VERSION 5.8 ;
BUSBITCHARS "[]" ;
DIVIDERCHAR "/" ;
UNITS
    DATABASE MICRONS 1000 ;
END UNITS

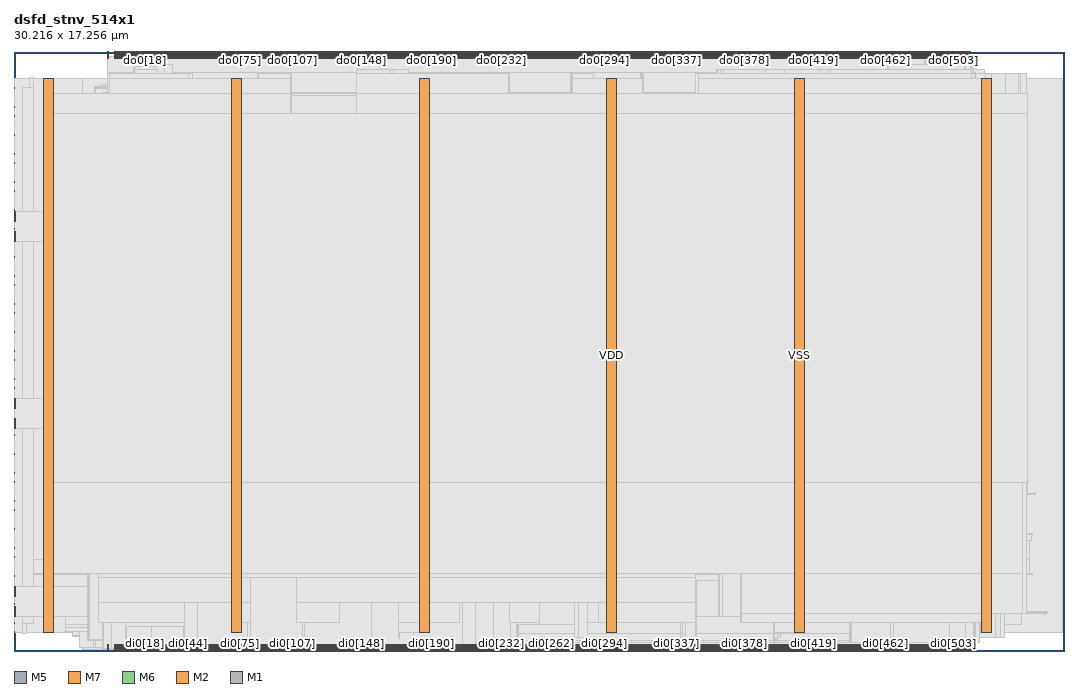
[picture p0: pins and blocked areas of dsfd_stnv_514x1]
MACRO dsfd_stnv_514x1
  FOREIGN dsfd_stnv_514x1 0 0 ;
  CLASS BLOCK ;
  SIZE 30.216 BY 17.256 ;
  PIN di0[0]
    DIRECTION INPUT ;
    USE SIGNAL ;
    PORT
      LAYER M5 ;
        RECT  2.88 0 2.904 0.192 ;
    END
  END di0[0]
  PIN di0[100]
    DIRECTION INPUT ;
    USE SIGNAL ;
    PORT
      LAYER M5 ;
        RECT  7.68 0 7.704 0.192 ;
    END
  END di0[100]
  PIN di0[101]
    DIRECTION INPUT ;
    USE SIGNAL ;
    PORT
      LAYER M5 ;
        RECT  7.728 0 7.752 0.192 ;
    END
  END di0[101]
  PIN di0[102]
    DIRECTION INPUT ;
    USE SIGNAL ;
    PORT
      LAYER M5 ;
        RECT  7.776 0 7.8 0.192 ;
    END
  END di0[102]
  PIN di0[103]
    DIRECTION INPUT ;
    USE SIGNAL ;
    PORT
      LAYER M5 ;
        RECT  7.824 0 7.848 0.192 ;
    END
  END di0[103]
  PIN di0[104]
    DIRECTION INPUT ;
    USE SIGNAL ;
    PORT
      LAYER M5 ;
        RECT  7.872 0 7.896 0.192 ;
    END
  END di0[104]
  PIN di0[105]
    DIRECTION INPUT ;
    USE SIGNAL ;
    PORT
      LAYER M5 ;
        RECT  7.92 0 7.944 0.192 ;
    END
  END di0[105]
  PIN di0[106]
    DIRECTION INPUT ;
    USE SIGNAL ;
    PORT
      LAYER M5 ;
        RECT  7.968 0 7.992 0.192 ;
    END
  END di0[106]
  PIN di0[107]
    DIRECTION INPUT ;
    USE SIGNAL ;
    PORT
      LAYER M5 ;
        RECT  8.016 0 8.04 0.192 ;
    END
  END di0[107]
  PIN di0[108]
    DIRECTION INPUT ;
    USE SIGNAL ;
    PORT
      LAYER M5 ;
        RECT  8.064 0 8.088 0.192 ;
    END
  END di0[108]
  PIN di0[109]
    DIRECTION INPUT ;
    USE SIGNAL ;
    PORT
      LAYER M5 ;
        RECT  8.112 0 8.136 0.192 ;
    END
  END di0[109]
  PIN di0[10]
    DIRECTION INPUT ;
    USE SIGNAL ;
    PORT
      LAYER M5 ;
        RECT  3.36 0 3.384 0.192 ;
    END
  END di0[10]
  PIN di0[110]
    DIRECTION INPUT ;
    USE SIGNAL ;
    PORT
      LAYER M5 ;
        RECT  8.16 0 8.184 0.192 ;
    END
  END di0[110]
  PIN di0[111]
    DIRECTION INPUT ;
    USE SIGNAL ;
    PORT
      LAYER M5 ;
        RECT  8.208 0 8.232 0.192 ;
    END
  END di0[111]
  PIN di0[112]
    DIRECTION INPUT ;
    USE SIGNAL ;
    PORT
      LAYER M5 ;
        RECT  8.256 0 8.28 0.192 ;
    END
  END di0[112]
  PIN di0[113]
    DIRECTION INPUT ;
    USE SIGNAL ;
    PORT
      LAYER M5 ;
        RECT  8.304 0 8.328 0.192 ;
    END
  END di0[113]
  PIN di0[114]
    DIRECTION INPUT ;
    USE SIGNAL ;
    PORT
      LAYER M5 ;
        RECT  8.352 0 8.376 0.192 ;
    END
  END di0[114]
  PIN di0[115]
    DIRECTION INPUT ;
    USE SIGNAL ;
    PORT
      LAYER M5 ;
        RECT  8.4 0 8.424 0.192 ;
    END
  END di0[115]
  PIN di0[116]
    DIRECTION INPUT ;
    USE SIGNAL ;
    PORT
      LAYER M5 ;
        RECT  8.448 0 8.472 0.192 ;
    END
  END di0[116]
  PIN di0[117]
    DIRECTION INPUT ;
    USE SIGNAL ;
    PORT
      LAYER M5 ;
        RECT  8.496 0 8.52 0.192 ;
    END
  END di0[117]
  PIN di0[118]
    DIRECTION INPUT ;
    USE SIGNAL ;
    PORT
      LAYER M5 ;
        RECT  8.544 0 8.568 0.192 ;
    END
  END di0[118]
  PIN di0[119]
    DIRECTION INPUT ;
    USE SIGNAL ;
    PORT
      LAYER M5 ;
        RECT  8.592 0 8.616 0.192 ;
    END
  END di0[119]
  PIN di0[11]
    DIRECTION INPUT ;
    USE SIGNAL ;
    PORT
      LAYER M5 ;
        RECT  3.408 0 3.432 0.192 ;
    END
  END di0[11]
  PIN di0[120]
    DIRECTION INPUT ;
    USE SIGNAL ;
    PORT
      LAYER M5 ;
        RECT  8.64 0 8.664 0.192 ;
    END
  END di0[120]
  PIN di0[121]
    DIRECTION INPUT ;
    USE SIGNAL ;
    PORT
      LAYER M5 ;
        RECT  8.688 0 8.712 0.192 ;
    END
  END di0[121]
  PIN di0[122]
    DIRECTION INPUT ;
    USE SIGNAL ;
    PORT
      LAYER M5 ;
        RECT  8.736 0 8.76 0.192 ;
    END
  END di0[122]
  PIN di0[123]
    DIRECTION INPUT ;
    USE SIGNAL ;
    PORT
      LAYER M5 ;
        RECT  8.784 0 8.808 0.192 ;
    END
  END di0[123]
  PIN di0[124]
    DIRECTION INPUT ;
    USE SIGNAL ;
    PORT
      LAYER M5 ;
        RECT  8.832 0 8.856 0.192 ;
    END
  END di0[124]
  PIN di0[125]
    DIRECTION INPUT ;
    USE SIGNAL ;
    PORT
      LAYER M5 ;
        RECT  8.88 0 8.904 0.192 ;
    END
  END di0[125]
  PIN di0[126]
    DIRECTION INPUT ;
    USE SIGNAL ;
    PORT
      LAYER M5 ;
        RECT  8.928 0 8.952 0.192 ;
    END
  END di0[126]
  PIN di0[127]
    DIRECTION INPUT ;
    USE SIGNAL ;
    PORT
      LAYER M5 ;
        RECT  8.976 0 9 0.192 ;
    END
  END di0[127]
  PIN di0[128]
    DIRECTION INPUT ;
    USE SIGNAL ;
    PORT
      LAYER M5 ;
        RECT  9.024 0 9.048 0.192 ;
    END
  END di0[128]
  PIN di0[129]
    DIRECTION INPUT ;
    USE SIGNAL ;
    PORT
      LAYER M5 ;
        RECT  9.072 0 9.096 0.192 ;
    END
  END di0[129]
  PIN di0[12]
    DIRECTION INPUT ;
    USE SIGNAL ;
    PORT
      LAYER M5 ;
        RECT  3.456 0 3.48 0.192 ;
    END
  END di0[12]
  PIN di0[130]
    DIRECTION INPUT ;
    USE SIGNAL ;
    PORT
      LAYER M5 ;
        RECT  9.12 0 9.144 0.192 ;
    END
  END di0[130]
  PIN di0[131]
    DIRECTION INPUT ;
    USE SIGNAL ;
    PORT
      LAYER M5 ;
        RECT  9.168 0 9.192 0.192 ;
    END
  END di0[131]
  PIN di0[132]
    DIRECTION INPUT ;
    USE SIGNAL ;
    PORT
      LAYER M5 ;
        RECT  9.216 0 9.24 0.192 ;
    END
  END di0[132]
  PIN di0[133]
    DIRECTION INPUT ;
    USE SIGNAL ;
    PORT
      LAYER M5 ;
        RECT  9.264 0 9.288 0.192 ;
    END
  END di0[133]
  PIN di0[134]
    DIRECTION INPUT ;
    USE SIGNAL ;
    PORT
      LAYER M5 ;
        RECT  9.312 0 9.336 0.192 ;
    END
  END di0[134]
  PIN di0[135]
    DIRECTION INPUT ;
    USE SIGNAL ;
    PORT
      LAYER M5 ;
        RECT  9.36 0 9.384 0.192 ;
    END
  END di0[135]
  PIN di0[136]
    DIRECTION INPUT ;
    USE SIGNAL ;
    PORT
      LAYER M5 ;
        RECT  9.408 0 9.432 0.192 ;
    END
  END di0[136]
  PIN di0[137]
    DIRECTION INPUT ;
    USE SIGNAL ;
    PORT
      LAYER M5 ;
        RECT  9.456 0 9.48 0.192 ;
    END
  END di0[137]
  PIN di0[138]
    DIRECTION INPUT ;
    USE SIGNAL ;
    PORT
      LAYER M5 ;
        RECT  9.504 0 9.528 0.192 ;
    END
  END di0[138]
  PIN di0[139]
    DIRECTION INPUT ;
    USE SIGNAL ;
    PORT
      LAYER M5 ;
        RECT  9.552 0 9.576 0.192 ;
    END
  END di0[139]
  PIN di0[13]
    DIRECTION INPUT ;
    USE SIGNAL ;
    PORT
      LAYER M5 ;
        RECT  3.504 0 3.528 0.192 ;
    END
  END di0[13]
  PIN di0[140]
    DIRECTION INPUT ;
    USE SIGNAL ;
    PORT
      LAYER M5 ;
        RECT  9.6 0 9.624 0.192 ;
    END
  END di0[140]
  PIN di0[141]
    DIRECTION INPUT ;
    USE SIGNAL ;
    PORT
      LAYER M5 ;
        RECT  9.648 0 9.672 0.192 ;
    END
  END di0[141]
  PIN di0[142]
    DIRECTION INPUT ;
    USE SIGNAL ;
    PORT
      LAYER M5 ;
        RECT  9.696 0 9.72 0.192 ;
    END
  END di0[142]
  PIN di0[143]
    DIRECTION INPUT ;
    USE SIGNAL ;
    PORT
      LAYER M5 ;
        RECT  9.744 0 9.768 0.192 ;
    END
  END di0[143]
  PIN di0[144]
    DIRECTION INPUT ;
    USE SIGNAL ;
    PORT
      LAYER M5 ;
        RECT  9.792 0 9.816 0.192 ;
    END
  END di0[144]
  PIN di0[145]
    DIRECTION INPUT ;
    USE SIGNAL ;
    PORT
      LAYER M5 ;
        RECT  9.84 0 9.864 0.192 ;
    END
  END di0[145]
  PIN di0[146]
    DIRECTION INPUT ;
    USE SIGNAL ;
    PORT
      LAYER M5 ;
        RECT  9.888 0 9.912 0.192 ;
    END
  END di0[146]
  PIN di0[147]
    DIRECTION INPUT ;
    USE SIGNAL ;
    PORT
      LAYER M5 ;
        RECT  9.936 0 9.96 0.192 ;
    END
  END di0[147]
  PIN di0[148]
    DIRECTION INPUT ;
    USE SIGNAL ;
    PORT
      LAYER M5 ;
        RECT  9.984 0 10.008 0.192 ;
    END
  END di0[148]
  PIN di0[149]
    DIRECTION INPUT ;
    USE SIGNAL ;
    PORT
      LAYER M5 ;
        RECT  10.032 0 10.056 0.192 ;
    END
  END di0[149]
  PIN di0[14]
    DIRECTION INPUT ;
    USE SIGNAL ;
    PORT
      LAYER M5 ;
        RECT  3.552 0 3.576 0.192 ;
    END
  END di0[14]
  PIN di0[150]
    DIRECTION INPUT ;
    USE SIGNAL ;
    PORT
      LAYER M5 ;
        RECT  10.08 0 10.104 0.192 ;
    END
  END di0[150]
  PIN di0[151]
    DIRECTION INPUT ;
    USE SIGNAL ;
    PORT
      LAYER M5 ;
        RECT  10.128 0 10.152 0.192 ;
    END
  END di0[151]
  PIN di0[152]
    DIRECTION INPUT ;
    USE SIGNAL ;
    PORT
      LAYER M5 ;
        RECT  10.176 0 10.2 0.192 ;
    END
  END di0[152]
  PIN di0[153]
    DIRECTION INPUT ;
    USE SIGNAL ;
    PORT
      LAYER M5 ;
        RECT  10.224 0 10.248 0.192 ;
    END
  END di0[153]
  PIN di0[154]
    DIRECTION INPUT ;
    USE SIGNAL ;
    PORT
      LAYER M5 ;
        RECT  10.272 0 10.296 0.192 ;
    END
  END di0[154]
  PIN di0[155]
    DIRECTION INPUT ;
    USE SIGNAL ;
    PORT
      LAYER M5 ;
        RECT  10.32 0 10.344 0.192 ;
    END
  END di0[155]
  PIN di0[156]
    DIRECTION INPUT ;
    USE SIGNAL ;
    PORT
      LAYER M5 ;
        RECT  10.368 0 10.392 0.192 ;
    END
  END di0[156]
  PIN di0[157]
    DIRECTION INPUT ;
    USE SIGNAL ;
    PORT
      LAYER M5 ;
        RECT  10.416 0 10.44 0.192 ;
    END
  END di0[157]
  PIN di0[158]
    DIRECTION INPUT ;
    USE SIGNAL ;
    PORT
      LAYER M5 ;
        RECT  10.464 0 10.488 0.192 ;
    END
  END di0[158]
  PIN di0[159]
    DIRECTION INPUT ;
    USE SIGNAL ;
    PORT
      LAYER M5 ;
        RECT  10.512 0 10.536 0.192 ;
    END
  END di0[159]
  PIN di0[15]
    DIRECTION INPUT ;
    USE SIGNAL ;
    PORT
      LAYER M5 ;
        RECT  3.6 0 3.624 0.192 ;
    END
  END di0[15]
  PIN di0[160]
    DIRECTION INPUT ;
    USE SIGNAL ;
    PORT
      LAYER M5 ;
        RECT  10.56 0 10.584 0.192 ;
    END
  END di0[160]
  PIN di0[161]
    DIRECTION INPUT ;
    USE SIGNAL ;
    PORT
      LAYER M5 ;
        RECT  10.608 0 10.632 0.192 ;
    END
  END di0[161]
  PIN di0[162]
    DIRECTION INPUT ;
    USE SIGNAL ;
    PORT
      LAYER M5 ;
        RECT  10.656 0 10.68 0.192 ;
    END
  END di0[162]
  PIN di0[163]
    DIRECTION INPUT ;
    USE SIGNAL ;
    PORT
      LAYER M5 ;
        RECT  10.704 0 10.728 0.192 ;
    END
  END di0[163]
  PIN di0[164]
    DIRECTION INPUT ;
    USE SIGNAL ;
    PORT
      LAYER M5 ;
        RECT  10.752 0 10.776 0.192 ;
    END
  END di0[164]
  PIN di0[165]
    DIRECTION INPUT ;
    USE SIGNAL ;
    PORT
      LAYER M5 ;
        RECT  10.8 0 10.824 0.192 ;
    END
  END di0[165]
  PIN di0[166]
    DIRECTION INPUT ;
    USE SIGNAL ;
    PORT
      LAYER M5 ;
        RECT  10.848 0 10.872 0.192 ;
    END
  END di0[166]
  PIN di0[167]
    DIRECTION INPUT ;
    USE SIGNAL ;
    PORT
      LAYER M5 ;
        RECT  10.896 0 10.92 0.192 ;
    END
  END di0[167]
  PIN di0[168]
    DIRECTION INPUT ;
    USE SIGNAL ;
    PORT
      LAYER M5 ;
        RECT  10.944 0 10.968 0.192 ;
    END
  END di0[168]
  PIN di0[169]
    DIRECTION INPUT ;
    USE SIGNAL ;
    PORT
      LAYER M5 ;
        RECT  10.992 0 11.016 0.192 ;
    END
  END di0[169]
  PIN di0[16]
    DIRECTION INPUT ;
    USE SIGNAL ;
    PORT
      LAYER M5 ;
        RECT  3.648 0 3.672 0.192 ;
    END
  END di0[16]
  PIN di0[170]
    DIRECTION INPUT ;
    USE SIGNAL ;
    PORT
      LAYER M5 ;
        RECT  11.04 0 11.064 0.192 ;
    END
  END di0[170]
  PIN di0[171]
    DIRECTION INPUT ;
    USE SIGNAL ;
    PORT
      LAYER M5 ;
        RECT  11.088 0 11.112 0.192 ;
    END
  END di0[171]
  PIN di0[172]
    DIRECTION INPUT ;
    USE SIGNAL ;
    PORT
      LAYER M5 ;
        RECT  11.136 0 11.16 0.192 ;
    END
  END di0[172]
  PIN di0[173]
    DIRECTION INPUT ;
    USE SIGNAL ;
    PORT
      LAYER M5 ;
        RECT  11.184 0 11.208 0.192 ;
    END
  END di0[173]
  PIN di0[174]
    DIRECTION INPUT ;
    USE SIGNAL ;
    PORT
      LAYER M5 ;
        RECT  11.232 0 11.256 0.192 ;
    END
  END di0[174]
  PIN di0[175]
    DIRECTION INPUT ;
    USE SIGNAL ;
    PORT
      LAYER M5 ;
        RECT  11.28 0 11.304 0.192 ;
    END
  END di0[175]
  PIN di0[176]
    DIRECTION INPUT ;
    USE SIGNAL ;
    PORT
      LAYER M5 ;
        RECT  11.328 0 11.352 0.192 ;
    END
  END di0[176]
  PIN di0[177]
    DIRECTION INPUT ;
    USE SIGNAL ;
    PORT
      LAYER M5 ;
        RECT  11.376 0 11.4 0.192 ;
    END
  END di0[177]
  PIN di0[178]
    DIRECTION INPUT ;
    USE SIGNAL ;
    PORT
      LAYER M5 ;
        RECT  11.424 0 11.448 0.192 ;
    END
  END di0[178]
  PIN di0[179]
    DIRECTION INPUT ;
    USE SIGNAL ;
    PORT
      LAYER M5 ;
        RECT  11.472 0 11.496 0.192 ;
    END
  END di0[179]
  PIN di0[17]
    DIRECTION INPUT ;
    USE SIGNAL ;
    PORT
      LAYER M5 ;
        RECT  3.696 0 3.72 0.192 ;
    END
  END di0[17]
  PIN di0[180]
    DIRECTION INPUT ;
    USE SIGNAL ;
    PORT
      LAYER M5 ;
        RECT  11.52 0 11.544 0.192 ;
    END
  END di0[180]
  PIN di0[181]
    DIRECTION INPUT ;
    USE SIGNAL ;
    PORT
      LAYER M5 ;
        RECT  11.568 0 11.592 0.192 ;
    END
  END di0[181]
  PIN di0[182]
    DIRECTION INPUT ;
    USE SIGNAL ;
    PORT
      LAYER M5 ;
        RECT  11.616 0 11.64 0.192 ;
    END
  END di0[182]
  PIN di0[183]
    DIRECTION INPUT ;
    USE SIGNAL ;
    PORT
      LAYER M5 ;
        RECT  11.664 0 11.688 0.192 ;
    END
  END di0[183]
  PIN di0[184]
    DIRECTION INPUT ;
    USE SIGNAL ;
    PORT
      LAYER M5 ;
        RECT  11.712 0 11.736 0.192 ;
    END
  END di0[184]
  PIN di0[185]
    DIRECTION INPUT ;
    USE SIGNAL ;
    PORT
      LAYER M5 ;
        RECT  11.76 0 11.784 0.192 ;
    END
  END di0[185]
  PIN di0[186]
    DIRECTION INPUT ;
    USE SIGNAL ;
    PORT
      LAYER M5 ;
        RECT  11.808 0 11.832 0.192 ;
    END
  END di0[186]
  PIN di0[187]
    DIRECTION INPUT ;
    USE SIGNAL ;
    PORT
      LAYER M5 ;
        RECT  11.856 0 11.88 0.192 ;
    END
  END di0[187]
  PIN di0[188]
    DIRECTION INPUT ;
    USE SIGNAL ;
    PORT
      LAYER M5 ;
        RECT  11.904 0 11.928 0.192 ;
    END
  END di0[188]
  PIN di0[189]
    DIRECTION INPUT ;
    USE SIGNAL ;
    PORT
      LAYER M5 ;
        RECT  11.952 0 11.976 0.192 ;
    END
  END di0[189]
  PIN di0[18]
    DIRECTION INPUT ;
    USE SIGNAL ;
    PORT
      LAYER M5 ;
        RECT  3.744 0 3.768 0.192 ;
    END
  END di0[18]
  PIN di0[190]
    DIRECTION INPUT ;
    USE SIGNAL ;
    PORT
      LAYER M5 ;
        RECT  12 0 12.024 0.192 ;
    END
  END di0[190]
  PIN di0[191]
    DIRECTION INPUT ;
    USE SIGNAL ;
    PORT
      LAYER M5 ;
        RECT  12.048 0 12.072 0.192 ;
    END
  END di0[191]
  PIN di0[192]
    DIRECTION INPUT ;
    USE SIGNAL ;
    PORT
      LAYER M5 ;
        RECT  12.096 0 12.12 0.192 ;
    END
  END di0[192]
  PIN di0[193]
    DIRECTION INPUT ;
    USE SIGNAL ;
    PORT
      LAYER M5 ;
        RECT  12.144 0 12.168 0.192 ;
    END
  END di0[193]
  PIN di0[194]
    DIRECTION INPUT ;
    USE SIGNAL ;
    PORT
      LAYER M5 ;
        RECT  12.192 0 12.216 0.192 ;
    END
  END di0[194]
  PIN di0[195]
    DIRECTION INPUT ;
    USE SIGNAL ;
    PORT
      LAYER M5 ;
        RECT  12.24 0 12.264 0.192 ;
    END
  END di0[195]
  PIN di0[196]
    DIRECTION INPUT ;
    USE SIGNAL ;
    PORT
      LAYER M5 ;
        RECT  12.288 0 12.312 0.192 ;
    END
  END di0[196]
  PIN di0[197]
    DIRECTION INPUT ;
    USE SIGNAL ;
    PORT
      LAYER M5 ;
        RECT  12.336 0 12.36 0.192 ;
    END
  END di0[197]
  PIN di0[198]
    DIRECTION INPUT ;
    USE SIGNAL ;
    PORT
      LAYER M5 ;
        RECT  12.384 0 12.408 0.192 ;
    END
  END di0[198]
  PIN di0[199]
    DIRECTION INPUT ;
    USE SIGNAL ;
    PORT
      LAYER M5 ;
        RECT  12.432 0 12.456 0.192 ;
    END
  END di0[199]
  PIN di0[19]
    DIRECTION INPUT ;
    USE SIGNAL ;
    PORT
      LAYER M5 ;
        RECT  3.792 0 3.816 0.192 ;
    END
  END di0[19]
  PIN di0[1]
    DIRECTION INPUT ;
    USE SIGNAL ;
    PORT
      LAYER M5 ;
        RECT  2.928 0 2.952 0.192 ;
    END
  END di0[1]
  PIN di0[200]
    DIRECTION INPUT ;
    USE SIGNAL ;
    PORT
      LAYER M5 ;
        RECT  12.48 0 12.504 0.192 ;
    END
  END di0[200]
  PIN di0[201]
    DIRECTION INPUT ;
    USE SIGNAL ;
    PORT
      LAYER M5 ;
        RECT  12.528 0 12.552 0.192 ;
    END
  END di0[201]
  PIN di0[202]
    DIRECTION INPUT ;
    USE SIGNAL ;
    PORT
      LAYER M5 ;
        RECT  12.576 0 12.6 0.192 ;
    END
  END di0[202]
  PIN di0[203]
    DIRECTION INPUT ;
    USE SIGNAL ;
    PORT
      LAYER M5 ;
        RECT  12.624 0 12.648 0.192 ;
    END
  END di0[203]
  PIN di0[204]
    DIRECTION INPUT ;
    USE SIGNAL ;
    PORT
      LAYER M5 ;
        RECT  12.672 0 12.696 0.192 ;
    END
  END di0[204]
  PIN di0[205]
    DIRECTION INPUT ;
    USE SIGNAL ;
    PORT
      LAYER M5 ;
        RECT  12.72 0 12.744 0.192 ;
    END
  END di0[205]
  PIN di0[206]
    DIRECTION INPUT ;
    USE SIGNAL ;
    PORT
      LAYER M5 ;
        RECT  12.768 0 12.792 0.192 ;
    END
  END di0[206]
  PIN di0[207]
    DIRECTION INPUT ;
    USE SIGNAL ;
    PORT
      LAYER M5 ;
        RECT  12.816 0 12.84 0.192 ;
    END
  END di0[207]
  PIN di0[208]
    DIRECTION INPUT ;
    USE SIGNAL ;
    PORT
      LAYER M5 ;
        RECT  12.864 0 12.888 0.192 ;
    END
  END di0[208]
  PIN di0[209]
    DIRECTION INPUT ;
    USE SIGNAL ;
    PORT
      LAYER M5 ;
        RECT  12.912 0 12.936 0.192 ;
    END
  END di0[209]
  PIN di0[20]
    DIRECTION INPUT ;
    USE SIGNAL ;
    PORT
      LAYER M5 ;
        RECT  3.84 0 3.864 0.192 ;
    END
  END di0[20]
  PIN di0[210]
    DIRECTION INPUT ;
    USE SIGNAL ;
    PORT
      LAYER M5 ;
        RECT  12.96 0 12.984 0.192 ;
    END
  END di0[210]
  PIN di0[211]
    DIRECTION INPUT ;
    USE SIGNAL ;
    PORT
      LAYER M5 ;
        RECT  13.008 0 13.032 0.192 ;
    END
  END di0[211]
  PIN di0[212]
    DIRECTION INPUT ;
    USE SIGNAL ;
    PORT
      LAYER M5 ;
        RECT  13.056 0 13.08 0.192 ;
    END
  END di0[212]
  PIN di0[213]
    DIRECTION INPUT ;
    USE SIGNAL ;
    PORT
      LAYER M5 ;
        RECT  13.104 0 13.128 0.192 ;
    END
  END di0[213]
  PIN di0[214]
    DIRECTION INPUT ;
    USE SIGNAL ;
    PORT
      LAYER M5 ;
        RECT  13.152 0 13.176 0.192 ;
    END
  END di0[214]
  PIN di0[215]
    DIRECTION INPUT ;
    USE SIGNAL ;
    PORT
      LAYER M5 ;
        RECT  13.2 0 13.224 0.192 ;
    END
  END di0[215]
  PIN di0[216]
    DIRECTION INPUT ;
    USE SIGNAL ;
    PORT
      LAYER M5 ;
        RECT  13.248 0 13.272 0.192 ;
    END
  END di0[216]
  PIN di0[217]
    DIRECTION INPUT ;
    USE SIGNAL ;
    PORT
      LAYER M5 ;
        RECT  13.296 0 13.32 0.192 ;
    END
  END di0[217]
  PIN di0[218]
    DIRECTION INPUT ;
    USE SIGNAL ;
    PORT
      LAYER M5 ;
        RECT  13.344 0 13.368 0.192 ;
    END
  END di0[218]
  PIN di0[219]
    DIRECTION INPUT ;
    USE SIGNAL ;
    PORT
      LAYER M5 ;
        RECT  13.392 0 13.416 0.192 ;
    END
  END di0[219]
  PIN di0[21]
    DIRECTION INPUT ;
    USE SIGNAL ;
    PORT
      LAYER M5 ;
        RECT  3.888 0 3.912 0.192 ;
    END
  END di0[21]
  PIN di0[220]
    DIRECTION INPUT ;
    USE SIGNAL ;
    PORT
      LAYER M5 ;
        RECT  13.44 0 13.464 0.192 ;
    END
  END di0[220]
  PIN di0[221]
    DIRECTION INPUT ;
    USE SIGNAL ;
    PORT
      LAYER M5 ;
        RECT  13.488 0 13.512 0.192 ;
    END
  END di0[221]
  PIN di0[222]
    DIRECTION INPUT ;
    USE SIGNAL ;
    PORT
      LAYER M5 ;
        RECT  13.536 0 13.56 0.192 ;
    END
  END di0[222]
  PIN di0[223]
    DIRECTION INPUT ;
    USE SIGNAL ;
    PORT
      LAYER M5 ;
        RECT  13.584 0 13.608 0.192 ;
    END
  END di0[223]
  PIN di0[224]
    DIRECTION INPUT ;
    USE SIGNAL ;
    PORT
      LAYER M5 ;
        RECT  13.632 0 13.656 0.192 ;
    END
  END di0[224]
  PIN di0[225]
    DIRECTION INPUT ;
    USE SIGNAL ;
    PORT
      LAYER M5 ;
        RECT  13.68 0 13.704 0.192 ;
    END
  END di0[225]
  PIN di0[226]
    DIRECTION INPUT ;
    USE SIGNAL ;
    PORT
      LAYER M5 ;
        RECT  13.728 0 13.752 0.192 ;
    END
  END di0[226]
  PIN di0[227]
    DIRECTION INPUT ;
    USE SIGNAL ;
    PORT
      LAYER M5 ;
        RECT  13.776 0 13.8 0.192 ;
    END
  END di0[227]
  PIN di0[228]
    DIRECTION INPUT ;
    USE SIGNAL ;
    PORT
      LAYER M5 ;
        RECT  13.824 0 13.848 0.192 ;
    END
  END di0[228]
  PIN di0[229]
    DIRECTION INPUT ;
    USE SIGNAL ;
    PORT
      LAYER M5 ;
        RECT  13.872 0 13.896 0.192 ;
    END
  END di0[229]
  PIN di0[22]
    DIRECTION INPUT ;
    USE SIGNAL ;
    PORT
      LAYER M5 ;
        RECT  3.936 0 3.96 0.192 ;
    END
  END di0[22]
  PIN di0[230]
    DIRECTION INPUT ;
    USE SIGNAL ;
    PORT
      LAYER M5 ;
        RECT  13.92 0 13.944 0.192 ;
    END
  END di0[230]
  PIN di0[231]
    DIRECTION INPUT ;
    USE SIGNAL ;
    PORT
      LAYER M5 ;
        RECT  13.968 0 13.992 0.192 ;
    END
  END di0[231]
  PIN di0[232]
    DIRECTION INPUT ;
    USE SIGNAL ;
    PORT
      LAYER M5 ;
        RECT  14.016 0 14.04 0.192 ;
    END
  END di0[232]
  PIN di0[233]
    DIRECTION INPUT ;
    USE SIGNAL ;
    PORT
      LAYER M5 ;
        RECT  14.064 0 14.088 0.192 ;
    END
  END di0[233]
  PIN di0[234]
    DIRECTION INPUT ;
    USE SIGNAL ;
    PORT
      LAYER M5 ;
        RECT  14.112 0 14.136 0.192 ;
    END
  END di0[234]
  PIN di0[235]
    DIRECTION INPUT ;
    USE SIGNAL ;
    PORT
      LAYER M5 ;
        RECT  14.16 0 14.184 0.192 ;
    END
  END di0[235]
  PIN di0[236]
    DIRECTION INPUT ;
    USE SIGNAL ;
    PORT
      LAYER M5 ;
        RECT  14.208 0 14.232 0.192 ;
    END
  END di0[236]
  PIN di0[237]
    DIRECTION INPUT ;
    USE SIGNAL ;
    PORT
      LAYER M5 ;
        RECT  14.256 0 14.28 0.192 ;
    END
  END di0[237]
  PIN di0[238]
    DIRECTION INPUT ;
    USE SIGNAL ;
    PORT
      LAYER M5 ;
        RECT  14.304 0 14.328 0.192 ;
    END
  END di0[238]
  PIN di0[239]
    DIRECTION INPUT ;
    USE SIGNAL ;
    PORT
      LAYER M5 ;
        RECT  14.352 0 14.376 0.192 ;
    END
  END di0[239]
  PIN di0[23]
    DIRECTION INPUT ;
    USE SIGNAL ;
    PORT
      LAYER M5 ;
        RECT  3.984 0 4.008 0.192 ;
    END
  END di0[23]
  PIN di0[240]
    DIRECTION INPUT ;
    USE SIGNAL ;
    PORT
      LAYER M5 ;
        RECT  14.4 0 14.424 0.192 ;
    END
  END di0[240]
  PIN di0[241]
    DIRECTION INPUT ;
    USE SIGNAL ;
    PORT
      LAYER M5 ;
        RECT  14.448 0 14.472 0.192 ;
    END
  END di0[241]
  PIN di0[242]
    DIRECTION INPUT ;
    USE SIGNAL ;
    PORT
      LAYER M5 ;
        RECT  14.496 0 14.52 0.192 ;
    END
  END di0[242]
  PIN di0[243]
    DIRECTION INPUT ;
    USE SIGNAL ;
    PORT
      LAYER M5 ;
        RECT  14.544 0 14.568 0.192 ;
    END
  END di0[243]
  PIN di0[244]
    DIRECTION INPUT ;
    USE SIGNAL ;
    PORT
      LAYER M5 ;
        RECT  14.592 0 14.616 0.192 ;
    END
  END di0[244]
  PIN di0[245]
    DIRECTION INPUT ;
    USE SIGNAL ;
    PORT
      LAYER M5 ;
        RECT  14.64 0 14.664 0.192 ;
    END
  END di0[245]
  PIN di0[246]
    DIRECTION INPUT ;
    USE SIGNAL ;
    PORT
      LAYER M5 ;
        RECT  14.688 0 14.712 0.192 ;
    END
  END di0[246]
  PIN di0[247]
    DIRECTION INPUT ;
    USE SIGNAL ;
    PORT
      LAYER M5 ;
        RECT  14.736 0 14.76 0.192 ;
    END
  END di0[247]
  PIN di0[248]
    DIRECTION INPUT ;
    USE SIGNAL ;
    PORT
      LAYER M5 ;
        RECT  14.784 0 14.808 0.192 ;
    END
  END di0[248]
  PIN di0[249]
    DIRECTION INPUT ;
    USE SIGNAL ;
    PORT
      LAYER M5 ;
        RECT  14.832 0 14.856 0.192 ;
    END
  END di0[249]
  PIN di0[24]
    DIRECTION INPUT ;
    USE SIGNAL ;
    PORT
      LAYER M5 ;
        RECT  4.032 0 4.056 0.192 ;
    END
  END di0[24]
  PIN di0[250]
    DIRECTION INPUT ;
    USE SIGNAL ;
    PORT
      LAYER M5 ;
        RECT  14.88 0 14.904 0.192 ;
    END
  END di0[250]
  PIN di0[251]
    DIRECTION INPUT ;
    USE SIGNAL ;
    PORT
      LAYER M5 ;
        RECT  14.928 0 14.952 0.192 ;
    END
  END di0[251]
  PIN di0[252]
    DIRECTION INPUT ;
    USE SIGNAL ;
    PORT
      LAYER M5 ;
        RECT  14.976 0 15 0.192 ;
    END
  END di0[252]
  PIN di0[253]
    DIRECTION INPUT ;
    USE SIGNAL ;
    PORT
      LAYER M5 ;
        RECT  15.024 0 15.048 0.192 ;
    END
  END di0[253]
  PIN di0[254]
    DIRECTION INPUT ;
    USE SIGNAL ;
    PORT
      LAYER M5 ;
        RECT  15.072 0 15.096 0.192 ;
    END
  END di0[254]
  PIN di0[255]
    DIRECTION INPUT ;
    USE SIGNAL ;
    PORT
      LAYER M5 ;
        RECT  15.12 0 15.144 0.192 ;
    END
  END di0[255]
  PIN di0[256]
    DIRECTION INPUT ;
    USE SIGNAL ;
    PORT
      LAYER M5 ;
        RECT  15.168 0 15.192 0.192 ;
    END
  END di0[256]
  PIN di0[257]
    DIRECTION INPUT ;
    USE SIGNAL ;
    PORT
      LAYER M5 ;
        RECT  15.216 0 15.24 0.192 ;
    END
  END di0[257]
  PIN di0[258]
    DIRECTION INPUT ;
    USE SIGNAL ;
    PORT
      LAYER M5 ;
        RECT  15.264 0 15.288 0.192 ;
    END
  END di0[258]
  PIN di0[259]
    DIRECTION INPUT ;
    USE SIGNAL ;
    PORT
      LAYER M5 ;
        RECT  15.312 0 15.336 0.192 ;
    END
  END di0[259]
  PIN di0[25]
    DIRECTION INPUT ;
    USE SIGNAL ;
    PORT
      LAYER M5 ;
        RECT  4.08 0 4.104 0.192 ;
    END
  END di0[25]
  PIN di0[260]
    DIRECTION INPUT ;
    USE SIGNAL ;
    PORT
      LAYER M5 ;
        RECT  15.36 0 15.384 0.192 ;
    END
  END di0[260]
  PIN di0[261]
    DIRECTION INPUT ;
    USE SIGNAL ;
    PORT
      LAYER M5 ;
        RECT  15.408 0 15.432 0.192 ;
    END
  END di0[261]
  PIN di0[262]
    DIRECTION INPUT ;
    USE SIGNAL ;
    PORT
      LAYER M5 ;
        RECT  15.456 0 15.48 0.192 ;
    END
  END di0[262]
  PIN di0[263]
    DIRECTION INPUT ;
    USE SIGNAL ;
    PORT
      LAYER M5 ;
        RECT  15.504 0 15.528 0.192 ;
    END
  END di0[263]
  PIN di0[264]
    DIRECTION INPUT ;
    USE SIGNAL ;
    PORT
      LAYER M5 ;
        RECT  15.552 0 15.576 0.192 ;
    END
  END di0[264]
  PIN di0[265]
    DIRECTION INPUT ;
    USE SIGNAL ;
    PORT
      LAYER M5 ;
        RECT  15.6 0 15.624 0.192 ;
    END
  END di0[265]
  PIN di0[266]
    DIRECTION INPUT ;
    USE SIGNAL ;
    PORT
      LAYER M5 ;
        RECT  15.648 0 15.672 0.192 ;
    END
  END di0[266]
  PIN di0[267]
    DIRECTION INPUT ;
    USE SIGNAL ;
    PORT
      LAYER M5 ;
        RECT  15.696 0 15.72 0.192 ;
    END
  END di0[267]
  PIN di0[268]
    DIRECTION INPUT ;
    USE SIGNAL ;
    PORT
      LAYER M5 ;
        RECT  15.744 0 15.768 0.192 ;
    END
  END di0[268]
  PIN di0[269]
    DIRECTION INPUT ;
    USE SIGNAL ;
    PORT
      LAYER M5 ;
        RECT  15.792 0 15.816 0.192 ;
    END
  END di0[269]
  PIN di0[26]
    DIRECTION INPUT ;
    USE SIGNAL ;
    PORT
      LAYER M5 ;
        RECT  4.128 0 4.152 0.192 ;
    END
  END di0[26]
  PIN di0[270]
    DIRECTION INPUT ;
    USE SIGNAL ;
    PORT
      LAYER M5 ;
        RECT  15.84 0 15.864 0.192 ;
    END
  END di0[270]
  PIN di0[271]
    DIRECTION INPUT ;
    USE SIGNAL ;
    PORT
      LAYER M5 ;
        RECT  15.888 0 15.912 0.192 ;
    END
  END di0[271]
  PIN di0[272]
    DIRECTION INPUT ;
    USE SIGNAL ;
    PORT
      LAYER M5 ;
        RECT  15.936 0 15.96 0.192 ;
    END
  END di0[272]
  PIN di0[273]
    DIRECTION INPUT ;
    USE SIGNAL ;
    PORT
      LAYER M5 ;
        RECT  15.984 0 16.008 0.192 ;
    END
  END di0[273]
  PIN di0[274]
    DIRECTION INPUT ;
    USE SIGNAL ;
    PORT
      LAYER M5 ;
        RECT  16.032 0 16.056 0.192 ;
    END
  END di0[274]
  PIN di0[275]
    DIRECTION INPUT ;
    USE SIGNAL ;
    PORT
      LAYER M5 ;
        RECT  16.08 0 16.104 0.192 ;
    END
  END di0[275]
  PIN di0[276]
    DIRECTION INPUT ;
    USE SIGNAL ;
    PORT
      LAYER M5 ;
        RECT  16.128 0 16.152 0.192 ;
    END
  END di0[276]
  PIN di0[277]
    DIRECTION INPUT ;
    USE SIGNAL ;
    PORT
      LAYER M5 ;
        RECT  16.176 0 16.2 0.192 ;
    END
  END di0[277]
  PIN di0[278]
    DIRECTION INPUT ;
    USE SIGNAL ;
    PORT
      LAYER M5 ;
        RECT  16.224 0 16.248 0.192 ;
    END
  END di0[278]
  PIN di0[279]
    DIRECTION INPUT ;
    USE SIGNAL ;
    PORT
      LAYER M5 ;
        RECT  16.272 0 16.296 0.192 ;
    END
  END di0[279]
  PIN di0[27]
    DIRECTION INPUT ;
    USE SIGNAL ;
    PORT
      LAYER M5 ;
        RECT  4.176 0 4.2 0.192 ;
    END
  END di0[27]
  PIN di0[280]
    DIRECTION INPUT ;
    USE SIGNAL ;
    PORT
      LAYER M5 ;
        RECT  16.32 0 16.344 0.192 ;
    END
  END di0[280]
  PIN di0[281]
    DIRECTION INPUT ;
    USE SIGNAL ;
    PORT
      LAYER M5 ;
        RECT  16.368 0 16.392 0.192 ;
    END
  END di0[281]
  PIN di0[282]
    DIRECTION INPUT ;
    USE SIGNAL ;
    PORT
      LAYER M5 ;
        RECT  16.416 0 16.44 0.192 ;
    END
  END di0[282]
  PIN di0[283]
    DIRECTION INPUT ;
    USE SIGNAL ;
    PORT
      LAYER M5 ;
        RECT  16.464 0 16.488 0.192 ;
    END
  END di0[283]
  PIN di0[284]
    DIRECTION INPUT ;
    USE SIGNAL ;
    PORT
      LAYER M5 ;
        RECT  16.512 0 16.536 0.192 ;
    END
  END di0[284]
  PIN di0[285]
    DIRECTION INPUT ;
    USE SIGNAL ;
    PORT
      LAYER M5 ;
        RECT  16.56 0 16.584 0.192 ;
    END
  END di0[285]
  PIN di0[286]
    DIRECTION INPUT ;
    USE SIGNAL ;
    PORT
      LAYER M5 ;
        RECT  16.608 0 16.632 0.192 ;
    END
  END di0[286]
  PIN di0[287]
    DIRECTION INPUT ;
    USE SIGNAL ;
    PORT
      LAYER M5 ;
        RECT  16.656 0 16.68 0.192 ;
    END
  END di0[287]
  PIN di0[288]
    DIRECTION INPUT ;
    USE SIGNAL ;
    PORT
      LAYER M5 ;
        RECT  16.704 0 16.728 0.192 ;
    END
  END di0[288]
  PIN di0[289]
    DIRECTION INPUT ;
    USE SIGNAL ;
    PORT
      LAYER M5 ;
        RECT  16.752 0 16.776 0.192 ;
    END
  END di0[289]
  PIN di0[28]
    DIRECTION INPUT ;
    USE SIGNAL ;
    PORT
      LAYER M5 ;
        RECT  4.224 0 4.248 0.192 ;
    END
  END di0[28]
  PIN di0[290]
    DIRECTION INPUT ;
    USE SIGNAL ;
    PORT
      LAYER M5 ;
        RECT  16.8 0 16.824 0.192 ;
    END
  END di0[290]
  PIN di0[291]
    DIRECTION INPUT ;
    USE SIGNAL ;
    PORT
      LAYER M5 ;
        RECT  16.848 0 16.872 0.192 ;
    END
  END di0[291]
  PIN di0[292]
    DIRECTION INPUT ;
    USE SIGNAL ;
    PORT
      LAYER M5 ;
        RECT  16.896 0 16.92 0.192 ;
    END
  END di0[292]
  PIN di0[293]
    DIRECTION INPUT ;
    USE SIGNAL ;
    PORT
      LAYER M5 ;
        RECT  16.944 0 16.968 0.192 ;
    END
  END di0[293]
  PIN di0[294]
    DIRECTION INPUT ;
    USE SIGNAL ;
    PORT
      LAYER M5 ;
        RECT  16.992 0 17.016 0.192 ;
    END
  END di0[294]
  PIN di0[295]
    DIRECTION INPUT ;
    USE SIGNAL ;
    PORT
      LAYER M5 ;
        RECT  17.04 0 17.064 0.192 ;
    END
  END di0[295]
  PIN di0[296]
    DIRECTION INPUT ;
    USE SIGNAL ;
    PORT
      LAYER M5 ;
        RECT  17.088 0 17.112 0.192 ;
    END
  END di0[296]
  PIN di0[297]
    DIRECTION INPUT ;
    USE SIGNAL ;
    PORT
      LAYER M5 ;
        RECT  17.136 0 17.16 0.192 ;
    END
  END di0[297]
  PIN di0[298]
    DIRECTION INPUT ;
    USE SIGNAL ;
    PORT
      LAYER M5 ;
        RECT  17.184 0 17.208 0.192 ;
    END
  END di0[298]
  PIN di0[299]
    DIRECTION INPUT ;
    USE SIGNAL ;
    PORT
      LAYER M5 ;
        RECT  17.232 0 17.256 0.192 ;
    END
  END di0[299]
  PIN di0[29]
    DIRECTION INPUT ;
    USE SIGNAL ;
    PORT
      LAYER M5 ;
        RECT  4.272 0 4.296 0.192 ;
    END
  END di0[29]
  PIN di0[2]
    DIRECTION INPUT ;
    USE SIGNAL ;
    PORT
      LAYER M5 ;
        RECT  2.976 0 3 0.192 ;
    END
  END di0[2]
  PIN di0[300]
    DIRECTION INPUT ;
    USE SIGNAL ;
    PORT
      LAYER M5 ;
        RECT  17.28 0 17.304 0.192 ;
    END
  END di0[300]
  PIN di0[301]
    DIRECTION INPUT ;
    USE SIGNAL ;
    PORT
      LAYER M5 ;
        RECT  17.328 0 17.352 0.192 ;
    END
  END di0[301]
  PIN di0[302]
    DIRECTION INPUT ;
    USE SIGNAL ;
    PORT
      LAYER M5 ;
        RECT  17.376 0 17.4 0.192 ;
    END
  END di0[302]
  PIN di0[303]
    DIRECTION INPUT ;
    USE SIGNAL ;
    PORT
      LAYER M5 ;
        RECT  17.424 0 17.448 0.192 ;
    END
  END di0[303]
  PIN di0[304]
    DIRECTION INPUT ;
    USE SIGNAL ;
    PORT
      LAYER M5 ;
        RECT  17.472 0 17.496 0.192 ;
    END
  END di0[304]
  PIN di0[305]
    DIRECTION INPUT ;
    USE SIGNAL ;
    PORT
      LAYER M5 ;
        RECT  17.52 0 17.544 0.192 ;
    END
  END di0[305]
  PIN di0[306]
    DIRECTION INPUT ;
    USE SIGNAL ;
    PORT
      LAYER M5 ;
        RECT  17.568 0 17.592 0.192 ;
    END
  END di0[306]
  PIN di0[307]
    DIRECTION INPUT ;
    USE SIGNAL ;
    PORT
      LAYER M5 ;
        RECT  17.616 0 17.64 0.192 ;
    END
  END di0[307]
  PIN di0[308]
    DIRECTION INPUT ;
    USE SIGNAL ;
    PORT
      LAYER M5 ;
        RECT  17.664 0 17.688 0.192 ;
    END
  END di0[308]
  PIN di0[309]
    DIRECTION INPUT ;
    USE SIGNAL ;
    PORT
      LAYER M5 ;
        RECT  17.712 0 17.736 0.192 ;
    END
  END di0[309]
  PIN di0[30]
    DIRECTION INPUT ;
    USE SIGNAL ;
    PORT
      LAYER M5 ;
        RECT  4.32 0 4.344 0.192 ;
    END
  END di0[30]
  PIN di0[310]
    DIRECTION INPUT ;
    USE SIGNAL ;
    PORT
      LAYER M5 ;
        RECT  17.76 0 17.784 0.192 ;
    END
  END di0[310]
  PIN di0[311]
    DIRECTION INPUT ;
    USE SIGNAL ;
    PORT
      LAYER M5 ;
        RECT  17.808 0 17.832 0.192 ;
    END
  END di0[311]
  PIN di0[312]
    DIRECTION INPUT ;
    USE SIGNAL ;
    PORT
      LAYER M5 ;
        RECT  17.856 0 17.88 0.192 ;
    END
  END di0[312]
  PIN di0[313]
    DIRECTION INPUT ;
    USE SIGNAL ;
    PORT
      LAYER M5 ;
        RECT  17.904 0 17.928 0.192 ;
    END
  END di0[313]
  PIN di0[314]
    DIRECTION INPUT ;
    USE SIGNAL ;
    PORT
      LAYER M5 ;
        RECT  17.952 0 17.976 0.192 ;
    END
  END di0[314]
  PIN di0[315]
    DIRECTION INPUT ;
    USE SIGNAL ;
    PORT
      LAYER M5 ;
        RECT  18 0 18.024 0.192 ;
    END
  END di0[315]
  PIN di0[316]
    DIRECTION INPUT ;
    USE SIGNAL ;
    PORT
      LAYER M5 ;
        RECT  18.048 0 18.072 0.192 ;
    END
  END di0[316]
  PIN di0[317]
    DIRECTION INPUT ;
    USE SIGNAL ;
    PORT
      LAYER M5 ;
        RECT  18.096 0 18.12 0.192 ;
    END
  END di0[317]
  PIN di0[318]
    DIRECTION INPUT ;
    USE SIGNAL ;
    PORT
      LAYER M5 ;
        RECT  18.144 0 18.168 0.192 ;
    END
  END di0[318]
  PIN di0[319]
    DIRECTION INPUT ;
    USE SIGNAL ;
    PORT
      LAYER M5 ;
        RECT  18.192 0 18.216 0.192 ;
    END
  END di0[319]
  PIN di0[31]
    DIRECTION INPUT ;
    USE SIGNAL ;
    PORT
      LAYER M5 ;
        RECT  4.368 0 4.392 0.192 ;
    END
  END di0[31]
  PIN di0[320]
    DIRECTION INPUT ;
    USE SIGNAL ;
    PORT
      LAYER M5 ;
        RECT  18.24 0 18.264 0.192 ;
    END
  END di0[320]
  PIN di0[321]
    DIRECTION INPUT ;
    USE SIGNAL ;
    PORT
      LAYER M5 ;
        RECT  18.288 0 18.312 0.192 ;
    END
  END di0[321]
  PIN di0[322]
    DIRECTION INPUT ;
    USE SIGNAL ;
    PORT
      LAYER M5 ;
        RECT  18.336 0 18.36 0.192 ;
    END
  END di0[322]
  PIN di0[323]
    DIRECTION INPUT ;
    USE SIGNAL ;
    PORT
      LAYER M5 ;
        RECT  18.384 0 18.408 0.192 ;
    END
  END di0[323]
  PIN di0[324]
    DIRECTION INPUT ;
    USE SIGNAL ;
    PORT
      LAYER M5 ;
        RECT  18.432 0 18.456 0.192 ;
    END
  END di0[324]
  PIN di0[325]
    DIRECTION INPUT ;
    USE SIGNAL ;
    PORT
      LAYER M5 ;
        RECT  18.48 0 18.504 0.192 ;
    END
  END di0[325]
  PIN di0[326]
    DIRECTION INPUT ;
    USE SIGNAL ;
    PORT
      LAYER M5 ;
        RECT  18.528 0 18.552 0.192 ;
    END
  END di0[326]
  PIN di0[327]
    DIRECTION INPUT ;
    USE SIGNAL ;
    PORT
      LAYER M5 ;
        RECT  18.576 0 18.6 0.192 ;
    END
  END di0[327]
  PIN di0[328]
    DIRECTION INPUT ;
    USE SIGNAL ;
    PORT
      LAYER M5 ;
        RECT  18.624 0 18.648 0.192 ;
    END
  END di0[328]
  PIN di0[329]
    DIRECTION INPUT ;
    USE SIGNAL ;
    PORT
      LAYER M5 ;
        RECT  18.672 0 18.696 0.192 ;
    END
  END di0[329]
  PIN di0[32]
    DIRECTION INPUT ;
    USE SIGNAL ;
    PORT
      LAYER M5 ;
        RECT  4.416 0 4.44 0.192 ;
    END
  END di0[32]
  PIN di0[330]
    DIRECTION INPUT ;
    USE SIGNAL ;
    PORT
      LAYER M5 ;
        RECT  18.72 0 18.744 0.192 ;
    END
  END di0[330]
  PIN di0[331]
    DIRECTION INPUT ;
    USE SIGNAL ;
    PORT
      LAYER M5 ;
        RECT  18.768 0 18.792 0.192 ;
    END
  END di0[331]
  PIN di0[332]
    DIRECTION INPUT ;
    USE SIGNAL ;
    PORT
      LAYER M5 ;
        RECT  18.816 0 18.84 0.192 ;
    END
  END di0[332]
  PIN di0[333]
    DIRECTION INPUT ;
    USE SIGNAL ;
    PORT
      LAYER M5 ;
        RECT  18.864 0 18.888 0.192 ;
    END
  END di0[333]
  PIN di0[334]
    DIRECTION INPUT ;
    USE SIGNAL ;
    PORT
      LAYER M5 ;
        RECT  18.912 0 18.936 0.192 ;
    END
  END di0[334]
  PIN di0[335]
    DIRECTION INPUT ;
    USE SIGNAL ;
    PORT
      LAYER M5 ;
        RECT  18.96 0 18.984 0.192 ;
    END
  END di0[335]
  PIN di0[336]
    DIRECTION INPUT ;
    USE SIGNAL ;
    PORT
      LAYER M5 ;
        RECT  19.008 0 19.032 0.192 ;
    END
  END di0[336]
  PIN di0[337]
    DIRECTION INPUT ;
    USE SIGNAL ;
    PORT
      LAYER M5 ;
        RECT  19.056 0 19.08 0.192 ;
    END
  END di0[337]
  PIN di0[338]
    DIRECTION INPUT ;
    USE SIGNAL ;
    PORT
      LAYER M5 ;
        RECT  19.104 0 19.128 0.192 ;
    END
  END di0[338]
  PIN di0[339]
    DIRECTION INPUT ;
    USE SIGNAL ;
    PORT
      LAYER M5 ;
        RECT  19.152 0 19.176 0.192 ;
    END
  END di0[339]
  PIN di0[33]
    DIRECTION INPUT ;
    USE SIGNAL ;
    PORT
      LAYER M5 ;
        RECT  4.464 0 4.488 0.192 ;
    END
  END di0[33]
  PIN di0[340]
    DIRECTION INPUT ;
    USE SIGNAL ;
    PORT
      LAYER M5 ;
        RECT  19.2 0 19.224 0.192 ;
    END
  END di0[340]
  PIN di0[341]
    DIRECTION INPUT ;
    USE SIGNAL ;
    PORT
      LAYER M5 ;
        RECT  19.248 0 19.272 0.192 ;
    END
  END di0[341]
  PIN di0[342]
    DIRECTION INPUT ;
    USE SIGNAL ;
    PORT
      LAYER M5 ;
        RECT  19.296 0 19.32 0.192 ;
    END
  END di0[342]
  PIN di0[343]
    DIRECTION INPUT ;
    USE SIGNAL ;
    PORT
      LAYER M5 ;
        RECT  19.344 0 19.368 0.192 ;
    END
  END di0[343]
  PIN di0[344]
    DIRECTION INPUT ;
    USE SIGNAL ;
    PORT
      LAYER M5 ;
        RECT  19.392 0 19.416 0.192 ;
    END
  END di0[344]
  PIN di0[345]
    DIRECTION INPUT ;
    USE SIGNAL ;
    PORT
      LAYER M5 ;
        RECT  19.44 0 19.464 0.192 ;
    END
  END di0[345]
  PIN di0[346]
    DIRECTION INPUT ;
    USE SIGNAL ;
    PORT
      LAYER M5 ;
        RECT  19.488 0 19.512 0.192 ;
    END
  END di0[346]
  PIN di0[347]
    DIRECTION INPUT ;
    USE SIGNAL ;
    PORT
      LAYER M5 ;
        RECT  19.536 0 19.56 0.192 ;
    END
  END di0[347]
  PIN di0[348]
    DIRECTION INPUT ;
    USE SIGNAL ;
    PORT
      LAYER M5 ;
        RECT  19.584 0 19.608 0.192 ;
    END
  END di0[348]
  PIN di0[349]
    DIRECTION INPUT ;
    USE SIGNAL ;
    PORT
      LAYER M5 ;
        RECT  19.632 0 19.656 0.192 ;
    END
  END di0[349]
  PIN di0[34]
    DIRECTION INPUT ;
    USE SIGNAL ;
    PORT
      LAYER M5 ;
        RECT  4.512 0 4.536 0.192 ;
    END
  END di0[34]
  PIN di0[350]
    DIRECTION INPUT ;
    USE SIGNAL ;
    PORT
      LAYER M5 ;
        RECT  19.68 0 19.704 0.192 ;
    END
  END di0[350]
  PIN di0[351]
    DIRECTION INPUT ;
    USE SIGNAL ;
    PORT
      LAYER M5 ;
        RECT  19.728 0 19.752 0.192 ;
    END
  END di0[351]
  PIN di0[352]
    DIRECTION INPUT ;
    USE SIGNAL ;
    PORT
      LAYER M5 ;
        RECT  19.776 0 19.8 0.192 ;
    END
  END di0[352]
  PIN di0[353]
    DIRECTION INPUT ;
    USE SIGNAL ;
    PORT
      LAYER M5 ;
        RECT  19.824 0 19.848 0.192 ;
    END
  END di0[353]
  PIN di0[354]
    DIRECTION INPUT ;
    USE SIGNAL ;
    PORT
      LAYER M5 ;
        RECT  19.872 0 19.896 0.192 ;
    END
  END di0[354]
  PIN di0[355]
    DIRECTION INPUT ;
    USE SIGNAL ;
    PORT
      LAYER M5 ;
        RECT  19.92 0 19.944 0.192 ;
    END
  END di0[355]
  PIN di0[356]
    DIRECTION INPUT ;
    USE SIGNAL ;
    PORT
      LAYER M5 ;
        RECT  19.968 0 19.992 0.192 ;
    END
  END di0[356]
  PIN di0[357]
    DIRECTION INPUT ;
    USE SIGNAL ;
    PORT
      LAYER M5 ;
        RECT  20.016 0 20.04 0.192 ;
    END
  END di0[357]
  PIN di0[358]
    DIRECTION INPUT ;
    USE SIGNAL ;
    PORT
      LAYER M5 ;
        RECT  20.064 0 20.088 0.192 ;
    END
  END di0[358]
  PIN di0[359]
    DIRECTION INPUT ;
    USE SIGNAL ;
    PORT
      LAYER M5 ;
        RECT  20.112 0 20.136 0.192 ;
    END
  END di0[359]
  PIN di0[35]
    DIRECTION INPUT ;
    USE SIGNAL ;
    PORT
      LAYER M5 ;
        RECT  4.56 0 4.584 0.192 ;
    END
  END di0[35]
  PIN di0[360]
    DIRECTION INPUT ;
    USE SIGNAL ;
    PORT
      LAYER M5 ;
        RECT  20.16 0 20.184 0.192 ;
    END
  END di0[360]
  PIN di0[361]
    DIRECTION INPUT ;
    USE SIGNAL ;
    PORT
      LAYER M5 ;
        RECT  20.208 0 20.232 0.192 ;
    END
  END di0[361]
  PIN di0[362]
    DIRECTION INPUT ;
    USE SIGNAL ;
    PORT
      LAYER M5 ;
        RECT  20.256 0 20.28 0.192 ;
    END
  END di0[362]
  PIN di0[363]
    DIRECTION INPUT ;
    USE SIGNAL ;
    PORT
      LAYER M5 ;
        RECT  20.304 0 20.328 0.192 ;
    END
  END di0[363]
  PIN di0[364]
    DIRECTION INPUT ;
    USE SIGNAL ;
    PORT
      LAYER M5 ;
        RECT  20.352 0 20.376 0.192 ;
    END
  END di0[364]
  PIN di0[365]
    DIRECTION INPUT ;
    USE SIGNAL ;
    PORT
      LAYER M5 ;
        RECT  20.4 0 20.424 0.192 ;
    END
  END di0[365]
  PIN di0[366]
    DIRECTION INPUT ;
    USE SIGNAL ;
    PORT
      LAYER M5 ;
        RECT  20.448 0 20.472 0.192 ;
    END
  END di0[366]
  PIN di0[367]
    DIRECTION INPUT ;
    USE SIGNAL ;
    PORT
      LAYER M5 ;
        RECT  20.496 0 20.52 0.192 ;
    END
  END di0[367]
  PIN di0[368]
    DIRECTION INPUT ;
    USE SIGNAL ;
    PORT
      LAYER M5 ;
        RECT  20.544 0 20.568 0.192 ;
    END
  END di0[368]
  PIN di0[369]
    DIRECTION INPUT ;
    USE SIGNAL ;
    PORT
      LAYER M5 ;
        RECT  20.592 0 20.616 0.192 ;
    END
  END di0[369]
  PIN di0[36]
    DIRECTION INPUT ;
    USE SIGNAL ;
    PORT
      LAYER M5 ;
        RECT  4.608 0 4.632 0.192 ;
    END
  END di0[36]
  PIN di0[370]
    DIRECTION INPUT ;
    USE SIGNAL ;
    PORT
      LAYER M5 ;
        RECT  20.64 0 20.664 0.192 ;
    END
  END di0[370]
  PIN di0[371]
    DIRECTION INPUT ;
    USE SIGNAL ;
    PORT
      LAYER M5 ;
        RECT  20.688 0 20.712 0.192 ;
    END
  END di0[371]
  PIN di0[372]
    DIRECTION INPUT ;
    USE SIGNAL ;
    PORT
      LAYER M5 ;
        RECT  20.736 0 20.76 0.192 ;
    END
  END di0[372]
  PIN di0[373]
    DIRECTION INPUT ;
    USE SIGNAL ;
    PORT
      LAYER M5 ;
        RECT  20.784 0 20.808 0.192 ;
    END
  END di0[373]
  PIN di0[374]
    DIRECTION INPUT ;
    USE SIGNAL ;
    PORT
      LAYER M5 ;
        RECT  20.832 0 20.856 0.192 ;
    END
  END di0[374]
  PIN di0[375]
    DIRECTION INPUT ;
    USE SIGNAL ;
    PORT
      LAYER M5 ;
        RECT  20.88 0 20.904 0.192 ;
    END
  END di0[375]
  PIN di0[376]
    DIRECTION INPUT ;
    USE SIGNAL ;
    PORT
      LAYER M5 ;
        RECT  20.928 0 20.952 0.192 ;
    END
  END di0[376]
  PIN di0[377]
    DIRECTION INPUT ;
    USE SIGNAL ;
    PORT
      LAYER M5 ;
        RECT  20.976 0 21 0.192 ;
    END
  END di0[377]
  PIN di0[378]
    DIRECTION INPUT ;
    USE SIGNAL ;
    PORT
      LAYER M5 ;
        RECT  21.024 0 21.048 0.192 ;
    END
  END di0[378]
  PIN di0[379]
    DIRECTION INPUT ;
    USE SIGNAL ;
    PORT
      LAYER M5 ;
        RECT  21.072 0 21.096 0.192 ;
    END
  END di0[379]
  PIN di0[37]
    DIRECTION INPUT ;
    USE SIGNAL ;
    PORT
      LAYER M5 ;
        RECT  4.656 0 4.68 0.192 ;
    END
  END di0[37]
  PIN di0[380]
    DIRECTION INPUT ;
    USE SIGNAL ;
    PORT
      LAYER M5 ;
        RECT  21.12 0 21.144 0.192 ;
    END
  END di0[380]
  PIN di0[381]
    DIRECTION INPUT ;
    USE SIGNAL ;
    PORT
      LAYER M5 ;
        RECT  21.168 0 21.192 0.192 ;
    END
  END di0[381]
  PIN di0[382]
    DIRECTION INPUT ;
    USE SIGNAL ;
    PORT
      LAYER M5 ;
        RECT  21.216 0 21.24 0.192 ;
    END
  END di0[382]
  PIN di0[383]
    DIRECTION INPUT ;
    USE SIGNAL ;
    PORT
      LAYER M5 ;
        RECT  21.264 0 21.288 0.192 ;
    END
  END di0[383]
  PIN di0[384]
    DIRECTION INPUT ;
    USE SIGNAL ;
    PORT
      LAYER M5 ;
        RECT  21.312 0 21.336 0.192 ;
    END
  END di0[384]
  PIN di0[385]
    DIRECTION INPUT ;
    USE SIGNAL ;
    PORT
      LAYER M5 ;
        RECT  21.36 0 21.384 0.192 ;
    END
  END di0[385]
  PIN di0[386]
    DIRECTION INPUT ;
    USE SIGNAL ;
    PORT
      LAYER M5 ;
        RECT  21.408 0 21.432 0.192 ;
    END
  END di0[386]
  PIN di0[387]
    DIRECTION INPUT ;
    USE SIGNAL ;
    PORT
      LAYER M5 ;
        RECT  21.456 0 21.48 0.192 ;
    END
  END di0[387]
  PIN di0[388]
    DIRECTION INPUT ;
    USE SIGNAL ;
    PORT
      LAYER M5 ;
        RECT  21.504 0 21.528 0.192 ;
    END
  END di0[388]
  PIN di0[389]
    DIRECTION INPUT ;
    USE SIGNAL ;
    PORT
      LAYER M5 ;
        RECT  21.552 0 21.576 0.192 ;
    END
  END di0[389]
  PIN di0[38]
    DIRECTION INPUT ;
    USE SIGNAL ;
    PORT
      LAYER M5 ;
        RECT  4.704 0 4.728 0.192 ;
    END
  END di0[38]
  PIN di0[390]
    DIRECTION INPUT ;
    USE SIGNAL ;
    PORT
      LAYER M5 ;
        RECT  21.6 0 21.624 0.192 ;
    END
  END di0[390]
  PIN di0[391]
    DIRECTION INPUT ;
    USE SIGNAL ;
    PORT
      LAYER M5 ;
        RECT  21.648 0 21.672 0.192 ;
    END
  END di0[391]
  PIN di0[392]
    DIRECTION INPUT ;
    USE SIGNAL ;
    PORT
      LAYER M5 ;
        RECT  21.696 0 21.72 0.192 ;
    END
  END di0[392]
  PIN di0[393]
    DIRECTION INPUT ;
    USE SIGNAL ;
    PORT
      LAYER M5 ;
        RECT  21.744 0 21.768 0.192 ;
    END
  END di0[393]
  PIN di0[394]
    DIRECTION INPUT ;
    USE SIGNAL ;
    PORT
      LAYER M5 ;
        RECT  21.792 0 21.816 0.192 ;
    END
  END di0[394]
  PIN di0[395]
    DIRECTION INPUT ;
    USE SIGNAL ;
    PORT
      LAYER M5 ;
        RECT  21.84 0 21.864 0.192 ;
    END
  END di0[395]
  PIN di0[396]
    DIRECTION INPUT ;
    USE SIGNAL ;
    PORT
      LAYER M5 ;
        RECT  21.888 0 21.912 0.192 ;
    END
  END di0[396]
  PIN di0[397]
    DIRECTION INPUT ;
    USE SIGNAL ;
    PORT
      LAYER M5 ;
        RECT  21.936 0 21.96 0.192 ;
    END
  END di0[397]
  PIN di0[398]
    DIRECTION INPUT ;
    USE SIGNAL ;
    PORT
      LAYER M5 ;
        RECT  21.984 0 22.008 0.192 ;
    END
  END di0[398]
  PIN di0[399]
    DIRECTION INPUT ;
    USE SIGNAL ;
    PORT
      LAYER M5 ;
        RECT  22.032 0 22.056 0.192 ;
    END
  END di0[399]
  PIN di0[39]
    DIRECTION INPUT ;
    USE SIGNAL ;
    PORT
      LAYER M5 ;
        RECT  4.752 0 4.776 0.192 ;
    END
  END di0[39]
  PIN di0[3]
    DIRECTION INPUT ;
    USE SIGNAL ;
    PORT
      LAYER M5 ;
        RECT  3.024 0 3.048 0.192 ;
    END
  END di0[3]
  PIN di0[400]
    DIRECTION INPUT ;
    USE SIGNAL ;
    PORT
      LAYER M5 ;
        RECT  22.08 0 22.104 0.192 ;
    END
  END di0[400]
  PIN di0[401]
    DIRECTION INPUT ;
    USE SIGNAL ;
    PORT
      LAYER M5 ;
        RECT  22.128 0 22.152 0.192 ;
    END
  END di0[401]
  PIN di0[402]
    DIRECTION INPUT ;
    USE SIGNAL ;
    PORT
      LAYER M5 ;
        RECT  22.176 0 22.2 0.192 ;
    END
  END di0[402]
  PIN di0[403]
    DIRECTION INPUT ;
    USE SIGNAL ;
    PORT
      LAYER M5 ;
        RECT  22.224 0 22.248 0.192 ;
    END
  END di0[403]
  PIN di0[404]
    DIRECTION INPUT ;
    USE SIGNAL ;
    PORT
      LAYER M5 ;
        RECT  22.272 0 22.296 0.192 ;
    END
  END di0[404]
  PIN di0[405]
    DIRECTION INPUT ;
    USE SIGNAL ;
    PORT
      LAYER M5 ;
        RECT  22.32 0 22.344 0.192 ;
    END
  END di0[405]
  PIN di0[406]
    DIRECTION INPUT ;
    USE SIGNAL ;
    PORT
      LAYER M5 ;
        RECT  22.368 0 22.392 0.192 ;
    END
  END di0[406]
  PIN di0[407]
    DIRECTION INPUT ;
    USE SIGNAL ;
    PORT
      LAYER M5 ;
        RECT  22.416 0 22.44 0.192 ;
    END
  END di0[407]
  PIN di0[408]
    DIRECTION INPUT ;
    USE SIGNAL ;
    PORT
      LAYER M5 ;
        RECT  22.464 0 22.488 0.192 ;
    END
  END di0[408]
  PIN di0[409]
    DIRECTION INPUT ;
    USE SIGNAL ;
    PORT
      LAYER M5 ;
        RECT  22.512 0 22.536 0.192 ;
    END
  END di0[409]
  PIN di0[40]
    DIRECTION INPUT ;
    USE SIGNAL ;
    PORT
      LAYER M5 ;
        RECT  4.8 0 4.824 0.192 ;
    END
  END di0[40]
  PIN di0[410]
    DIRECTION INPUT ;
    USE SIGNAL ;
    PORT
      LAYER M5 ;
        RECT  22.56 0 22.584 0.192 ;
    END
  END di0[410]
  PIN di0[411]
    DIRECTION INPUT ;
    USE SIGNAL ;
    PORT
      LAYER M5 ;
        RECT  22.608 0 22.632 0.192 ;
    END
  END di0[411]
  PIN di0[412]
    DIRECTION INPUT ;
    USE SIGNAL ;
    PORT
      LAYER M5 ;
        RECT  22.656 0 22.68 0.192 ;
    END
  END di0[412]
  PIN di0[413]
    DIRECTION INPUT ;
    USE SIGNAL ;
    PORT
      LAYER M5 ;
        RECT  22.704 0 22.728 0.192 ;
    END
  END di0[413]
  PIN di0[414]
    DIRECTION INPUT ;
    USE SIGNAL ;
    PORT
      LAYER M5 ;
        RECT  22.752 0 22.776 0.192 ;
    END
  END di0[414]
  PIN di0[415]
    DIRECTION INPUT ;
    USE SIGNAL ;
    PORT
      LAYER M5 ;
        RECT  22.8 0 22.824 0.192 ;
    END
  END di0[415]
  PIN di0[416]
    DIRECTION INPUT ;
    USE SIGNAL ;
    PORT
      LAYER M5 ;
        RECT  22.848 0 22.872 0.192 ;
    END
  END di0[416]
  PIN di0[417]
    DIRECTION INPUT ;
    USE SIGNAL ;
    PORT
      LAYER M5 ;
        RECT  22.896 0 22.92 0.192 ;
    END
  END di0[417]
  PIN di0[418]
    DIRECTION INPUT ;
    USE SIGNAL ;
    PORT
      LAYER M5 ;
        RECT  22.944 0 22.968 0.192 ;
    END
  END di0[418]
  PIN di0[419]
    DIRECTION INPUT ;
    USE SIGNAL ;
    PORT
      LAYER M5 ;
        RECT  22.992 0 23.016 0.192 ;
    END
  END di0[419]
  PIN di0[41]
    DIRECTION INPUT ;
    USE SIGNAL ;
    PORT
      LAYER M5 ;
        RECT  4.848 0 4.872 0.192 ;
    END
  END di0[41]
  PIN di0[420]
    DIRECTION INPUT ;
    USE SIGNAL ;
    PORT
      LAYER M5 ;
        RECT  23.04 0 23.064 0.192 ;
    END
  END di0[420]
  PIN di0[421]
    DIRECTION INPUT ;
    USE SIGNAL ;
    PORT
      LAYER M5 ;
        RECT  23.088 0 23.112 0.192 ;
    END
  END di0[421]
  PIN di0[422]
    DIRECTION INPUT ;
    USE SIGNAL ;
    PORT
      LAYER M5 ;
        RECT  23.136 0 23.16 0.192 ;
    END
  END di0[422]
  PIN di0[423]
    DIRECTION INPUT ;
    USE SIGNAL ;
    PORT
      LAYER M5 ;
        RECT  23.184 0 23.208 0.192 ;
    END
  END di0[423]
  PIN di0[424]
    DIRECTION INPUT ;
    USE SIGNAL ;
    PORT
      LAYER M5 ;
        RECT  23.232 0 23.256 0.192 ;
    END
  END di0[424]
  PIN di0[425]
    DIRECTION INPUT ;
    USE SIGNAL ;
    PORT
      LAYER M5 ;
        RECT  23.28 0 23.304 0.192 ;
    END
  END di0[425]
  PIN di0[426]
    DIRECTION INPUT ;
    USE SIGNAL ;
    PORT
      LAYER M5 ;
        RECT  23.328 0 23.352 0.192 ;
    END
  END di0[426]
  PIN di0[427]
    DIRECTION INPUT ;
    USE SIGNAL ;
    PORT
      LAYER M5 ;
        RECT  23.376 0 23.4 0.192 ;
    END
  END di0[427]
  PIN di0[428]
    DIRECTION INPUT ;
    USE SIGNAL ;
    PORT
      LAYER M5 ;
        RECT  23.424 0 23.448 0.192 ;
    END
  END di0[428]
  PIN di0[429]
    DIRECTION INPUT ;
    USE SIGNAL ;
    PORT
      LAYER M5 ;
        RECT  23.472 0 23.496 0.192 ;
    END
  END di0[429]
  PIN di0[42]
    DIRECTION INPUT ;
    USE SIGNAL ;
    PORT
      LAYER M5 ;
        RECT  4.896 0 4.92 0.192 ;
    END
  END di0[42]
  PIN di0[430]
    DIRECTION INPUT ;
    USE SIGNAL ;
    PORT
      LAYER M5 ;
        RECT  23.52 0 23.544 0.192 ;
    END
  END di0[430]
  PIN di0[431]
    DIRECTION INPUT ;
    USE SIGNAL ;
    PORT
      LAYER M5 ;
        RECT  23.568 0 23.592 0.192 ;
    END
  END di0[431]
  PIN di0[432]
    DIRECTION INPUT ;
    USE SIGNAL ;
    PORT
      LAYER M5 ;
        RECT  23.616 0 23.64 0.192 ;
    END
  END di0[432]
  PIN di0[433]
    DIRECTION INPUT ;
    USE SIGNAL ;
    PORT
      LAYER M5 ;
        RECT  23.664 0 23.688 0.192 ;
    END
  END di0[433]
  PIN di0[434]
    DIRECTION INPUT ;
    USE SIGNAL ;
    PORT
      LAYER M5 ;
        RECT  23.712 0 23.736 0.192 ;
    END
  END di0[434]
  PIN di0[435]
    DIRECTION INPUT ;
    USE SIGNAL ;
    PORT
      LAYER M5 ;
        RECT  23.76 0 23.784 0.192 ;
    END
  END di0[435]
  PIN di0[436]
    DIRECTION INPUT ;
    USE SIGNAL ;
    PORT
      LAYER M5 ;
        RECT  23.808 0 23.832 0.192 ;
    END
  END di0[436]
  PIN di0[437]
    DIRECTION INPUT ;
    USE SIGNAL ;
    PORT
      LAYER M5 ;
        RECT  23.856 0 23.88 0.192 ;
    END
  END di0[437]
  PIN di0[438]
    DIRECTION INPUT ;
    USE SIGNAL ;
    PORT
      LAYER M5 ;
        RECT  23.904 0 23.928 0.192 ;
    END
  END di0[438]
  PIN di0[439]
    DIRECTION INPUT ;
    USE SIGNAL ;
    PORT
      LAYER M5 ;
        RECT  23.952 0 23.976 0.192 ;
    END
  END di0[439]
  PIN di0[43]
    DIRECTION INPUT ;
    USE SIGNAL ;
    PORT
      LAYER M5 ;
        RECT  4.944 0 4.968 0.192 ;
    END
  END di0[43]
  PIN di0[440]
    DIRECTION INPUT ;
    USE SIGNAL ;
    PORT
      LAYER M5 ;
        RECT  24 0 24.024 0.192 ;
    END
  END di0[440]
  PIN di0[441]
    DIRECTION INPUT ;
    USE SIGNAL ;
    PORT
      LAYER M5 ;
        RECT  24.048 0 24.072 0.192 ;
    END
  END di0[441]
  PIN di0[442]
    DIRECTION INPUT ;
    USE SIGNAL ;
    PORT
      LAYER M5 ;
        RECT  24.096 0 24.12 0.192 ;
    END
  END di0[442]
  PIN di0[443]
    DIRECTION INPUT ;
    USE SIGNAL ;
    PORT
      LAYER M5 ;
        RECT  24.144 0 24.168 0.192 ;
    END
  END di0[443]
  PIN di0[444]
    DIRECTION INPUT ;
    USE SIGNAL ;
    PORT
      LAYER M5 ;
        RECT  24.192 0 24.216 0.192 ;
    END
  END di0[444]
  PIN di0[445]
    DIRECTION INPUT ;
    USE SIGNAL ;
    PORT
      LAYER M5 ;
        RECT  24.24 0 24.264 0.192 ;
    END
  END di0[445]
  PIN di0[446]
    DIRECTION INPUT ;
    USE SIGNAL ;
    PORT
      LAYER M5 ;
        RECT  24.288 0 24.312 0.192 ;
    END
  END di0[446]
  PIN di0[447]
    DIRECTION INPUT ;
    USE SIGNAL ;
    PORT
      LAYER M5 ;
        RECT  24.336 0 24.36 0.192 ;
    END
  END di0[447]
  PIN di0[448]
    DIRECTION INPUT ;
    USE SIGNAL ;
    PORT
      LAYER M5 ;
        RECT  24.384 0 24.408 0.192 ;
    END
  END di0[448]
  PIN di0[449]
    DIRECTION INPUT ;
    USE SIGNAL ;
    PORT
      LAYER M5 ;
        RECT  24.432 0 24.456 0.192 ;
    END
  END di0[449]
  PIN di0[44]
    DIRECTION INPUT ;
    USE SIGNAL ;
    PORT
      LAYER M5 ;
        RECT  4.992 0 5.016 0.192 ;
    END
  END di0[44]
  PIN di0[450]
    DIRECTION INPUT ;
    USE SIGNAL ;
    PORT
      LAYER M5 ;
        RECT  24.48 0 24.504 0.192 ;
    END
  END di0[450]
  PIN di0[451]
    DIRECTION INPUT ;
    USE SIGNAL ;
    PORT
      LAYER M5 ;
        RECT  24.528 0 24.552 0.192 ;
    END
  END di0[451]
  PIN di0[452]
    DIRECTION INPUT ;
    USE SIGNAL ;
    PORT
      LAYER M5 ;
        RECT  24.576 0 24.6 0.192 ;
    END
  END di0[452]
  PIN di0[453]
    DIRECTION INPUT ;
    USE SIGNAL ;
    PORT
      LAYER M5 ;
        RECT  24.624 0 24.648 0.192 ;
    END
  END di0[453]
  PIN di0[454]
    DIRECTION INPUT ;
    USE SIGNAL ;
    PORT
      LAYER M5 ;
        RECT  24.672 0 24.696 0.192 ;
    END
  END di0[454]
  PIN di0[455]
    DIRECTION INPUT ;
    USE SIGNAL ;
    PORT
      LAYER M5 ;
        RECT  24.72 0 24.744 0.192 ;
    END
  END di0[455]
  PIN di0[456]
    DIRECTION INPUT ;
    USE SIGNAL ;
    PORT
      LAYER M5 ;
        RECT  24.768 0 24.792 0.192 ;
    END
  END di0[456]
  PIN di0[457]
    DIRECTION INPUT ;
    USE SIGNAL ;
    PORT
      LAYER M5 ;
        RECT  24.816 0 24.84 0.192 ;
    END
  END di0[457]
  PIN di0[458]
    DIRECTION INPUT ;
    USE SIGNAL ;
    PORT
      LAYER M5 ;
        RECT  24.864 0 24.888 0.192 ;
    END
  END di0[458]
  PIN di0[459]
    DIRECTION INPUT ;
    USE SIGNAL ;
    PORT
      LAYER M5 ;
        RECT  24.912 0 24.936 0.192 ;
    END
  END di0[459]
  PIN di0[45]
    DIRECTION INPUT ;
    USE SIGNAL ;
    PORT
      LAYER M5 ;
        RECT  5.04 0 5.064 0.192 ;
    END
  END di0[45]
  PIN di0[460]
    DIRECTION INPUT ;
    USE SIGNAL ;
    PORT
      LAYER M5 ;
        RECT  24.96 0 24.984 0.192 ;
    END
  END di0[460]
  PIN di0[461]
    DIRECTION INPUT ;
    USE SIGNAL ;
    PORT
      LAYER M5 ;
        RECT  25.008 0 25.032 0.192 ;
    END
  END di0[461]
  PIN di0[462]
    DIRECTION INPUT ;
    USE SIGNAL ;
    PORT
      LAYER M5 ;
        RECT  25.056 0 25.08 0.192 ;
    END
  END di0[462]
  PIN di0[463]
    DIRECTION INPUT ;
    USE SIGNAL ;
    PORT
      LAYER M5 ;
        RECT  25.104 0 25.128 0.192 ;
    END
  END di0[463]
  PIN di0[464]
    DIRECTION INPUT ;
    USE SIGNAL ;
    PORT
      LAYER M5 ;
        RECT  25.152 0 25.176 0.192 ;
    END
  END di0[464]
  PIN di0[465]
    DIRECTION INPUT ;
    USE SIGNAL ;
    PORT
      LAYER M5 ;
        RECT  25.2 0 25.224 0.192 ;
    END
  END di0[465]
  PIN di0[466]
    DIRECTION INPUT ;
    USE SIGNAL ;
    PORT
      LAYER M5 ;
        RECT  25.248 0 25.272 0.192 ;
    END
  END di0[466]
  PIN di0[467]
    DIRECTION INPUT ;
    USE SIGNAL ;
    PORT
      LAYER M5 ;
        RECT  25.296 0 25.32 0.192 ;
    END
  END di0[467]
  PIN di0[468]
    DIRECTION INPUT ;
    USE SIGNAL ;
    PORT
      LAYER M5 ;
        RECT  25.344 0 25.368 0.192 ;
    END
  END di0[468]
  PIN di0[469]
    DIRECTION INPUT ;
    USE SIGNAL ;
    PORT
      LAYER M5 ;
        RECT  25.392 0 25.416 0.192 ;
    END
  END di0[469]
  PIN di0[46]
    DIRECTION INPUT ;
    USE SIGNAL ;
    PORT
      LAYER M5 ;
        RECT  5.088 0 5.112 0.192 ;
    END
  END di0[46]
  PIN di0[470]
    DIRECTION INPUT ;
    USE SIGNAL ;
    PORT
      LAYER M5 ;
        RECT  25.44 0 25.464 0.192 ;
    END
  END di0[470]
  PIN di0[471]
    DIRECTION INPUT ;
    USE SIGNAL ;
    PORT
      LAYER M5 ;
        RECT  25.488 0 25.512 0.192 ;
    END
  END di0[471]
  PIN di0[472]
    DIRECTION INPUT ;
    USE SIGNAL ;
    PORT
      LAYER M5 ;
        RECT  25.536 0 25.56 0.192 ;
    END
  END di0[472]
  PIN di0[473]
    DIRECTION INPUT ;
    USE SIGNAL ;
    PORT
      LAYER M5 ;
        RECT  25.584 0 25.608 0.192 ;
    END
  END di0[473]
  PIN di0[474]
    DIRECTION INPUT ;
    USE SIGNAL ;
    PORT
      LAYER M5 ;
        RECT  25.632 0 25.656 0.192 ;
    END
  END di0[474]
  PIN di0[475]
    DIRECTION INPUT ;
    USE SIGNAL ;
    PORT
      LAYER M5 ;
        RECT  25.68 0 25.704 0.192 ;
    END
  END di0[475]
  PIN di0[476]
    DIRECTION INPUT ;
    USE SIGNAL ;
    PORT
      LAYER M5 ;
        RECT  25.728 0 25.752 0.192 ;
    END
  END di0[476]
  PIN di0[477]
    DIRECTION INPUT ;
    USE SIGNAL ;
    PORT
      LAYER M5 ;
        RECT  25.776 0 25.8 0.192 ;
    END
  END di0[477]
  PIN di0[478]
    DIRECTION INPUT ;
    USE SIGNAL ;
    PORT
      LAYER M5 ;
        RECT  25.824 0 25.848 0.192 ;
    END
  END di0[478]
  PIN di0[479]
    DIRECTION INPUT ;
    USE SIGNAL ;
    PORT
      LAYER M5 ;
        RECT  25.872 0 25.896 0.192 ;
    END
  END di0[479]
  PIN di0[47]
    DIRECTION INPUT ;
    USE SIGNAL ;
    PORT
      LAYER M5 ;
        RECT  5.136 0 5.16 0.192 ;
    END
  END di0[47]
  PIN di0[480]
    DIRECTION INPUT ;
    USE SIGNAL ;
    PORT
      LAYER M5 ;
        RECT  25.92 0 25.944 0.192 ;
    END
  END di0[480]
  PIN di0[481]
    DIRECTION INPUT ;
    USE SIGNAL ;
    PORT
      LAYER M5 ;
        RECT  25.968 0 25.992 0.192 ;
    END
  END di0[481]
  PIN di0[482]
    DIRECTION INPUT ;
    USE SIGNAL ;
    PORT
      LAYER M5 ;
        RECT  26.016 0 26.04 0.192 ;
    END
  END di0[482]
  PIN di0[483]
    DIRECTION INPUT ;
    USE SIGNAL ;
    PORT
      LAYER M5 ;
        RECT  26.064 0 26.088 0.192 ;
    END
  END di0[483]
  PIN di0[484]
    DIRECTION INPUT ;
    USE SIGNAL ;
    PORT
      LAYER M5 ;
        RECT  26.112 0 26.136 0.192 ;
    END
  END di0[484]
  PIN di0[485]
    DIRECTION INPUT ;
    USE SIGNAL ;
    PORT
      LAYER M5 ;
        RECT  26.16 0 26.184 0.192 ;
    END
  END di0[485]
  PIN di0[486]
    DIRECTION INPUT ;
    USE SIGNAL ;
    PORT
      LAYER M5 ;
        RECT  26.208 0 26.232 0.192 ;
    END
  END di0[486]
  PIN di0[487]
    DIRECTION INPUT ;
    USE SIGNAL ;
    PORT
      LAYER M5 ;
        RECT  26.256 0 26.28 0.192 ;
    END
  END di0[487]
  PIN di0[488]
    DIRECTION INPUT ;
    USE SIGNAL ;
    PORT
      LAYER M5 ;
        RECT  26.304 0 26.328 0.192 ;
    END
  END di0[488]
  PIN di0[489]
    DIRECTION INPUT ;
    USE SIGNAL ;
    PORT
      LAYER M5 ;
        RECT  26.352 0 26.376 0.192 ;
    END
  END di0[489]
  PIN di0[48]
    DIRECTION INPUT ;
    USE SIGNAL ;
    PORT
      LAYER M5 ;
        RECT  5.184 0 5.208 0.192 ;
    END
  END di0[48]
  PIN di0[490]
    DIRECTION INPUT ;
    USE SIGNAL ;
    PORT
      LAYER M5 ;
        RECT  26.4 0 26.424 0.192 ;
    END
  END di0[490]
  PIN di0[491]
    DIRECTION INPUT ;
    USE SIGNAL ;
    PORT
      LAYER M5 ;
        RECT  26.448 0 26.472 0.192 ;
    END
  END di0[491]
  PIN di0[492]
    DIRECTION INPUT ;
    USE SIGNAL ;
    PORT
      LAYER M5 ;
        RECT  26.496 0 26.52 0.192 ;
    END
  END di0[492]
  PIN di0[493]
    DIRECTION INPUT ;
    USE SIGNAL ;
    PORT
      LAYER M5 ;
        RECT  26.544 0 26.568 0.192 ;
    END
  END di0[493]
  PIN di0[494]
    DIRECTION INPUT ;
    USE SIGNAL ;
    PORT
      LAYER M5 ;
        RECT  26.592 0 26.616 0.192 ;
    END
  END di0[494]
  PIN di0[495]
    DIRECTION INPUT ;
    USE SIGNAL ;
    PORT
      LAYER M5 ;
        RECT  26.64 0 26.664 0.192 ;
    END
  END di0[495]
  PIN di0[496]
    DIRECTION INPUT ;
    USE SIGNAL ;
    PORT
      LAYER M5 ;
        RECT  26.688 0 26.712 0.192 ;
    END
  END di0[496]
  PIN di0[497]
    DIRECTION INPUT ;
    USE SIGNAL ;
    PORT
      LAYER M5 ;
        RECT  26.736 0 26.76 0.192 ;
    END
  END di0[497]
  PIN di0[498]
    DIRECTION INPUT ;
    USE SIGNAL ;
    PORT
      LAYER M5 ;
        RECT  26.784 0 26.808 0.192 ;
    END
  END di0[498]
  PIN di0[499]
    DIRECTION INPUT ;
    USE SIGNAL ;
    PORT
      LAYER M5 ;
        RECT  26.832 0 26.856 0.192 ;
    END
  END di0[499]
  PIN di0[49]
    DIRECTION INPUT ;
    USE SIGNAL ;
    PORT
      LAYER M5 ;
        RECT  5.232 0 5.256 0.192 ;
    END
  END di0[49]
  PIN di0[4]
    DIRECTION INPUT ;
    USE SIGNAL ;
    PORT
      LAYER M5 ;
        RECT  3.072 0 3.096 0.192 ;
    END
  END di0[4]
  PIN di0[500]
    DIRECTION INPUT ;
    USE SIGNAL ;
    PORT
      LAYER M5 ;
        RECT  26.88 0 26.904 0.192 ;
    END
  END di0[500]
  PIN di0[501]
    DIRECTION INPUT ;
    USE SIGNAL ;
    PORT
      LAYER M5 ;
        RECT  26.928 0 26.952 0.192 ;
    END
  END di0[501]
  PIN di0[502]
    DIRECTION INPUT ;
    USE SIGNAL ;
    PORT
      LAYER M5 ;
        RECT  26.976 0 27 0.192 ;
    END
  END di0[502]
  PIN di0[503]
    DIRECTION INPUT ;
    USE SIGNAL ;
    PORT
      LAYER M5 ;
        RECT  27.024 0 27.048 0.192 ;
    END
  END di0[503]
  PIN di0[504]
    DIRECTION INPUT ;
    USE SIGNAL ;
    PORT
      LAYER M5 ;
        RECT  27.072 0 27.096 0.192 ;
    END
  END di0[504]
  PIN di0[505]
    DIRECTION INPUT ;
    USE SIGNAL ;
    PORT
      LAYER M5 ;
        RECT  27.12 0 27.144 0.192 ;
    END
  END di0[505]
  PIN di0[506]
    DIRECTION INPUT ;
    USE SIGNAL ;
    PORT
      LAYER M5 ;
        RECT  27.168 0 27.192 0.192 ;
    END
  END di0[506]
  PIN di0[507]
    DIRECTION INPUT ;
    USE SIGNAL ;
    PORT
      LAYER M5 ;
        RECT  27.216 0 27.24 0.192 ;
    END
  END di0[507]
  PIN di0[508]
    DIRECTION INPUT ;
    USE SIGNAL ;
    PORT
      LAYER M5 ;
        RECT  27.264 0 27.288 0.192 ;
    END
  END di0[508]
  PIN di0[509]
    DIRECTION INPUT ;
    USE SIGNAL ;
    PORT
      LAYER M5 ;
        RECT  27.312 0 27.336 0.192 ;
    END
  END di0[509]
  PIN di0[50]
    DIRECTION INPUT ;
    USE SIGNAL ;
    PORT
      LAYER M5 ;
        RECT  5.28 0 5.304 0.192 ;
    END
  END di0[50]
  PIN di0[510]
    DIRECTION INPUT ;
    USE SIGNAL ;
    PORT
      LAYER M5 ;
        RECT  27.36 0 27.384 0.192 ;
    END
  END di0[510]
  PIN di0[511]
    DIRECTION INPUT ;
    USE SIGNAL ;
    PORT
      LAYER M5 ;
        RECT  27.408 0 27.432 0.192 ;
    END
  END di0[511]
  PIN di0[512]
    DIRECTION INPUT ;
    USE SIGNAL ;
    PORT
      LAYER M5 ;
        RECT  27.456 0 27.48 0.192 ;
    END
  END di0[512]
  PIN di0[513]
    DIRECTION INPUT ;
    USE SIGNAL ;
    PORT
      LAYER M5 ;
        RECT  27.504 0 27.528 0.192 ;
    END
  END di0[513]
  PIN di0[51]
    DIRECTION INPUT ;
    USE SIGNAL ;
    PORT
      LAYER M5 ;
        RECT  5.328 0 5.352 0.192 ;
    END
  END di0[51]
  PIN di0[52]
    DIRECTION INPUT ;
    USE SIGNAL ;
    PORT
      LAYER M5 ;
        RECT  5.376 0 5.4 0.192 ;
    END
  END di0[52]
  PIN di0[53]
    DIRECTION INPUT ;
    USE SIGNAL ;
    PORT
      LAYER M5 ;
        RECT  5.424 0 5.448 0.192 ;
    END
  END di0[53]
  PIN di0[54]
    DIRECTION INPUT ;
    USE SIGNAL ;
    PORT
      LAYER M5 ;
        RECT  5.472 0 5.496 0.192 ;
    END
  END di0[54]
  PIN di0[55]
    DIRECTION INPUT ;
    USE SIGNAL ;
    PORT
      LAYER M5 ;
        RECT  5.52 0 5.544 0.192 ;
    END
  END di0[55]
  PIN di0[56]
    DIRECTION INPUT ;
    USE SIGNAL ;
    PORT
      LAYER M5 ;
        RECT  5.568 0 5.592 0.192 ;
    END
  END di0[56]
  PIN di0[57]
    DIRECTION INPUT ;
    USE SIGNAL ;
    PORT
      LAYER M5 ;
        RECT  5.616 0 5.64 0.192 ;
    END
  END di0[57]
  PIN di0[58]
    DIRECTION INPUT ;
    USE SIGNAL ;
    PORT
      LAYER M5 ;
        RECT  5.664 0 5.688 0.192 ;
    END
  END di0[58]
  PIN di0[59]
    DIRECTION INPUT ;
    USE SIGNAL ;
    PORT
      LAYER M5 ;
        RECT  5.712 0 5.736 0.192 ;
    END
  END di0[59]
  PIN di0[5]
    DIRECTION INPUT ;
    USE SIGNAL ;
    PORT
      LAYER M5 ;
        RECT  3.12 0 3.144 0.192 ;
    END
  END di0[5]
  PIN di0[60]
    DIRECTION INPUT ;
    USE SIGNAL ;
    PORT
      LAYER M5 ;
        RECT  5.76 0 5.784 0.192 ;
    END
  END di0[60]
  PIN di0[61]
    DIRECTION INPUT ;
    USE SIGNAL ;
    PORT
      LAYER M5 ;
        RECT  5.808 0 5.832 0.192 ;
    END
  END di0[61]
  PIN di0[62]
    DIRECTION INPUT ;
    USE SIGNAL ;
    PORT
      LAYER M5 ;
        RECT  5.856 0 5.88 0.192 ;
    END
  END di0[62]
  PIN di0[63]
    DIRECTION INPUT ;
    USE SIGNAL ;
    PORT
      LAYER M5 ;
        RECT  5.904 0 5.928 0.192 ;
    END
  END di0[63]
  PIN di0[64]
    DIRECTION INPUT ;
    USE SIGNAL ;
    PORT
      LAYER M5 ;
        RECT  5.952 0 5.976 0.192 ;
    END
  END di0[64]
  PIN di0[65]
    DIRECTION INPUT ;
    USE SIGNAL ;
    PORT
      LAYER M5 ;
        RECT  6 0 6.024 0.192 ;
    END
  END di0[65]
  PIN di0[66]
    DIRECTION INPUT ;
    USE SIGNAL ;
    PORT
      LAYER M5 ;
        RECT  6.048 0 6.072 0.192 ;
    END
  END di0[66]
  PIN di0[67]
    DIRECTION INPUT ;
    USE SIGNAL ;
    PORT
      LAYER M5 ;
        RECT  6.096 0 6.12 0.192 ;
    END
  END di0[67]
  PIN di0[68]
    DIRECTION INPUT ;
    USE SIGNAL ;
    PORT
      LAYER M5 ;
        RECT  6.144 0 6.168 0.192 ;
    END
  END di0[68]
  PIN di0[69]
    DIRECTION INPUT ;
    USE SIGNAL ;
    PORT
      LAYER M5 ;
        RECT  6.192 0 6.216 0.192 ;
    END
  END di0[69]
  PIN di0[6]
    DIRECTION INPUT ;
    USE SIGNAL ;
    PORT
      LAYER M5 ;
        RECT  3.168 0 3.192 0.192 ;
    END
  END di0[6]
  PIN di0[70]
    DIRECTION INPUT ;
    USE SIGNAL ;
    PORT
      LAYER M5 ;
        RECT  6.24 0 6.264 0.192 ;
    END
  END di0[70]
  PIN di0[71]
    DIRECTION INPUT ;
    USE SIGNAL ;
    PORT
      LAYER M5 ;
        RECT  6.288 0 6.312 0.192 ;
    END
  END di0[71]
  PIN di0[72]
    DIRECTION INPUT ;
    USE SIGNAL ;
    PORT
      LAYER M5 ;
        RECT  6.336 0 6.36 0.192 ;
    END
  END di0[72]
  PIN di0[73]
    DIRECTION INPUT ;
    USE SIGNAL ;
    PORT
      LAYER M5 ;
        RECT  6.384 0 6.408 0.192 ;
    END
  END di0[73]
  PIN di0[74]
    DIRECTION INPUT ;
    USE SIGNAL ;
    PORT
      LAYER M5 ;
        RECT  6.432 0 6.456 0.192 ;
    END
  END di0[74]
  PIN di0[75]
    DIRECTION INPUT ;
    USE SIGNAL ;
    PORT
      LAYER M5 ;
        RECT  6.48 0 6.504 0.192 ;
    END
  END di0[75]
  PIN di0[76]
    DIRECTION INPUT ;
    USE SIGNAL ;
    PORT
      LAYER M5 ;
        RECT  6.528 0 6.552 0.192 ;
    END
  END di0[76]
  PIN di0[77]
    DIRECTION INPUT ;
    USE SIGNAL ;
    PORT
      LAYER M5 ;
        RECT  6.576 0 6.6 0.192 ;
    END
  END di0[77]
  PIN di0[78]
    DIRECTION INPUT ;
    USE SIGNAL ;
    PORT
      LAYER M5 ;
        RECT  6.624 0 6.648 0.192 ;
    END
  END di0[78]
  PIN di0[79]
    DIRECTION INPUT ;
    USE SIGNAL ;
    PORT
      LAYER M5 ;
        RECT  6.672 0 6.696 0.192 ;
    END
  END di0[79]
  PIN di0[7]
    DIRECTION INPUT ;
    USE SIGNAL ;
    PORT
      LAYER M5 ;
        RECT  3.216 0 3.24 0.192 ;
    END
  END di0[7]
  PIN di0[80]
    DIRECTION INPUT ;
    USE SIGNAL ;
    PORT
      LAYER M5 ;
        RECT  6.72 0 6.744 0.192 ;
    END
  END di0[80]
  PIN di0[81]
    DIRECTION INPUT ;
    USE SIGNAL ;
    PORT
      LAYER M5 ;
        RECT  6.768 0 6.792 0.192 ;
    END
  END di0[81]
  PIN di0[82]
    DIRECTION INPUT ;
    USE SIGNAL ;
    PORT
      LAYER M5 ;
        RECT  6.816 0 6.84 0.192 ;
    END
  END di0[82]
  PIN di0[83]
    DIRECTION INPUT ;
    USE SIGNAL ;
    PORT
      LAYER M5 ;
        RECT  6.864 0 6.888 0.192 ;
    END
  END di0[83]
  PIN di0[84]
    DIRECTION INPUT ;
    USE SIGNAL ;
    PORT
      LAYER M5 ;
        RECT  6.912 0 6.936 0.192 ;
    END
  END di0[84]
  PIN di0[85]
    DIRECTION INPUT ;
    USE SIGNAL ;
    PORT
      LAYER M5 ;
        RECT  6.96 0 6.984 0.192 ;
    END
  END di0[85]
  PIN di0[86]
    DIRECTION INPUT ;
    USE SIGNAL ;
    PORT
      LAYER M5 ;
        RECT  7.008 0 7.032 0.192 ;
    END
  END di0[86]
  PIN di0[87]
    DIRECTION INPUT ;
    USE SIGNAL ;
    PORT
      LAYER M5 ;
        RECT  7.056 0 7.08 0.192 ;
    END
  END di0[87]
  PIN di0[88]
    DIRECTION INPUT ;
    USE SIGNAL ;
    PORT
      LAYER M5 ;
        RECT  7.104 0 7.128 0.192 ;
    END
  END di0[88]
  PIN di0[89]
    DIRECTION INPUT ;
    USE SIGNAL ;
    PORT
      LAYER M5 ;
        RECT  7.152 0 7.176 0.192 ;
    END
  END di0[89]
  PIN di0[8]
    DIRECTION INPUT ;
    USE SIGNAL ;
    PORT
      LAYER M5 ;
        RECT  3.264 0 3.288 0.192 ;
    END
  END di0[8]
  PIN di0[90]
    DIRECTION INPUT ;
    USE SIGNAL ;
    PORT
      LAYER M5 ;
        RECT  7.2 0 7.224 0.192 ;
    END
  END di0[90]
  PIN di0[91]
    DIRECTION INPUT ;
    USE SIGNAL ;
    PORT
      LAYER M5 ;
        RECT  7.248 0 7.272 0.192 ;
    END
  END di0[91]
  PIN di0[92]
    DIRECTION INPUT ;
    USE SIGNAL ;
    PORT
      LAYER M5 ;
        RECT  7.296 0 7.32 0.192 ;
    END
  END di0[92]
  PIN di0[93]
    DIRECTION INPUT ;
    USE SIGNAL ;
    PORT
      LAYER M5 ;
        RECT  7.344 0 7.368 0.192 ;
    END
  END di0[93]
  PIN di0[94]
    DIRECTION INPUT ;
    USE SIGNAL ;
    PORT
      LAYER M5 ;
        RECT  7.392 0 7.416 0.192 ;
    END
  END di0[94]
  PIN di0[95]
    DIRECTION INPUT ;
    USE SIGNAL ;
    PORT
      LAYER M5 ;
        RECT  7.44 0 7.464 0.192 ;
    END
  END di0[95]
  PIN di0[96]
    DIRECTION INPUT ;
    USE SIGNAL ;
    PORT
      LAYER M5 ;
        RECT  7.488 0 7.512 0.192 ;
    END
  END di0[96]
  PIN di0[97]
    DIRECTION INPUT ;
    USE SIGNAL ;
    PORT
      LAYER M5 ;
        RECT  7.536 0 7.56 0.192 ;
    END
  END di0[97]
  PIN di0[98]
    DIRECTION INPUT ;
    USE SIGNAL ;
    PORT
      LAYER M5 ;
        RECT  7.584 0 7.608 0.192 ;
    END
  END di0[98]
  PIN di0[99]
    DIRECTION INPUT ;
    USE SIGNAL ;
    PORT
      LAYER M5 ;
        RECT  7.632 0 7.656 0.192 ;
    END
  END di0[99]
  PIN di0[9]
    DIRECTION INPUT ;
    USE SIGNAL ;
    PORT
      LAYER M5 ;
        RECT  3.312 0 3.336 0.192 ;
    END
  END di0[9]
  PIN do0[0]
    DIRECTION OUTPUT ;
    USE SIGNAL ;
    PORT
      LAYER M5 ;
        RECT  2.88 17.064 2.904 17.256 ;
    END
  END do0[0]
  PIN do0[100]
    DIRECTION OUTPUT ;
    USE SIGNAL ;
    PORT
      LAYER M5 ;
        RECT  7.68 17.064 7.704 17.256 ;
    END
  END do0[100]
  PIN do0[101]
    DIRECTION OUTPUT ;
    USE SIGNAL ;
    PORT
      LAYER M5 ;
        RECT  7.728 17.064 7.752 17.256 ;
    END
  END do0[101]
  PIN do0[102]
    DIRECTION OUTPUT ;
    USE SIGNAL ;
    PORT
      LAYER M5 ;
        RECT  7.776 17.064 7.8 17.256 ;
    END
  END do0[102]
  PIN do0[103]
    DIRECTION OUTPUT ;
    USE SIGNAL ;
    PORT
      LAYER M5 ;
        RECT  7.824 17.064 7.848 17.256 ;
    END
  END do0[103]
  PIN do0[104]
    DIRECTION OUTPUT ;
    USE SIGNAL ;
    PORT
      LAYER M5 ;
        RECT  7.872 17.064 7.896 17.256 ;
    END
  END do0[104]
  PIN do0[105]
    DIRECTION OUTPUT ;
    USE SIGNAL ;
    PORT
      LAYER M5 ;
        RECT  7.92 17.064 7.944 17.256 ;
    END
  END do0[105]
  PIN do0[106]
    DIRECTION OUTPUT ;
    USE SIGNAL ;
    PORT
      LAYER M5 ;
        RECT  7.968 17.064 7.992 17.256 ;
    END
  END do0[106]
  PIN do0[107]
    DIRECTION OUTPUT ;
    USE SIGNAL ;
    PORT
      LAYER M5 ;
        RECT  8.016 17.064 8.04 17.256 ;
    END
  END do0[107]
  PIN do0[108]
    DIRECTION OUTPUT ;
    USE SIGNAL ;
    PORT
      LAYER M5 ;
        RECT  8.064 17.064 8.088 17.256 ;
    END
  END do0[108]
  PIN do0[109]
    DIRECTION OUTPUT ;
    USE SIGNAL ;
    PORT
      LAYER M5 ;
        RECT  8.112 17.064 8.136 17.256 ;
    END
  END do0[109]
  PIN do0[10]
    DIRECTION OUTPUT ;
    USE SIGNAL ;
    PORT
      LAYER M5 ;
        RECT  3.36 17.064 3.384 17.256 ;
    END
  END do0[10]
  PIN do0[110]
    DIRECTION OUTPUT ;
    USE SIGNAL ;
    PORT
      LAYER M5 ;
        RECT  8.16 17.064 8.184 17.256 ;
    END
  END do0[110]
  PIN do0[111]
    DIRECTION OUTPUT ;
    USE SIGNAL ;
    PORT
      LAYER M5 ;
        RECT  8.208 17.064 8.232 17.256 ;
    END
  END do0[111]
  PIN do0[112]
    DIRECTION OUTPUT ;
    USE SIGNAL ;
    PORT
      LAYER M5 ;
        RECT  8.256 17.064 8.28 17.256 ;
    END
  END do0[112]
  PIN do0[113]
    DIRECTION OUTPUT ;
    USE SIGNAL ;
    PORT
      LAYER M5 ;
        RECT  8.304 17.064 8.328 17.256 ;
    END
  END do0[113]
  PIN do0[114]
    DIRECTION OUTPUT ;
    USE SIGNAL ;
    PORT
      LAYER M5 ;
        RECT  8.352 17.064 8.376 17.256 ;
    END
  END do0[114]
  PIN do0[115]
    DIRECTION OUTPUT ;
    USE SIGNAL ;
    PORT
      LAYER M5 ;
        RECT  8.4 17.064 8.424 17.256 ;
    END
  END do0[115]
  PIN do0[116]
    DIRECTION OUTPUT ;
    USE SIGNAL ;
    PORT
      LAYER M5 ;
        RECT  8.448 17.064 8.472 17.256 ;
    END
  END do0[116]
  PIN do0[117]
    DIRECTION OUTPUT ;
    USE SIGNAL ;
    PORT
      LAYER M5 ;
        RECT  8.496 17.064 8.52 17.256 ;
    END
  END do0[117]
  PIN do0[118]
    DIRECTION OUTPUT ;
    USE SIGNAL ;
    PORT
      LAYER M5 ;
        RECT  8.544 17.064 8.568 17.256 ;
    END
  END do0[118]
  PIN do0[119]
    DIRECTION OUTPUT ;
    USE SIGNAL ;
    PORT
      LAYER M5 ;
        RECT  8.592 17.064 8.616 17.256 ;
    END
  END do0[119]
  PIN do0[11]
    DIRECTION OUTPUT ;
    USE SIGNAL ;
    PORT
      LAYER M5 ;
        RECT  3.408 17.064 3.432 17.256 ;
    END
  END do0[11]
  PIN do0[120]
    DIRECTION OUTPUT ;
    USE SIGNAL ;
    PORT
      LAYER M5 ;
        RECT  8.64 17.064 8.664 17.256 ;
    END
  END do0[120]
  PIN do0[121]
    DIRECTION OUTPUT ;
    USE SIGNAL ;
    PORT
      LAYER M5 ;
        RECT  8.688 17.064 8.712 17.256 ;
    END
  END do0[121]
  PIN do0[122]
    DIRECTION OUTPUT ;
    USE SIGNAL ;
    PORT
      LAYER M5 ;
        RECT  8.736 17.064 8.76 17.256 ;
    END
  END do0[122]
  PIN do0[123]
    DIRECTION OUTPUT ;
    USE SIGNAL ;
    PORT
      LAYER M5 ;
        RECT  8.784 17.064 8.808 17.256 ;
    END
  END do0[123]
  PIN do0[124]
    DIRECTION OUTPUT ;
    USE SIGNAL ;
    PORT
      LAYER M5 ;
        RECT  8.832 17.064 8.856 17.256 ;
    END
  END do0[124]
  PIN do0[125]
    DIRECTION OUTPUT ;
    USE SIGNAL ;
    PORT
      LAYER M5 ;
        RECT  8.88 17.064 8.904 17.256 ;
    END
  END do0[125]
  PIN do0[126]
    DIRECTION OUTPUT ;
    USE SIGNAL ;
    PORT
      LAYER M5 ;
        RECT  8.928 17.064 8.952 17.256 ;
    END
  END do0[126]
  PIN do0[127]
    DIRECTION OUTPUT ;
    USE SIGNAL ;
    PORT
      LAYER M5 ;
        RECT  8.976 17.064 9 17.256 ;
    END
  END do0[127]
  PIN do0[128]
    DIRECTION OUTPUT ;
    USE SIGNAL ;
    PORT
      LAYER M5 ;
        RECT  9.024 17.064 9.048 17.256 ;
    END
  END do0[128]
  PIN do0[129]
    DIRECTION OUTPUT ;
    USE SIGNAL ;
    PORT
      LAYER M5 ;
        RECT  9.072 17.064 9.096 17.256 ;
    END
  END do0[129]
  PIN do0[12]
    DIRECTION OUTPUT ;
    USE SIGNAL ;
    PORT
      LAYER M5 ;
        RECT  3.456 17.064 3.48 17.256 ;
    END
  END do0[12]
  PIN do0[130]
    DIRECTION OUTPUT ;
    USE SIGNAL ;
    PORT
      LAYER M5 ;
        RECT  9.12 17.064 9.144 17.256 ;
    END
  END do0[130]
  PIN do0[131]
    DIRECTION OUTPUT ;
    USE SIGNAL ;
    PORT
      LAYER M5 ;
        RECT  9.168 17.064 9.192 17.256 ;
    END
  END do0[131]
  PIN do0[132]
    DIRECTION OUTPUT ;
    USE SIGNAL ;
    PORT
      LAYER M5 ;
        RECT  9.216 17.064 9.24 17.256 ;
    END
  END do0[132]
  PIN do0[133]
    DIRECTION OUTPUT ;
    USE SIGNAL ;
    PORT
      LAYER M5 ;
        RECT  9.264 17.064 9.288 17.256 ;
    END
  END do0[133]
  PIN do0[134]
    DIRECTION OUTPUT ;
    USE SIGNAL ;
    PORT
      LAYER M5 ;
        RECT  9.312 17.064 9.336 17.256 ;
    END
  END do0[134]
  PIN do0[135]
    DIRECTION OUTPUT ;
    USE SIGNAL ;
    PORT
      LAYER M5 ;
        RECT  9.36 17.064 9.384 17.256 ;
    END
  END do0[135]
  PIN do0[136]
    DIRECTION OUTPUT ;
    USE SIGNAL ;
    PORT
      LAYER M5 ;
        RECT  9.408 17.064 9.432 17.256 ;
    END
  END do0[136]
  PIN do0[137]
    DIRECTION OUTPUT ;
    USE SIGNAL ;
    PORT
      LAYER M5 ;
        RECT  9.456 17.064 9.48 17.256 ;
    END
  END do0[137]
  PIN do0[138]
    DIRECTION OUTPUT ;
    USE SIGNAL ;
    PORT
      LAYER M5 ;
        RECT  9.504 17.064 9.528 17.256 ;
    END
  END do0[138]
  PIN do0[139]
    DIRECTION OUTPUT ;
    USE SIGNAL ;
    PORT
      LAYER M5 ;
        RECT  9.552 17.064 9.576 17.256 ;
    END
  END do0[139]
  PIN do0[13]
    DIRECTION OUTPUT ;
    USE SIGNAL ;
    PORT
      LAYER M5 ;
        RECT  3.504 17.064 3.528 17.256 ;
    END
  END do0[13]
  PIN do0[140]
    DIRECTION OUTPUT ;
    USE SIGNAL ;
    PORT
      LAYER M5 ;
        RECT  9.6 17.064 9.624 17.256 ;
    END
  END do0[140]
  PIN do0[141]
    DIRECTION OUTPUT ;
    USE SIGNAL ;
    PORT
      LAYER M5 ;
        RECT  9.648 17.064 9.672 17.256 ;
    END
  END do0[141]
  PIN do0[142]
    DIRECTION OUTPUT ;
    USE SIGNAL ;
    PORT
      LAYER M5 ;
        RECT  9.696 17.064 9.72 17.256 ;
    END
  END do0[142]
  PIN do0[143]
    DIRECTION OUTPUT ;
    USE SIGNAL ;
    PORT
      LAYER M5 ;
        RECT  9.744 17.064 9.768 17.256 ;
    END
  END do0[143]
  PIN do0[144]
    DIRECTION OUTPUT ;
    USE SIGNAL ;
    PORT
      LAYER M5 ;
        RECT  9.792 17.064 9.816 17.256 ;
    END
  END do0[144]
  PIN do0[145]
    DIRECTION OUTPUT ;
    USE SIGNAL ;
    PORT
      LAYER M5 ;
        RECT  9.84 17.064 9.864 17.256 ;
    END
  END do0[145]
  PIN do0[146]
    DIRECTION OUTPUT ;
    USE SIGNAL ;
    PORT
      LAYER M5 ;
        RECT  9.888 17.064 9.912 17.256 ;
    END
  END do0[146]
  PIN do0[147]
    DIRECTION OUTPUT ;
    USE SIGNAL ;
    PORT
      LAYER M5 ;
        RECT  9.936 17.064 9.96 17.256 ;
    END
  END do0[147]
  PIN do0[148]
    DIRECTION OUTPUT ;
    USE SIGNAL ;
    PORT
      LAYER M5 ;
        RECT  9.984 17.064 10.008 17.256 ;
    END
  END do0[148]
  PIN do0[149]
    DIRECTION OUTPUT ;
    USE SIGNAL ;
    PORT
      LAYER M5 ;
        RECT  10.032 17.064 10.056 17.256 ;
    END
  END do0[149]
  PIN do0[14]
    DIRECTION OUTPUT ;
    USE SIGNAL ;
    PORT
      LAYER M5 ;
        RECT  3.552 17.064 3.576 17.256 ;
    END
  END do0[14]
  PIN do0[150]
    DIRECTION OUTPUT ;
    USE SIGNAL ;
    PORT
      LAYER M5 ;
        RECT  10.08 17.064 10.104 17.256 ;
    END
  END do0[150]
  PIN do0[151]
    DIRECTION OUTPUT ;
    USE SIGNAL ;
    PORT
      LAYER M5 ;
        RECT  10.128 17.064 10.152 17.256 ;
    END
  END do0[151]
  PIN do0[152]
    DIRECTION OUTPUT ;
    USE SIGNAL ;
    PORT
      LAYER M5 ;
        RECT  10.176 17.064 10.2 17.256 ;
    END
  END do0[152]
  PIN do0[153]
    DIRECTION OUTPUT ;
    USE SIGNAL ;
    PORT
      LAYER M5 ;
        RECT  10.224 17.064 10.248 17.256 ;
    END
  END do0[153]
  PIN do0[154]
    DIRECTION OUTPUT ;
    USE SIGNAL ;
    PORT
      LAYER M5 ;
        RECT  10.272 17.064 10.296 17.256 ;
    END
  END do0[154]
  PIN do0[155]
    DIRECTION OUTPUT ;
    USE SIGNAL ;
    PORT
      LAYER M5 ;
        RECT  10.32 17.064 10.344 17.256 ;
    END
  END do0[155]
  PIN do0[156]
    DIRECTION OUTPUT ;
    USE SIGNAL ;
    PORT
      LAYER M5 ;
        RECT  10.368 17.064 10.392 17.256 ;
    END
  END do0[156]
  PIN do0[157]
    DIRECTION OUTPUT ;
    USE SIGNAL ;
    PORT
      LAYER M5 ;
        RECT  10.416 17.064 10.44 17.256 ;
    END
  END do0[157]
  PIN do0[158]
    DIRECTION OUTPUT ;
    USE SIGNAL ;
    PORT
      LAYER M5 ;
        RECT  10.464 17.064 10.488 17.256 ;
    END
  END do0[158]
  PIN do0[159]
    DIRECTION OUTPUT ;
    USE SIGNAL ;
    PORT
      LAYER M5 ;
        RECT  10.512 17.064 10.536 17.256 ;
    END
  END do0[159]
  PIN do0[15]
    DIRECTION OUTPUT ;
    USE SIGNAL ;
    PORT
      LAYER M5 ;
        RECT  3.6 17.064 3.624 17.256 ;
    END
  END do0[15]
  PIN do0[160]
    DIRECTION OUTPUT ;
    USE SIGNAL ;
    PORT
      LAYER M5 ;
        RECT  10.56 17.064 10.584 17.256 ;
    END
  END do0[160]
  PIN do0[161]
    DIRECTION OUTPUT ;
    USE SIGNAL ;
    PORT
      LAYER M5 ;
        RECT  10.608 17.064 10.632 17.256 ;
    END
  END do0[161]
  PIN do0[162]
    DIRECTION OUTPUT ;
    USE SIGNAL ;
    PORT
      LAYER M5 ;
        RECT  10.656 17.064 10.68 17.256 ;
    END
  END do0[162]
  PIN do0[163]
    DIRECTION OUTPUT ;
    USE SIGNAL ;
    PORT
      LAYER M5 ;
        RECT  10.704 17.064 10.728 17.256 ;
    END
  END do0[163]
  PIN do0[164]
    DIRECTION OUTPUT ;
    USE SIGNAL ;
    PORT
      LAYER M5 ;
        RECT  10.752 17.064 10.776 17.256 ;
    END
  END do0[164]
  PIN do0[165]
    DIRECTION OUTPUT ;
    USE SIGNAL ;
    PORT
      LAYER M5 ;
        RECT  10.8 17.064 10.824 17.256 ;
    END
  END do0[165]
  PIN do0[166]
    DIRECTION OUTPUT ;
    USE SIGNAL ;
    PORT
      LAYER M5 ;
        RECT  10.848 17.064 10.872 17.256 ;
    END
  END do0[166]
  PIN do0[167]
    DIRECTION OUTPUT ;
    USE SIGNAL ;
    PORT
      LAYER M5 ;
        RECT  10.896 17.064 10.92 17.256 ;
    END
  END do0[167]
  PIN do0[168]
    DIRECTION OUTPUT ;
    USE SIGNAL ;
    PORT
      LAYER M5 ;
        RECT  10.944 17.064 10.968 17.256 ;
    END
  END do0[168]
  PIN do0[169]
    DIRECTION OUTPUT ;
    USE SIGNAL ;
    PORT
      LAYER M5 ;
        RECT  10.992 17.064 11.016 17.256 ;
    END
  END do0[169]
  PIN do0[16]
    DIRECTION OUTPUT ;
    USE SIGNAL ;
    PORT
      LAYER M5 ;
        RECT  3.648 17.064 3.672 17.256 ;
    END
  END do0[16]
  PIN do0[170]
    DIRECTION OUTPUT ;
    USE SIGNAL ;
    PORT
      LAYER M5 ;
        RECT  11.04 17.064 11.064 17.256 ;
    END
  END do0[170]
  PIN do0[171]
    DIRECTION OUTPUT ;
    USE SIGNAL ;
    PORT
      LAYER M5 ;
        RECT  11.088 17.064 11.112 17.256 ;
    END
  END do0[171]
  PIN do0[172]
    DIRECTION OUTPUT ;
    USE SIGNAL ;
    PORT
      LAYER M5 ;
        RECT  11.136 17.064 11.16 17.256 ;
    END
  END do0[172]
  PIN do0[173]
    DIRECTION OUTPUT ;
    USE SIGNAL ;
    PORT
      LAYER M5 ;
        RECT  11.184 17.064 11.208 17.256 ;
    END
  END do0[173]
  PIN do0[174]
    DIRECTION OUTPUT ;
    USE SIGNAL ;
    PORT
      LAYER M5 ;
        RECT  11.232 17.064 11.256 17.256 ;
    END
  END do0[174]
  PIN do0[175]
    DIRECTION OUTPUT ;
    USE SIGNAL ;
    PORT
      LAYER M5 ;
        RECT  11.28 17.064 11.304 17.256 ;
    END
  END do0[175]
  PIN do0[176]
    DIRECTION OUTPUT ;
    USE SIGNAL ;
    PORT
      LAYER M5 ;
        RECT  11.328 17.064 11.352 17.256 ;
    END
  END do0[176]
  PIN do0[177]
    DIRECTION OUTPUT ;
    USE SIGNAL ;
    PORT
      LAYER M5 ;
        RECT  11.376 17.064 11.4 17.256 ;
    END
  END do0[177]
  PIN do0[178]
    DIRECTION OUTPUT ;
    USE SIGNAL ;
    PORT
      LAYER M5 ;
        RECT  11.424 17.064 11.448 17.256 ;
    END
  END do0[178]
  PIN do0[179]
    DIRECTION OUTPUT ;
    USE SIGNAL ;
    PORT
      LAYER M5 ;
        RECT  11.472 17.064 11.496 17.256 ;
    END
  END do0[179]
  PIN do0[17]
    DIRECTION OUTPUT ;
    USE SIGNAL ;
    PORT
      LAYER M5 ;
        RECT  3.696 17.064 3.72 17.256 ;
    END
  END do0[17]
  PIN do0[180]
    DIRECTION OUTPUT ;
    USE SIGNAL ;
    PORT
      LAYER M5 ;
        RECT  11.52 17.064 11.544 17.256 ;
    END
  END do0[180]
  PIN do0[181]
    DIRECTION OUTPUT ;
    USE SIGNAL ;
    PORT
      LAYER M5 ;
        RECT  11.568 17.064 11.592 17.256 ;
    END
  END do0[181]
  PIN do0[182]
    DIRECTION OUTPUT ;
    USE SIGNAL ;
    PORT
      LAYER M5 ;
        RECT  11.616 17.064 11.64 17.256 ;
    END
  END do0[182]
  PIN do0[183]
    DIRECTION OUTPUT ;
    USE SIGNAL ;
    PORT
      LAYER M5 ;
        RECT  11.664 17.064 11.688 17.256 ;
    END
  END do0[183]
  PIN do0[184]
    DIRECTION OUTPUT ;
    USE SIGNAL ;
    PORT
      LAYER M5 ;
        RECT  11.712 17.064 11.736 17.256 ;
    END
  END do0[184]
  PIN do0[185]
    DIRECTION OUTPUT ;
    USE SIGNAL ;
    PORT
      LAYER M5 ;
        RECT  11.76 17.064 11.784 17.256 ;
    END
  END do0[185]
  PIN do0[186]
    DIRECTION OUTPUT ;
    USE SIGNAL ;
    PORT
      LAYER M5 ;
        RECT  11.808 17.064 11.832 17.256 ;
    END
  END do0[186]
  PIN do0[187]
    DIRECTION OUTPUT ;
    USE SIGNAL ;
    PORT
      LAYER M5 ;
        RECT  11.856 17.064 11.88 17.256 ;
    END
  END do0[187]
  PIN do0[188]
    DIRECTION OUTPUT ;
    USE SIGNAL ;
    PORT
      LAYER M5 ;
        RECT  11.904 17.064 11.928 17.256 ;
    END
  END do0[188]
  PIN do0[189]
    DIRECTION OUTPUT ;
    USE SIGNAL ;
    PORT
      LAYER M5 ;
        RECT  11.952 17.064 11.976 17.256 ;
    END
  END do0[189]
  PIN do0[18]
    DIRECTION OUTPUT ;
    USE SIGNAL ;
    PORT
      LAYER M5 ;
        RECT  3.744 17.064 3.768 17.256 ;
    END
  END do0[18]
  PIN do0[190]
    DIRECTION OUTPUT ;
    USE SIGNAL ;
    PORT
      LAYER M5 ;
        RECT  12 17.064 12.024 17.256 ;
    END
  END do0[190]
  PIN do0[191]
    DIRECTION OUTPUT ;
    USE SIGNAL ;
    PORT
      LAYER M5 ;
        RECT  12.048 17.064 12.072 17.256 ;
    END
  END do0[191]
  PIN do0[192]
    DIRECTION OUTPUT ;
    USE SIGNAL ;
    PORT
      LAYER M5 ;
        RECT  12.096 17.064 12.12 17.256 ;
    END
  END do0[192]
  PIN do0[193]
    DIRECTION OUTPUT ;
    USE SIGNAL ;
    PORT
      LAYER M5 ;
        RECT  12.144 17.064 12.168 17.256 ;
    END
  END do0[193]
  PIN do0[194]
    DIRECTION OUTPUT ;
    USE SIGNAL ;
    PORT
      LAYER M5 ;
        RECT  12.192 17.064 12.216 17.256 ;
    END
  END do0[194]
  PIN do0[195]
    DIRECTION OUTPUT ;
    USE SIGNAL ;
    PORT
      LAYER M5 ;
        RECT  12.24 17.064 12.264 17.256 ;
    END
  END do0[195]
  PIN do0[196]
    DIRECTION OUTPUT ;
    USE SIGNAL ;
    PORT
      LAYER M5 ;
        RECT  12.288 17.064 12.312 17.256 ;
    END
  END do0[196]
  PIN do0[197]
    DIRECTION OUTPUT ;
    USE SIGNAL ;
    PORT
      LAYER M5 ;
        RECT  12.336 17.064 12.36 17.256 ;
    END
  END do0[197]
  PIN do0[198]
    DIRECTION OUTPUT ;
    USE SIGNAL ;
    PORT
      LAYER M5 ;
        RECT  12.384 17.064 12.408 17.256 ;
    END
  END do0[198]
  PIN do0[199]
    DIRECTION OUTPUT ;
    USE SIGNAL ;
    PORT
      LAYER M5 ;
        RECT  12.432 17.064 12.456 17.256 ;
    END
  END do0[199]
  PIN do0[19]
    DIRECTION OUTPUT ;
    USE SIGNAL ;
    PORT
      LAYER M5 ;
        RECT  3.792 17.064 3.816 17.256 ;
    END
  END do0[19]
  PIN do0[1]
    DIRECTION OUTPUT ;
    USE SIGNAL ;
    PORT
      LAYER M5 ;
        RECT  2.928 17.064 2.952 17.256 ;
    END
  END do0[1]
  PIN do0[200]
    DIRECTION OUTPUT ;
    USE SIGNAL ;
    PORT
      LAYER M5 ;
        RECT  12.48 17.064 12.504 17.256 ;
    END
  END do0[200]
  PIN do0[201]
    DIRECTION OUTPUT ;
    USE SIGNAL ;
    PORT
      LAYER M5 ;
        RECT  12.528 17.064 12.552 17.256 ;
    END
  END do0[201]
  PIN do0[202]
    DIRECTION OUTPUT ;
    USE SIGNAL ;
    PORT
      LAYER M5 ;
        RECT  12.576 17.064 12.6 17.256 ;
    END
  END do0[202]
  PIN do0[203]
    DIRECTION OUTPUT ;
    USE SIGNAL ;
    PORT
      LAYER M5 ;
        RECT  12.624 17.064 12.648 17.256 ;
    END
  END do0[203]
  PIN do0[204]
    DIRECTION OUTPUT ;
    USE SIGNAL ;
    PORT
      LAYER M5 ;
        RECT  12.672 17.064 12.696 17.256 ;
    END
  END do0[204]
  PIN do0[205]
    DIRECTION OUTPUT ;
    USE SIGNAL ;
    PORT
      LAYER M5 ;
        RECT  12.72 17.064 12.744 17.256 ;
    END
  END do0[205]
  PIN do0[206]
    DIRECTION OUTPUT ;
    USE SIGNAL ;
    PORT
      LAYER M5 ;
        RECT  12.768 17.064 12.792 17.256 ;
    END
  END do0[206]
  PIN do0[207]
    DIRECTION OUTPUT ;
    USE SIGNAL ;
    PORT
      LAYER M5 ;
        RECT  12.816 17.064 12.84 17.256 ;
    END
  END do0[207]
  PIN do0[208]
    DIRECTION OUTPUT ;
    USE SIGNAL ;
    PORT
      LAYER M5 ;
        RECT  12.864 17.064 12.888 17.256 ;
    END
  END do0[208]
  PIN do0[209]
    DIRECTION OUTPUT ;
    USE SIGNAL ;
    PORT
      LAYER M5 ;
        RECT  12.912 17.064 12.936 17.256 ;
    END
  END do0[209]
  PIN do0[20]
    DIRECTION OUTPUT ;
    USE SIGNAL ;
    PORT
      LAYER M5 ;
        RECT  3.84 17.064 3.864 17.256 ;
    END
  END do0[20]
  PIN do0[210]
    DIRECTION OUTPUT ;
    USE SIGNAL ;
    PORT
      LAYER M5 ;
        RECT  12.96 17.064 12.984 17.256 ;
    END
  END do0[210]
  PIN do0[211]
    DIRECTION OUTPUT ;
    USE SIGNAL ;
    PORT
      LAYER M5 ;
        RECT  13.008 17.064 13.032 17.256 ;
    END
  END do0[211]
  PIN do0[212]
    DIRECTION OUTPUT ;
    USE SIGNAL ;
    PORT
      LAYER M5 ;
        RECT  13.056 17.064 13.08 17.256 ;
    END
  END do0[212]
  PIN do0[213]
    DIRECTION OUTPUT ;
    USE SIGNAL ;
    PORT
      LAYER M5 ;
        RECT  13.104 17.064 13.128 17.256 ;
    END
  END do0[213]
  PIN do0[214]
    DIRECTION OUTPUT ;
    USE SIGNAL ;
    PORT
      LAYER M5 ;
        RECT  13.152 17.064 13.176 17.256 ;
    END
  END do0[214]
  PIN do0[215]
    DIRECTION OUTPUT ;
    USE SIGNAL ;
    PORT
      LAYER M5 ;
        RECT  13.2 17.064 13.224 17.256 ;
    END
  END do0[215]
  PIN do0[216]
    DIRECTION OUTPUT ;
    USE SIGNAL ;
    PORT
      LAYER M5 ;
        RECT  13.248 17.064 13.272 17.256 ;
    END
  END do0[216]
  PIN do0[217]
    DIRECTION OUTPUT ;
    USE SIGNAL ;
    PORT
      LAYER M5 ;
        RECT  13.296 17.064 13.32 17.256 ;
    END
  END do0[217]
  PIN do0[218]
    DIRECTION OUTPUT ;
    USE SIGNAL ;
    PORT
      LAYER M5 ;
        RECT  13.344 17.064 13.368 17.256 ;
    END
  END do0[218]
  PIN do0[219]
    DIRECTION OUTPUT ;
    USE SIGNAL ;
    PORT
      LAYER M5 ;
        RECT  13.392 17.064 13.416 17.256 ;
    END
  END do0[219]
  PIN do0[21]
    DIRECTION OUTPUT ;
    USE SIGNAL ;
    PORT
      LAYER M5 ;
        RECT  3.888 17.064 3.912 17.256 ;
    END
  END do0[21]
  PIN do0[220]
    DIRECTION OUTPUT ;
    USE SIGNAL ;
    PORT
      LAYER M5 ;
        RECT  13.44 17.064 13.464 17.256 ;
    END
  END do0[220]
  PIN do0[221]
    DIRECTION OUTPUT ;
    USE SIGNAL ;
    PORT
      LAYER M5 ;
        RECT  13.488 17.064 13.512 17.256 ;
    END
  END do0[221]
  PIN do0[222]
    DIRECTION OUTPUT ;
    USE SIGNAL ;
    PORT
      LAYER M5 ;
        RECT  13.536 17.064 13.56 17.256 ;
    END
  END do0[222]
  PIN do0[223]
    DIRECTION OUTPUT ;
    USE SIGNAL ;
    PORT
      LAYER M5 ;
        RECT  13.584 17.064 13.608 17.256 ;
    END
  END do0[223]
  PIN do0[224]
    DIRECTION OUTPUT ;
    USE SIGNAL ;
    PORT
      LAYER M5 ;
        RECT  13.632 17.064 13.656 17.256 ;
    END
  END do0[224]
  PIN do0[225]
    DIRECTION OUTPUT ;
    USE SIGNAL ;
    PORT
      LAYER M5 ;
        RECT  13.68 17.064 13.704 17.256 ;
    END
  END do0[225]
  PIN do0[226]
    DIRECTION OUTPUT ;
    USE SIGNAL ;
    PORT
      LAYER M5 ;
        RECT  13.728 17.064 13.752 17.256 ;
    END
  END do0[226]
  PIN do0[227]
    DIRECTION OUTPUT ;
    USE SIGNAL ;
    PORT
      LAYER M5 ;
        RECT  13.776 17.064 13.8 17.256 ;
    END
  END do0[227]
  PIN do0[228]
    DIRECTION OUTPUT ;
    USE SIGNAL ;
    PORT
      LAYER M5 ;
        RECT  13.824 17.064 13.848 17.256 ;
    END
  END do0[228]
  PIN do0[229]
    DIRECTION OUTPUT ;
    USE SIGNAL ;
    PORT
      LAYER M5 ;
        RECT  13.872 17.064 13.896 17.256 ;
    END
  END do0[229]
  PIN do0[22]
    DIRECTION OUTPUT ;
    USE SIGNAL ;
    PORT
      LAYER M5 ;
        RECT  3.936 17.064 3.96 17.256 ;
    END
  END do0[22]
  PIN do0[230]
    DIRECTION OUTPUT ;
    USE SIGNAL ;
    PORT
      LAYER M5 ;
        RECT  13.92 17.064 13.944 17.256 ;
    END
  END do0[230]
  PIN do0[231]
    DIRECTION OUTPUT ;
    USE SIGNAL ;
    PORT
      LAYER M5 ;
        RECT  13.968 17.064 13.992 17.256 ;
    END
  END do0[231]
  PIN do0[232]
    DIRECTION OUTPUT ;
    USE SIGNAL ;
    PORT
      LAYER M5 ;
        RECT  14.016 17.064 14.04 17.256 ;
    END
  END do0[232]
  PIN do0[233]
    DIRECTION OUTPUT ;
    USE SIGNAL ;
    PORT
      LAYER M5 ;
        RECT  14.064 17.064 14.088 17.256 ;
    END
  END do0[233]
  PIN do0[234]
    DIRECTION OUTPUT ;
    USE SIGNAL ;
    PORT
      LAYER M5 ;
        RECT  14.112 17.064 14.136 17.256 ;
    END
  END do0[234]
  PIN do0[235]
    DIRECTION OUTPUT ;
    USE SIGNAL ;
    PORT
      LAYER M5 ;
        RECT  14.16 17.064 14.184 17.256 ;
    END
  END do0[235]
  PIN do0[236]
    DIRECTION OUTPUT ;
    USE SIGNAL ;
    PORT
      LAYER M5 ;
        RECT  14.208 17.064 14.232 17.256 ;
    END
  END do0[236]
  PIN do0[237]
    DIRECTION OUTPUT ;
    USE SIGNAL ;
    PORT
      LAYER M5 ;
        RECT  14.256 17.064 14.28 17.256 ;
    END
  END do0[237]
  PIN do0[238]
    DIRECTION OUTPUT ;
    USE SIGNAL ;
    PORT
      LAYER M5 ;
        RECT  14.304 17.064 14.328 17.256 ;
    END
  END do0[238]
  PIN do0[239]
    DIRECTION OUTPUT ;
    USE SIGNAL ;
    PORT
      LAYER M5 ;
        RECT  14.352 17.064 14.376 17.256 ;
    END
  END do0[239]
  PIN do0[23]
    DIRECTION OUTPUT ;
    USE SIGNAL ;
    PORT
      LAYER M5 ;
        RECT  3.984 17.064 4.008 17.256 ;
    END
  END do0[23]
  PIN do0[240]
    DIRECTION OUTPUT ;
    USE SIGNAL ;
    PORT
      LAYER M5 ;
        RECT  14.4 17.064 14.424 17.256 ;
    END
  END do0[240]
  PIN do0[241]
    DIRECTION OUTPUT ;
    USE SIGNAL ;
    PORT
      LAYER M5 ;
        RECT  14.448 17.064 14.472 17.256 ;
    END
  END do0[241]
  PIN do0[242]
    DIRECTION OUTPUT ;
    USE SIGNAL ;
    PORT
      LAYER M5 ;
        RECT  14.496 17.064 14.52 17.256 ;
    END
  END do0[242]
  PIN do0[243]
    DIRECTION OUTPUT ;
    USE SIGNAL ;
    PORT
      LAYER M5 ;
        RECT  14.544 17.064 14.568 17.256 ;
    END
  END do0[243]
  PIN do0[244]
    DIRECTION OUTPUT ;
    USE SIGNAL ;
    PORT
      LAYER M5 ;
        RECT  14.592 17.064 14.616 17.256 ;
    END
  END do0[244]
  PIN do0[245]
    DIRECTION OUTPUT ;
    USE SIGNAL ;
    PORT
      LAYER M5 ;
        RECT  14.64 17.064 14.664 17.256 ;
    END
  END do0[245]
  PIN do0[246]
    DIRECTION OUTPUT ;
    USE SIGNAL ;
    PORT
      LAYER M5 ;
        RECT  14.688 17.064 14.712 17.256 ;
    END
  END do0[246]
  PIN do0[247]
    DIRECTION OUTPUT ;
    USE SIGNAL ;
    PORT
      LAYER M5 ;
        RECT  14.736 17.064 14.76 17.256 ;
    END
  END do0[247]
  PIN do0[248]
    DIRECTION OUTPUT ;
    USE SIGNAL ;
    PORT
      LAYER M5 ;
        RECT  14.784 17.064 14.808 17.256 ;
    END
  END do0[248]
  PIN do0[249]
    DIRECTION OUTPUT ;
    USE SIGNAL ;
    PORT
      LAYER M5 ;
        RECT  14.832 17.064 14.856 17.256 ;
    END
  END do0[249]
  PIN do0[24]
    DIRECTION OUTPUT ;
    USE SIGNAL ;
    PORT
      LAYER M5 ;
        RECT  4.032 17.064 4.056 17.256 ;
    END
  END do0[24]
  PIN do0[250]
    DIRECTION OUTPUT ;
    USE SIGNAL ;
    PORT
      LAYER M5 ;
        RECT  14.88 17.064 14.904 17.256 ;
    END
  END do0[250]
  PIN do0[251]
    DIRECTION OUTPUT ;
    USE SIGNAL ;
    PORT
      LAYER M5 ;
        RECT  14.928 17.064 14.952 17.256 ;
    END
  END do0[251]
  PIN do0[252]
    DIRECTION OUTPUT ;
    USE SIGNAL ;
    PORT
      LAYER M5 ;
        RECT  14.976 17.064 15 17.256 ;
    END
  END do0[252]
  PIN do0[253]
    DIRECTION OUTPUT ;
    USE SIGNAL ;
    PORT
      LAYER M5 ;
        RECT  15.024 17.064 15.048 17.256 ;
    END
  END do0[253]
  PIN do0[254]
    DIRECTION OUTPUT ;
    USE SIGNAL ;
    PORT
      LAYER M5 ;
        RECT  15.072 17.064 15.096 17.256 ;
    END
  END do0[254]
  PIN do0[255]
    DIRECTION OUTPUT ;
    USE SIGNAL ;
    PORT
      LAYER M5 ;
        RECT  15.12 17.064 15.144 17.256 ;
    END
  END do0[255]
  PIN do0[256]
    DIRECTION OUTPUT ;
    USE SIGNAL ;
    PORT
      LAYER M5 ;
        RECT  15.168 17.064 15.192 17.256 ;
    END
  END do0[256]
  PIN do0[257]
    DIRECTION OUTPUT ;
    USE SIGNAL ;
    PORT
      LAYER M5 ;
        RECT  15.216 17.064 15.24 17.256 ;
    END
  END do0[257]
  PIN do0[258]
    DIRECTION OUTPUT ;
    USE SIGNAL ;
    PORT
      LAYER M5 ;
        RECT  15.264 17.064 15.288 17.256 ;
    END
  END do0[258]
  PIN do0[259]
    DIRECTION OUTPUT ;
    USE SIGNAL ;
    PORT
      LAYER M5 ;
        RECT  15.312 17.064 15.336 17.256 ;
    END
  END do0[259]
  PIN do0[25]
    DIRECTION OUTPUT ;
    USE SIGNAL ;
    PORT
      LAYER M5 ;
        RECT  4.08 17.064 4.104 17.256 ;
    END
  END do0[25]
  PIN do0[260]
    DIRECTION OUTPUT ;
    USE SIGNAL ;
    PORT
      LAYER M5 ;
        RECT  15.36 17.064 15.384 17.256 ;
    END
  END do0[260]
  PIN do0[261]
    DIRECTION OUTPUT ;
    USE SIGNAL ;
    PORT
      LAYER M5 ;
        RECT  15.408 17.064 15.432 17.256 ;
    END
  END do0[261]
  PIN do0[262]
    DIRECTION OUTPUT ;
    USE SIGNAL ;
    PORT
      LAYER M5 ;
        RECT  15.456 17.064 15.48 17.256 ;
    END
  END do0[262]
  PIN do0[263]
    DIRECTION OUTPUT ;
    USE SIGNAL ;
    PORT
      LAYER M5 ;
        RECT  15.504 17.064 15.528 17.256 ;
    END
  END do0[263]
  PIN do0[264]
    DIRECTION OUTPUT ;
    USE SIGNAL ;
    PORT
      LAYER M5 ;
        RECT  15.552 17.064 15.576 17.256 ;
    END
  END do0[264]
  PIN do0[265]
    DIRECTION OUTPUT ;
    USE SIGNAL ;
    PORT
      LAYER M5 ;
        RECT  15.6 17.064 15.624 17.256 ;
    END
  END do0[265]
  PIN do0[266]
    DIRECTION OUTPUT ;
    USE SIGNAL ;
    PORT
      LAYER M5 ;
        RECT  15.648 17.064 15.672 17.256 ;
    END
  END do0[266]
  PIN do0[267]
    DIRECTION OUTPUT ;
    USE SIGNAL ;
    PORT
      LAYER M5 ;
        RECT  15.696 17.064 15.72 17.256 ;
    END
  END do0[267]
  PIN do0[268]
    DIRECTION OUTPUT ;
    USE SIGNAL ;
    PORT
      LAYER M5 ;
        RECT  15.744 17.064 15.768 17.256 ;
    END
  END do0[268]
  PIN do0[269]
    DIRECTION OUTPUT ;
    USE SIGNAL ;
    PORT
      LAYER M5 ;
        RECT  15.792 17.064 15.816 17.256 ;
    END
  END do0[269]
  PIN do0[26]
    DIRECTION OUTPUT ;
    USE SIGNAL ;
    PORT
      LAYER M5 ;
        RECT  4.128 17.064 4.152 17.256 ;
    END
  END do0[26]
  PIN do0[270]
    DIRECTION OUTPUT ;
    USE SIGNAL ;
    PORT
      LAYER M5 ;
        RECT  15.84 17.064 15.864 17.256 ;
    END
  END do0[270]
  PIN do0[271]
    DIRECTION OUTPUT ;
    USE SIGNAL ;
    PORT
      LAYER M5 ;
        RECT  15.888 17.064 15.912 17.256 ;
    END
  END do0[271]
  PIN do0[272]
    DIRECTION OUTPUT ;
    USE SIGNAL ;
    PORT
      LAYER M5 ;
        RECT  15.936 17.064 15.96 17.256 ;
    END
  END do0[272]
  PIN do0[273]
    DIRECTION OUTPUT ;
    USE SIGNAL ;
    PORT
      LAYER M5 ;
        RECT  15.984 17.064 16.008 17.256 ;
    END
  END do0[273]
  PIN do0[274]
    DIRECTION OUTPUT ;
    USE SIGNAL ;
    PORT
      LAYER M5 ;
        RECT  16.032 17.064 16.056 17.256 ;
    END
  END do0[274]
  PIN do0[275]
    DIRECTION OUTPUT ;
    USE SIGNAL ;
    PORT
      LAYER M5 ;
        RECT  16.08 17.064 16.104 17.256 ;
    END
  END do0[275]
  PIN do0[276]
    DIRECTION OUTPUT ;
    USE SIGNAL ;
    PORT
      LAYER M5 ;
        RECT  16.128 17.064 16.152 17.256 ;
    END
  END do0[276]
  PIN do0[277]
    DIRECTION OUTPUT ;
    USE SIGNAL ;
    PORT
      LAYER M5 ;
        RECT  16.176 17.064 16.2 17.256 ;
    END
  END do0[277]
  PIN do0[278]
    DIRECTION OUTPUT ;
    USE SIGNAL ;
    PORT
      LAYER M5 ;
        RECT  16.224 17.064 16.248 17.256 ;
    END
  END do0[278]
  PIN do0[279]
    DIRECTION OUTPUT ;
    USE SIGNAL ;
    PORT
      LAYER M5 ;
        RECT  16.272 17.064 16.296 17.256 ;
    END
  END do0[279]
  PIN do0[27]
    DIRECTION OUTPUT ;
    USE SIGNAL ;
    PORT
      LAYER M5 ;
        RECT  4.176 17.064 4.2 17.256 ;
    END
  END do0[27]
  PIN do0[280]
    DIRECTION OUTPUT ;
    USE SIGNAL ;
    PORT
      LAYER M5 ;
        RECT  16.32 17.064 16.344 17.256 ;
    END
  END do0[280]
  PIN do0[281]
    DIRECTION OUTPUT ;
    USE SIGNAL ;
    PORT
      LAYER M5 ;
        RECT  16.368 17.064 16.392 17.256 ;
    END
  END do0[281]
  PIN do0[282]
    DIRECTION OUTPUT ;
    USE SIGNAL ;
    PORT
      LAYER M5 ;
        RECT  16.416 17.064 16.44 17.256 ;
    END
  END do0[282]
  PIN do0[283]
    DIRECTION OUTPUT ;
    USE SIGNAL ;
    PORT
      LAYER M5 ;
        RECT  16.464 17.064 16.488 17.256 ;
    END
  END do0[283]
  PIN do0[284]
    DIRECTION OUTPUT ;
    USE SIGNAL ;
    PORT
      LAYER M5 ;
        RECT  16.512 17.064 16.536 17.256 ;
    END
  END do0[284]
  PIN do0[285]
    DIRECTION OUTPUT ;
    USE SIGNAL ;
    PORT
      LAYER M5 ;
        RECT  16.56 17.064 16.584 17.256 ;
    END
  END do0[285]
  PIN do0[286]
    DIRECTION OUTPUT ;
    USE SIGNAL ;
    PORT
      LAYER M5 ;
        RECT  16.608 17.064 16.632 17.256 ;
    END
  END do0[286]
  PIN do0[287]
    DIRECTION OUTPUT ;
    USE SIGNAL ;
    PORT
      LAYER M5 ;
        RECT  16.656 17.064 16.68 17.256 ;
    END
  END do0[287]
  PIN do0[288]
    DIRECTION OUTPUT ;
    USE SIGNAL ;
    PORT
      LAYER M5 ;
        RECT  16.704 17.064 16.728 17.256 ;
    END
  END do0[288]
  PIN do0[289]
    DIRECTION OUTPUT ;
    USE SIGNAL ;
    PORT
      LAYER M5 ;
        RECT  16.752 17.064 16.776 17.256 ;
    END
  END do0[289]
  PIN do0[28]
    DIRECTION OUTPUT ;
    USE SIGNAL ;
    PORT
      LAYER M5 ;
        RECT  4.224 17.064 4.248 17.256 ;
    END
  END do0[28]
  PIN do0[290]
    DIRECTION OUTPUT ;
    USE SIGNAL ;
    PORT
      LAYER M5 ;
        RECT  16.8 17.064 16.824 17.256 ;
    END
  END do0[290]
  PIN do0[291]
    DIRECTION OUTPUT ;
    USE SIGNAL ;
    PORT
      LAYER M5 ;
        RECT  16.848 17.064 16.872 17.256 ;
    END
  END do0[291]
  PIN do0[292]
    DIRECTION OUTPUT ;
    USE SIGNAL ;
    PORT
      LAYER M5 ;
        RECT  16.896 17.064 16.92 17.256 ;
    END
  END do0[292]
  PIN do0[293]
    DIRECTION OUTPUT ;
    USE SIGNAL ;
    PORT
      LAYER M5 ;
        RECT  16.944 17.064 16.968 17.256 ;
    END
  END do0[293]
  PIN do0[294]
    DIRECTION OUTPUT ;
    USE SIGNAL ;
    PORT
      LAYER M5 ;
        RECT  16.992 17.064 17.016 17.256 ;
    END
  END do0[294]
  PIN do0[295]
    DIRECTION OUTPUT ;
    USE SIGNAL ;
    PORT
      LAYER M5 ;
        RECT  17.04 17.064 17.064 17.256 ;
    END
  END do0[295]
  PIN do0[296]
    DIRECTION OUTPUT ;
    USE SIGNAL ;
    PORT
      LAYER M5 ;
        RECT  17.088 17.064 17.112 17.256 ;
    END
  END do0[296]
  PIN do0[297]
    DIRECTION OUTPUT ;
    USE SIGNAL ;
    PORT
      LAYER M5 ;
        RECT  17.136 17.064 17.16 17.256 ;
    END
  END do0[297]
  PIN do0[298]
    DIRECTION OUTPUT ;
    USE SIGNAL ;
    PORT
      LAYER M5 ;
        RECT  17.184 17.064 17.208 17.256 ;
    END
  END do0[298]
  PIN do0[299]
    DIRECTION OUTPUT ;
    USE SIGNAL ;
    PORT
      LAYER M5 ;
        RECT  17.232 17.064 17.256 17.256 ;
    END
  END do0[299]
  PIN do0[29]
    DIRECTION OUTPUT ;
    USE SIGNAL ;
    PORT
      LAYER M5 ;
        RECT  4.272 17.064 4.296 17.256 ;
    END
  END do0[29]
  PIN do0[2]
    DIRECTION OUTPUT ;
    USE SIGNAL ;
    PORT
      LAYER M5 ;
        RECT  2.976 17.064 3 17.256 ;
    END
  END do0[2]
  PIN do0[300]
    DIRECTION OUTPUT ;
    USE SIGNAL ;
    PORT
      LAYER M5 ;
        RECT  17.28 17.064 17.304 17.256 ;
    END
  END do0[300]
  PIN do0[301]
    DIRECTION OUTPUT ;
    USE SIGNAL ;
    PORT
      LAYER M5 ;
        RECT  17.328 17.064 17.352 17.256 ;
    END
  END do0[301]
  PIN do0[302]
    DIRECTION OUTPUT ;
    USE SIGNAL ;
    PORT
      LAYER M5 ;
        RECT  17.376 17.064 17.4 17.256 ;
    END
  END do0[302]
  PIN do0[303]
    DIRECTION OUTPUT ;
    USE SIGNAL ;
    PORT
      LAYER M5 ;
        RECT  17.424 17.064 17.448 17.256 ;
    END
  END do0[303]
  PIN do0[304]
    DIRECTION OUTPUT ;
    USE SIGNAL ;
    PORT
      LAYER M5 ;
        RECT  17.472 17.064 17.496 17.256 ;
    END
  END do0[304]
  PIN do0[305]
    DIRECTION OUTPUT ;
    USE SIGNAL ;
    PORT
      LAYER M5 ;
        RECT  17.52 17.064 17.544 17.256 ;
    END
  END do0[305]
  PIN do0[306]
    DIRECTION OUTPUT ;
    USE SIGNAL ;
    PORT
      LAYER M5 ;
        RECT  17.568 17.064 17.592 17.256 ;
    END
  END do0[306]
  PIN do0[307]
    DIRECTION OUTPUT ;
    USE SIGNAL ;
    PORT
      LAYER M5 ;
        RECT  17.616 17.064 17.64 17.256 ;
    END
  END do0[307]
  PIN do0[308]
    DIRECTION OUTPUT ;
    USE SIGNAL ;
    PORT
      LAYER M5 ;
        RECT  17.664 17.064 17.688 17.256 ;
    END
  END do0[308]
  PIN do0[309]
    DIRECTION OUTPUT ;
    USE SIGNAL ;
    PORT
      LAYER M5 ;
        RECT  17.712 17.064 17.736 17.256 ;
    END
  END do0[309]
  PIN do0[30]
    DIRECTION OUTPUT ;
    USE SIGNAL ;
    PORT
      LAYER M5 ;
        RECT  4.32 17.064 4.344 17.256 ;
    END
  END do0[30]
  PIN do0[310]
    DIRECTION OUTPUT ;
    USE SIGNAL ;
    PORT
      LAYER M5 ;
        RECT  17.76 17.064 17.784 17.256 ;
    END
  END do0[310]
  PIN do0[311]
    DIRECTION OUTPUT ;
    USE SIGNAL ;
    PORT
      LAYER M5 ;
        RECT  17.808 17.064 17.832 17.256 ;
    END
  END do0[311]
  PIN do0[312]
    DIRECTION OUTPUT ;
    USE SIGNAL ;
    PORT
      LAYER M5 ;
        RECT  17.856 17.064 17.88 17.256 ;
    END
  END do0[312]
  PIN do0[313]
    DIRECTION OUTPUT ;
    USE SIGNAL ;
    PORT
      LAYER M5 ;
        RECT  17.904 17.064 17.928 17.256 ;
    END
  END do0[313]
  PIN do0[314]
    DIRECTION OUTPUT ;
    USE SIGNAL ;
    PORT
      LAYER M5 ;
        RECT  17.952 17.064 17.976 17.256 ;
    END
  END do0[314]
  PIN do0[315]
    DIRECTION OUTPUT ;
    USE SIGNAL ;
    PORT
      LAYER M5 ;
        RECT  18 17.064 18.024 17.256 ;
    END
  END do0[315]
  PIN do0[316]
    DIRECTION OUTPUT ;
    USE SIGNAL ;
    PORT
      LAYER M5 ;
        RECT  18.048 17.064 18.072 17.256 ;
    END
  END do0[316]
  PIN do0[317]
    DIRECTION OUTPUT ;
    USE SIGNAL ;
    PORT
      LAYER M5 ;
        RECT  18.096 17.064 18.12 17.256 ;
    END
  END do0[317]
  PIN do0[318]
    DIRECTION OUTPUT ;
    USE SIGNAL ;
    PORT
      LAYER M5 ;
        RECT  18.144 17.064 18.168 17.256 ;
    END
  END do0[318]
  PIN do0[319]
    DIRECTION OUTPUT ;
    USE SIGNAL ;
    PORT
      LAYER M5 ;
        RECT  18.192 17.064 18.216 17.256 ;
    END
  END do0[319]
  PIN do0[31]
    DIRECTION OUTPUT ;
    USE SIGNAL ;
    PORT
      LAYER M5 ;
        RECT  4.368 17.064 4.392 17.256 ;
    END
  END do0[31]
  PIN do0[320]
    DIRECTION OUTPUT ;
    USE SIGNAL ;
    PORT
      LAYER M5 ;
        RECT  18.24 17.064 18.264 17.256 ;
    END
  END do0[320]
  PIN do0[321]
    DIRECTION OUTPUT ;
    USE SIGNAL ;
    PORT
      LAYER M5 ;
        RECT  18.288 17.064 18.312 17.256 ;
    END
  END do0[321]
  PIN do0[322]
    DIRECTION OUTPUT ;
    USE SIGNAL ;
    PORT
      LAYER M5 ;
        RECT  18.336 17.064 18.36 17.256 ;
    END
  END do0[322]
  PIN do0[323]
    DIRECTION OUTPUT ;
    USE SIGNAL ;
    PORT
      LAYER M5 ;
        RECT  18.384 17.064 18.408 17.256 ;
    END
  END do0[323]
  PIN do0[324]
    DIRECTION OUTPUT ;
    USE SIGNAL ;
    PORT
      LAYER M5 ;
        RECT  18.432 17.064 18.456 17.256 ;
    END
  END do0[324]
  PIN do0[325]
    DIRECTION OUTPUT ;
    USE SIGNAL ;
    PORT
      LAYER M5 ;
        RECT  18.48 17.064 18.504 17.256 ;
    END
  END do0[325]
  PIN do0[326]
    DIRECTION OUTPUT ;
    USE SIGNAL ;
    PORT
      LAYER M5 ;
        RECT  18.528 17.064 18.552 17.256 ;
    END
  END do0[326]
  PIN do0[327]
    DIRECTION OUTPUT ;
    USE SIGNAL ;
    PORT
      LAYER M5 ;
        RECT  18.576 17.064 18.6 17.256 ;
    END
  END do0[327]
  PIN do0[328]
    DIRECTION OUTPUT ;
    USE SIGNAL ;
    PORT
      LAYER M5 ;
        RECT  18.624 17.064 18.648 17.256 ;
    END
  END do0[328]
  PIN do0[329]
    DIRECTION OUTPUT ;
    USE SIGNAL ;
    PORT
      LAYER M5 ;
        RECT  18.672 17.064 18.696 17.256 ;
    END
  END do0[329]
  PIN do0[32]
    DIRECTION OUTPUT ;
    USE SIGNAL ;
    PORT
      LAYER M5 ;
        RECT  4.416 17.064 4.44 17.256 ;
    END
  END do0[32]
  PIN do0[330]
    DIRECTION OUTPUT ;
    USE SIGNAL ;
    PORT
      LAYER M5 ;
        RECT  18.72 17.064 18.744 17.256 ;
    END
  END do0[330]
  PIN do0[331]
    DIRECTION OUTPUT ;
    USE SIGNAL ;
    PORT
      LAYER M5 ;
        RECT  18.768 17.064 18.792 17.256 ;
    END
  END do0[331]
  PIN do0[332]
    DIRECTION OUTPUT ;
    USE SIGNAL ;
    PORT
      LAYER M5 ;
        RECT  18.816 17.064 18.84 17.256 ;
    END
  END do0[332]
  PIN do0[333]
    DIRECTION OUTPUT ;
    USE SIGNAL ;
    PORT
      LAYER M5 ;
        RECT  18.864 17.064 18.888 17.256 ;
    END
  END do0[333]
  PIN do0[334]
    DIRECTION OUTPUT ;
    USE SIGNAL ;
    PORT
      LAYER M5 ;
        RECT  18.912 17.064 18.936 17.256 ;
    END
  END do0[334]
  PIN do0[335]
    DIRECTION OUTPUT ;
    USE SIGNAL ;
    PORT
      LAYER M5 ;
        RECT  18.96 17.064 18.984 17.256 ;
    END
  END do0[335]
  PIN do0[336]
    DIRECTION OUTPUT ;
    USE SIGNAL ;
    PORT
      LAYER M5 ;
        RECT  19.008 17.064 19.032 17.256 ;
    END
  END do0[336]
  PIN do0[337]
    DIRECTION OUTPUT ;
    USE SIGNAL ;
    PORT
      LAYER M5 ;
        RECT  19.056 17.064 19.08 17.256 ;
    END
  END do0[337]
  PIN do0[338]
    DIRECTION OUTPUT ;
    USE SIGNAL ;
    PORT
      LAYER M5 ;
        RECT  19.104 17.064 19.128 17.256 ;
    END
  END do0[338]
  PIN do0[339]
    DIRECTION OUTPUT ;
    USE SIGNAL ;
    PORT
      LAYER M5 ;
        RECT  19.152 17.064 19.176 17.256 ;
    END
  END do0[339]
  PIN do0[33]
    DIRECTION OUTPUT ;
    USE SIGNAL ;
    PORT
      LAYER M5 ;
        RECT  4.464 17.064 4.488 17.256 ;
    END
  END do0[33]
  PIN do0[340]
    DIRECTION OUTPUT ;
    USE SIGNAL ;
    PORT
      LAYER M5 ;
        RECT  19.2 17.064 19.224 17.256 ;
    END
  END do0[340]
  PIN do0[341]
    DIRECTION OUTPUT ;
    USE SIGNAL ;
    PORT
      LAYER M5 ;
        RECT  19.248 17.064 19.272 17.256 ;
    END
  END do0[341]
  PIN do0[342]
    DIRECTION OUTPUT ;
    USE SIGNAL ;
    PORT
      LAYER M5 ;
        RECT  19.296 17.064 19.32 17.256 ;
    END
  END do0[342]
  PIN do0[343]
    DIRECTION OUTPUT ;
    USE SIGNAL ;
    PORT
      LAYER M5 ;
        RECT  19.344 17.064 19.368 17.256 ;
    END
  END do0[343]
  PIN do0[344]
    DIRECTION OUTPUT ;
    USE SIGNAL ;
    PORT
      LAYER M5 ;
        RECT  19.392 17.064 19.416 17.256 ;
    END
  END do0[344]
  PIN do0[345]
    DIRECTION OUTPUT ;
    USE SIGNAL ;
    PORT
      LAYER M5 ;
        RECT  19.44 17.064 19.464 17.256 ;
    END
  END do0[345]
  PIN do0[346]
    DIRECTION OUTPUT ;
    USE SIGNAL ;
    PORT
      LAYER M5 ;
        RECT  19.488 17.064 19.512 17.256 ;
    END
  END do0[346]
  PIN do0[347]
    DIRECTION OUTPUT ;
    USE SIGNAL ;
    PORT
      LAYER M5 ;
        RECT  19.536 17.064 19.56 17.256 ;
    END
  END do0[347]
  PIN do0[348]
    DIRECTION OUTPUT ;
    USE SIGNAL ;
    PORT
      LAYER M5 ;
        RECT  19.584 17.064 19.608 17.256 ;
    END
  END do0[348]
  PIN do0[349]
    DIRECTION OUTPUT ;
    USE SIGNAL ;
    PORT
      LAYER M5 ;
        RECT  19.632 17.064 19.656 17.256 ;
    END
  END do0[349]
  PIN do0[34]
    DIRECTION OUTPUT ;
    USE SIGNAL ;
    PORT
      LAYER M5 ;
        RECT  4.512 17.064 4.536 17.256 ;
    END
  END do0[34]
  PIN do0[350]
    DIRECTION OUTPUT ;
    USE SIGNAL ;
    PORT
      LAYER M5 ;
        RECT  19.68 17.064 19.704 17.256 ;
    END
  END do0[350]
  PIN do0[351]
    DIRECTION OUTPUT ;
    USE SIGNAL ;
    PORT
      LAYER M5 ;
        RECT  19.728 17.064 19.752 17.256 ;
    END
  END do0[351]
  PIN do0[352]
    DIRECTION OUTPUT ;
    USE SIGNAL ;
    PORT
      LAYER M5 ;
        RECT  19.776 17.064 19.8 17.256 ;
    END
  END do0[352]
  PIN do0[353]
    DIRECTION OUTPUT ;
    USE SIGNAL ;
    PORT
      LAYER M5 ;
        RECT  19.824 17.064 19.848 17.256 ;
    END
  END do0[353]
  PIN do0[354]
    DIRECTION OUTPUT ;
    USE SIGNAL ;
    PORT
      LAYER M5 ;
        RECT  19.872 17.064 19.896 17.256 ;
    END
  END do0[354]
  PIN do0[355]
    DIRECTION OUTPUT ;
    USE SIGNAL ;
    PORT
      LAYER M5 ;
        RECT  19.92 17.064 19.944 17.256 ;
    END
  END do0[355]
  PIN do0[356]
    DIRECTION OUTPUT ;
    USE SIGNAL ;
    PORT
      LAYER M5 ;
        RECT  19.968 17.064 19.992 17.256 ;
    END
  END do0[356]
  PIN do0[357]
    DIRECTION OUTPUT ;
    USE SIGNAL ;
    PORT
      LAYER M5 ;
        RECT  20.016 17.064 20.04 17.256 ;
    END
  END do0[357]
  PIN do0[358]
    DIRECTION OUTPUT ;
    USE SIGNAL ;
    PORT
      LAYER M5 ;
        RECT  20.064 17.064 20.088 17.256 ;
    END
  END do0[358]
  PIN do0[359]
    DIRECTION OUTPUT ;
    USE SIGNAL ;
    PORT
      LAYER M5 ;
        RECT  20.112 17.064 20.136 17.256 ;
    END
  END do0[359]
  PIN do0[35]
    DIRECTION OUTPUT ;
    USE SIGNAL ;
    PORT
      LAYER M5 ;
        RECT  4.56 17.064 4.584 17.256 ;
    END
  END do0[35]
  PIN do0[360]
    DIRECTION OUTPUT ;
    USE SIGNAL ;
    PORT
      LAYER M5 ;
        RECT  20.16 17.064 20.184 17.256 ;
    END
  END do0[360]
  PIN do0[361]
    DIRECTION OUTPUT ;
    USE SIGNAL ;
    PORT
      LAYER M5 ;
        RECT  20.208 17.064 20.232 17.256 ;
    END
  END do0[361]
  PIN do0[362]
    DIRECTION OUTPUT ;
    USE SIGNAL ;
    PORT
      LAYER M5 ;
        RECT  20.256 17.064 20.28 17.256 ;
    END
  END do0[362]
  PIN do0[363]
    DIRECTION OUTPUT ;
    USE SIGNAL ;
    PORT
      LAYER M5 ;
        RECT  20.304 17.064 20.328 17.256 ;
    END
  END do0[363]
  PIN do0[364]
    DIRECTION OUTPUT ;
    USE SIGNAL ;
    PORT
      LAYER M5 ;
        RECT  20.352 17.064 20.376 17.256 ;
    END
  END do0[364]
  PIN do0[365]
    DIRECTION OUTPUT ;
    USE SIGNAL ;
    PORT
      LAYER M5 ;
        RECT  20.4 17.064 20.424 17.256 ;
    END
  END do0[365]
  PIN do0[366]
    DIRECTION OUTPUT ;
    USE SIGNAL ;
    PORT
      LAYER M5 ;
        RECT  20.448 17.064 20.472 17.256 ;
    END
  END do0[366]
  PIN do0[367]
    DIRECTION OUTPUT ;
    USE SIGNAL ;
    PORT
      LAYER M5 ;
        RECT  20.496 17.064 20.52 17.256 ;
    END
  END do0[367]
  PIN do0[368]
    DIRECTION OUTPUT ;
    USE SIGNAL ;
    PORT
      LAYER M5 ;
        RECT  20.544 17.064 20.568 17.256 ;
    END
  END do0[368]
  PIN do0[369]
    DIRECTION OUTPUT ;
    USE SIGNAL ;
    PORT
      LAYER M5 ;
        RECT  20.592 17.064 20.616 17.256 ;
    END
  END do0[369]
  PIN do0[36]
    DIRECTION OUTPUT ;
    USE SIGNAL ;
    PORT
      LAYER M5 ;
        RECT  4.608 17.064 4.632 17.256 ;
    END
  END do0[36]
  PIN do0[370]
    DIRECTION OUTPUT ;
    USE SIGNAL ;
    PORT
      LAYER M5 ;
        RECT  20.64 17.064 20.664 17.256 ;
    END
  END do0[370]
  PIN do0[371]
    DIRECTION OUTPUT ;
    USE SIGNAL ;
    PORT
      LAYER M5 ;
        RECT  20.688 17.064 20.712 17.256 ;
    END
  END do0[371]
  PIN do0[372]
    DIRECTION OUTPUT ;
    USE SIGNAL ;
    PORT
      LAYER M5 ;
        RECT  20.736 17.064 20.76 17.256 ;
    END
  END do0[372]
  PIN do0[373]
    DIRECTION OUTPUT ;
    USE SIGNAL ;
    PORT
      LAYER M5 ;
        RECT  20.784 17.064 20.808 17.256 ;
    END
  END do0[373]
  PIN do0[374]
    DIRECTION OUTPUT ;
    USE SIGNAL ;
    PORT
      LAYER M5 ;
        RECT  20.832 17.064 20.856 17.256 ;
    END
  END do0[374]
  PIN do0[375]
    DIRECTION OUTPUT ;
    USE SIGNAL ;
    PORT
      LAYER M5 ;
        RECT  20.88 17.064 20.904 17.256 ;
    END
  END do0[375]
  PIN do0[376]
    DIRECTION OUTPUT ;
    USE SIGNAL ;
    PORT
      LAYER M5 ;
        RECT  20.928 17.064 20.952 17.256 ;
    END
  END do0[376]
  PIN do0[377]
    DIRECTION OUTPUT ;
    USE SIGNAL ;
    PORT
      LAYER M5 ;
        RECT  20.976 17.064 21 17.256 ;
    END
  END do0[377]
  PIN do0[378]
    DIRECTION OUTPUT ;
    USE SIGNAL ;
    PORT
      LAYER M5 ;
        RECT  21.024 17.064 21.048 17.256 ;
    END
  END do0[378]
  PIN do0[379]
    DIRECTION OUTPUT ;
    USE SIGNAL ;
    PORT
      LAYER M5 ;
        RECT  21.072 17.064 21.096 17.256 ;
    END
  END do0[379]
  PIN do0[37]
    DIRECTION OUTPUT ;
    USE SIGNAL ;
    PORT
      LAYER M5 ;
        RECT  4.656 17.064 4.68 17.256 ;
    END
  END do0[37]
  PIN do0[380]
    DIRECTION OUTPUT ;
    USE SIGNAL ;
    PORT
      LAYER M5 ;
        RECT  21.12 17.064 21.144 17.256 ;
    END
  END do0[380]
  PIN do0[381]
    DIRECTION OUTPUT ;
    USE SIGNAL ;
    PORT
      LAYER M5 ;
        RECT  21.168 17.064 21.192 17.256 ;
    END
  END do0[381]
  PIN do0[382]
    DIRECTION OUTPUT ;
    USE SIGNAL ;
    PORT
      LAYER M5 ;
        RECT  21.216 17.064 21.24 17.256 ;
    END
  END do0[382]
  PIN do0[383]
    DIRECTION OUTPUT ;
    USE SIGNAL ;
    PORT
      LAYER M5 ;
        RECT  21.264 17.064 21.288 17.256 ;
    END
  END do0[383]
  PIN do0[384]
    DIRECTION OUTPUT ;
    USE SIGNAL ;
    PORT
      LAYER M5 ;
        RECT  21.312 17.064 21.336 17.256 ;
    END
  END do0[384]
  PIN do0[385]
    DIRECTION OUTPUT ;
    USE SIGNAL ;
    PORT
      LAYER M5 ;
        RECT  21.36 17.064 21.384 17.256 ;
    END
  END do0[385]
  PIN do0[386]
    DIRECTION OUTPUT ;
    USE SIGNAL ;
    PORT
      LAYER M5 ;
        RECT  21.408 17.064 21.432 17.256 ;
    END
  END do0[386]
  PIN do0[387]
    DIRECTION OUTPUT ;
    USE SIGNAL ;
    PORT
      LAYER M5 ;
        RECT  21.456 17.064 21.48 17.256 ;
    END
  END do0[387]
  PIN do0[388]
    DIRECTION OUTPUT ;
    USE SIGNAL ;
    PORT
      LAYER M5 ;
        RECT  21.504 17.064 21.528 17.256 ;
    END
  END do0[388]
  PIN do0[389]
    DIRECTION OUTPUT ;
    USE SIGNAL ;
    PORT
      LAYER M5 ;
        RECT  21.552 17.064 21.576 17.256 ;
    END
  END do0[389]
  PIN do0[38]
    DIRECTION OUTPUT ;
    USE SIGNAL ;
    PORT
      LAYER M5 ;
        RECT  4.704 17.064 4.728 17.256 ;
    END
  END do0[38]
  PIN do0[390]
    DIRECTION OUTPUT ;
    USE SIGNAL ;
    PORT
      LAYER M5 ;
        RECT  21.6 17.064 21.624 17.256 ;
    END
  END do0[390]
  PIN do0[391]
    DIRECTION OUTPUT ;
    USE SIGNAL ;
    PORT
      LAYER M5 ;
        RECT  21.648 17.064 21.672 17.256 ;
    END
  END do0[391]
  PIN do0[392]
    DIRECTION OUTPUT ;
    USE SIGNAL ;
    PORT
      LAYER M5 ;
        RECT  21.696 17.064 21.72 17.256 ;
    END
  END do0[392]
  PIN do0[393]
    DIRECTION OUTPUT ;
    USE SIGNAL ;
    PORT
      LAYER M5 ;
        RECT  21.744 17.064 21.768 17.256 ;
    END
  END do0[393]
  PIN do0[394]
    DIRECTION OUTPUT ;
    USE SIGNAL ;
    PORT
      LAYER M5 ;
        RECT  21.792 17.064 21.816 17.256 ;
    END
  END do0[394]
  PIN do0[395]
    DIRECTION OUTPUT ;
    USE SIGNAL ;
    PORT
      LAYER M5 ;
        RECT  21.84 17.064 21.864 17.256 ;
    END
  END do0[395]
  PIN do0[396]
    DIRECTION OUTPUT ;
    USE SIGNAL ;
    PORT
      LAYER M5 ;
        RECT  21.888 17.064 21.912 17.256 ;
    END
  END do0[396]
  PIN do0[397]
    DIRECTION OUTPUT ;
    USE SIGNAL ;
    PORT
      LAYER M5 ;
        RECT  21.936 17.064 21.96 17.256 ;
    END
  END do0[397]
  PIN do0[398]
    DIRECTION OUTPUT ;
    USE SIGNAL ;
    PORT
      LAYER M5 ;
        RECT  21.984 17.064 22.008 17.256 ;
    END
  END do0[398]
  PIN do0[399]
    DIRECTION OUTPUT ;
    USE SIGNAL ;
    PORT
      LAYER M5 ;
        RECT  22.032 17.064 22.056 17.256 ;
    END
  END do0[399]
  PIN do0[39]
    DIRECTION OUTPUT ;
    USE SIGNAL ;
    PORT
      LAYER M5 ;
        RECT  4.752 17.064 4.776 17.256 ;
    END
  END do0[39]
  PIN do0[3]
    DIRECTION OUTPUT ;
    USE SIGNAL ;
    PORT
      LAYER M5 ;
        RECT  3.024 17.064 3.048 17.256 ;
    END
  END do0[3]
  PIN do0[400]
    DIRECTION OUTPUT ;
    USE SIGNAL ;
    PORT
      LAYER M5 ;
        RECT  22.08 17.064 22.104 17.256 ;
    END
  END do0[400]
  PIN do0[401]
    DIRECTION OUTPUT ;
    USE SIGNAL ;
    PORT
      LAYER M5 ;
        RECT  22.128 17.064 22.152 17.256 ;
    END
  END do0[401]
  PIN do0[402]
    DIRECTION OUTPUT ;
    USE SIGNAL ;
    PORT
      LAYER M5 ;
        RECT  22.176 17.064 22.2 17.256 ;
    END
  END do0[402]
  PIN do0[403]
    DIRECTION OUTPUT ;
    USE SIGNAL ;
    PORT
      LAYER M5 ;
        RECT  22.224 17.064 22.248 17.256 ;
    END
  END do0[403]
  PIN do0[404]
    DIRECTION OUTPUT ;
    USE SIGNAL ;
    PORT
      LAYER M5 ;
        RECT  22.272 17.064 22.296 17.256 ;
    END
  END do0[404]
  PIN do0[405]
    DIRECTION OUTPUT ;
    USE SIGNAL ;
    PORT
      LAYER M5 ;
        RECT  22.32 17.064 22.344 17.256 ;
    END
  END do0[405]
  PIN do0[406]
    DIRECTION OUTPUT ;
    USE SIGNAL ;
    PORT
      LAYER M5 ;
        RECT  22.368 17.064 22.392 17.256 ;
    END
  END do0[406]
  PIN do0[407]
    DIRECTION OUTPUT ;
    USE SIGNAL ;
    PORT
      LAYER M5 ;
        RECT  22.416 17.064 22.44 17.256 ;
    END
  END do0[407]
  PIN do0[408]
    DIRECTION OUTPUT ;
    USE SIGNAL ;
    PORT
      LAYER M5 ;
        RECT  22.464 17.064 22.488 17.256 ;
    END
  END do0[408]
  PIN do0[409]
    DIRECTION OUTPUT ;
    USE SIGNAL ;
    PORT
      LAYER M5 ;
        RECT  22.512 17.064 22.536 17.256 ;
    END
  END do0[409]
  PIN do0[40]
    DIRECTION OUTPUT ;
    USE SIGNAL ;
    PORT
      LAYER M5 ;
        RECT  4.8 17.064 4.824 17.256 ;
    END
  END do0[40]
  PIN do0[410]
    DIRECTION OUTPUT ;
    USE SIGNAL ;
    PORT
      LAYER M5 ;
        RECT  22.56 17.064 22.584 17.256 ;
    END
  END do0[410]
  PIN do0[411]
    DIRECTION OUTPUT ;
    USE SIGNAL ;
    PORT
      LAYER M5 ;
        RECT  22.608 17.064 22.632 17.256 ;
    END
  END do0[411]
  PIN do0[412]
    DIRECTION OUTPUT ;
    USE SIGNAL ;
    PORT
      LAYER M5 ;
        RECT  22.656 17.064 22.68 17.256 ;
    END
  END do0[412]
  PIN do0[413]
    DIRECTION OUTPUT ;
    USE SIGNAL ;
    PORT
      LAYER M5 ;
        RECT  22.704 17.064 22.728 17.256 ;
    END
  END do0[413]
  PIN do0[414]
    DIRECTION OUTPUT ;
    USE SIGNAL ;
    PORT
      LAYER M5 ;
        RECT  22.752 17.064 22.776 17.256 ;
    END
  END do0[414]
  PIN do0[415]
    DIRECTION OUTPUT ;
    USE SIGNAL ;
    PORT
      LAYER M5 ;
        RECT  22.8 17.064 22.824 17.256 ;
    END
  END do0[415]
  PIN do0[416]
    DIRECTION OUTPUT ;
    USE SIGNAL ;
    PORT
      LAYER M5 ;
        RECT  22.848 17.064 22.872 17.256 ;
    END
  END do0[416]
  PIN do0[417]
    DIRECTION OUTPUT ;
    USE SIGNAL ;
    PORT
      LAYER M5 ;
        RECT  22.896 17.064 22.92 17.256 ;
    END
  END do0[417]
  PIN do0[418]
    DIRECTION OUTPUT ;
    USE SIGNAL ;
    PORT
      LAYER M5 ;
        RECT  22.944 17.064 22.968 17.256 ;
    END
  END do0[418]
  PIN do0[419]
    DIRECTION OUTPUT ;
    USE SIGNAL ;
    PORT
      LAYER M5 ;
        RECT  22.992 17.064 23.016 17.256 ;
    END
  END do0[419]
  PIN do0[41]
    DIRECTION OUTPUT ;
    USE SIGNAL ;
    PORT
      LAYER M5 ;
        RECT  4.848 17.064 4.872 17.256 ;
    END
  END do0[41]
  PIN do0[420]
    DIRECTION OUTPUT ;
    USE SIGNAL ;
    PORT
      LAYER M5 ;
        RECT  23.04 17.064 23.064 17.256 ;
    END
  END do0[420]
  PIN do0[421]
    DIRECTION OUTPUT ;
    USE SIGNAL ;
    PORT
      LAYER M5 ;
        RECT  23.088 17.064 23.112 17.256 ;
    END
  END do0[421]
  PIN do0[422]
    DIRECTION OUTPUT ;
    USE SIGNAL ;
    PORT
      LAYER M5 ;
        RECT  23.136 17.064 23.16 17.256 ;
    END
  END do0[422]
  PIN do0[423]
    DIRECTION OUTPUT ;
    USE SIGNAL ;
    PORT
      LAYER M5 ;
        RECT  23.184 17.064 23.208 17.256 ;
    END
  END do0[423]
  PIN do0[424]
    DIRECTION OUTPUT ;
    USE SIGNAL ;
    PORT
      LAYER M5 ;
        RECT  23.232 17.064 23.256 17.256 ;
    END
  END do0[424]
  PIN do0[425]
    DIRECTION OUTPUT ;
    USE SIGNAL ;
    PORT
      LAYER M5 ;
        RECT  23.28 17.064 23.304 17.256 ;
    END
  END do0[425]
  PIN do0[426]
    DIRECTION OUTPUT ;
    USE SIGNAL ;
    PORT
      LAYER M5 ;
        RECT  23.328 17.064 23.352 17.256 ;
    END
  END do0[426]
  PIN do0[427]
    DIRECTION OUTPUT ;
    USE SIGNAL ;
    PORT
      LAYER M5 ;
        RECT  23.376 17.064 23.4 17.256 ;
    END
  END do0[427]
  PIN do0[428]
    DIRECTION OUTPUT ;
    USE SIGNAL ;
    PORT
      LAYER M5 ;
        RECT  23.424 17.064 23.448 17.256 ;
    END
  END do0[428]
  PIN do0[429]
    DIRECTION OUTPUT ;
    USE SIGNAL ;
    PORT
      LAYER M5 ;
        RECT  23.472 17.064 23.496 17.256 ;
    END
  END do0[429]
  PIN do0[42]
    DIRECTION OUTPUT ;
    USE SIGNAL ;
    PORT
      LAYER M5 ;
        RECT  4.896 17.064 4.92 17.256 ;
    END
  END do0[42]
  PIN do0[430]
    DIRECTION OUTPUT ;
    USE SIGNAL ;
    PORT
      LAYER M5 ;
        RECT  23.52 17.064 23.544 17.256 ;
    END
  END do0[430]
  PIN do0[431]
    DIRECTION OUTPUT ;
    USE SIGNAL ;
    PORT
      LAYER M5 ;
        RECT  23.568 17.064 23.592 17.256 ;
    END
  END do0[431]
  PIN do0[432]
    DIRECTION OUTPUT ;
    USE SIGNAL ;
    PORT
      LAYER M5 ;
        RECT  23.616 17.064 23.64 17.256 ;
    END
  END do0[432]
  PIN do0[433]
    DIRECTION OUTPUT ;
    USE SIGNAL ;
    PORT
      LAYER M5 ;
        RECT  23.664 17.064 23.688 17.256 ;
    END
  END do0[433]
  PIN do0[434]
    DIRECTION OUTPUT ;
    USE SIGNAL ;
    PORT
      LAYER M5 ;
        RECT  23.712 17.064 23.736 17.256 ;
    END
  END do0[434]
  PIN do0[435]
    DIRECTION OUTPUT ;
    USE SIGNAL ;
    PORT
      LAYER M5 ;
        RECT  23.76 17.064 23.784 17.256 ;
    END
  END do0[435]
  PIN do0[436]
    DIRECTION OUTPUT ;
    USE SIGNAL ;
    PORT
      LAYER M5 ;
        RECT  23.808 17.064 23.832 17.256 ;
    END
  END do0[436]
  PIN do0[437]
    DIRECTION OUTPUT ;
    USE SIGNAL ;
    PORT
      LAYER M5 ;
        RECT  23.856 17.064 23.88 17.256 ;
    END
  END do0[437]
  PIN do0[438]
    DIRECTION OUTPUT ;
    USE SIGNAL ;
    PORT
      LAYER M5 ;
        RECT  23.904 17.064 23.928 17.256 ;
    END
  END do0[438]
  PIN do0[439]
    DIRECTION OUTPUT ;
    USE SIGNAL ;
    PORT
      LAYER M5 ;
        RECT  23.952 17.064 23.976 17.256 ;
    END
  END do0[439]
  PIN do0[43]
    DIRECTION OUTPUT ;
    USE SIGNAL ;
    PORT
      LAYER M5 ;
        RECT  4.944 17.064 4.968 17.256 ;
    END
  END do0[43]
  PIN do0[440]
    DIRECTION OUTPUT ;
    USE SIGNAL ;
    PORT
      LAYER M5 ;
        RECT  24 17.064 24.024 17.256 ;
    END
  END do0[440]
  PIN do0[441]
    DIRECTION OUTPUT ;
    USE SIGNAL ;
    PORT
      LAYER M5 ;
        RECT  24.048 17.064 24.072 17.256 ;
    END
  END do0[441]
  PIN do0[442]
    DIRECTION OUTPUT ;
    USE SIGNAL ;
    PORT
      LAYER M5 ;
        RECT  24.096 17.064 24.12 17.256 ;
    END
  END do0[442]
  PIN do0[443]
    DIRECTION OUTPUT ;
    USE SIGNAL ;
    PORT
      LAYER M5 ;
        RECT  24.144 17.064 24.168 17.256 ;
    END
  END do0[443]
  PIN do0[444]
    DIRECTION OUTPUT ;
    USE SIGNAL ;
    PORT
      LAYER M5 ;
        RECT  24.192 17.064 24.216 17.256 ;
    END
  END do0[444]
  PIN do0[445]
    DIRECTION OUTPUT ;
    USE SIGNAL ;
    PORT
      LAYER M5 ;
        RECT  24.24 17.064 24.264 17.256 ;
    END
  END do0[445]
  PIN do0[446]
    DIRECTION OUTPUT ;
    USE SIGNAL ;
    PORT
      LAYER M5 ;
        RECT  24.288 17.064 24.312 17.256 ;
    END
  END do0[446]
  PIN do0[447]
    DIRECTION OUTPUT ;
    USE SIGNAL ;
    PORT
      LAYER M5 ;
        RECT  24.336 17.064 24.36 17.256 ;
    END
  END do0[447]
  PIN do0[448]
    DIRECTION OUTPUT ;
    USE SIGNAL ;
    PORT
      LAYER M5 ;
        RECT  24.384 17.064 24.408 17.256 ;
    END
  END do0[448]
  PIN do0[449]
    DIRECTION OUTPUT ;
    USE SIGNAL ;
    PORT
      LAYER M5 ;
        RECT  24.432 17.064 24.456 17.256 ;
    END
  END do0[449]
  PIN do0[44]
    DIRECTION OUTPUT ;
    USE SIGNAL ;
    PORT
      LAYER M5 ;
        RECT  4.992 17.064 5.016 17.256 ;
    END
  END do0[44]
  PIN do0[450]
    DIRECTION OUTPUT ;
    USE SIGNAL ;
    PORT
      LAYER M5 ;
        RECT  24.48 17.064 24.504 17.256 ;
    END
  END do0[450]
  PIN do0[451]
    DIRECTION OUTPUT ;
    USE SIGNAL ;
    PORT
      LAYER M5 ;
        RECT  24.528 17.064 24.552 17.256 ;
    END
  END do0[451]
  PIN do0[452]
    DIRECTION OUTPUT ;
    USE SIGNAL ;
    PORT
      LAYER M5 ;
        RECT  24.576 17.064 24.6 17.256 ;
    END
  END do0[452]
  PIN do0[453]
    DIRECTION OUTPUT ;
    USE SIGNAL ;
    PORT
      LAYER M5 ;
        RECT  24.624 17.064 24.648 17.256 ;
    END
  END do0[453]
  PIN do0[454]
    DIRECTION OUTPUT ;
    USE SIGNAL ;
    PORT
      LAYER M5 ;
        RECT  24.672 17.064 24.696 17.256 ;
    END
  END do0[454]
  PIN do0[455]
    DIRECTION OUTPUT ;
    USE SIGNAL ;
    PORT
      LAYER M5 ;
        RECT  24.72 17.064 24.744 17.256 ;
    END
  END do0[455]
  PIN do0[456]
    DIRECTION OUTPUT ;
    USE SIGNAL ;
    PORT
      LAYER M5 ;
        RECT  24.768 17.064 24.792 17.256 ;
    END
  END do0[456]
  PIN do0[457]
    DIRECTION OUTPUT ;
    USE SIGNAL ;
    PORT
      LAYER M5 ;
        RECT  24.816 17.064 24.84 17.256 ;
    END
  END do0[457]
  PIN do0[458]
    DIRECTION OUTPUT ;
    USE SIGNAL ;
    PORT
      LAYER M5 ;
        RECT  24.864 17.064 24.888 17.256 ;
    END
  END do0[458]
  PIN do0[459]
    DIRECTION OUTPUT ;
    USE SIGNAL ;
    PORT
      LAYER M5 ;
        RECT  24.912 17.064 24.936 17.256 ;
    END
  END do0[459]
  PIN do0[45]
    DIRECTION OUTPUT ;
    USE SIGNAL ;
    PORT
      LAYER M5 ;
        RECT  5.04 17.064 5.064 17.256 ;
    END
  END do0[45]
  PIN do0[460]
    DIRECTION OUTPUT ;
    USE SIGNAL ;
    PORT
      LAYER M5 ;
        RECT  24.96 17.064 24.984 17.256 ;
    END
  END do0[460]
  PIN do0[461]
    DIRECTION OUTPUT ;
    USE SIGNAL ;
    PORT
      LAYER M5 ;
        RECT  25.008 17.064 25.032 17.256 ;
    END
  END do0[461]
  PIN do0[462]
    DIRECTION OUTPUT ;
    USE SIGNAL ;
    PORT
      LAYER M5 ;
        RECT  25.056 17.064 25.08 17.256 ;
    END
  END do0[462]
  PIN do0[463]
    DIRECTION OUTPUT ;
    USE SIGNAL ;
    PORT
      LAYER M5 ;
        RECT  25.104 17.064 25.128 17.256 ;
    END
  END do0[463]
  PIN do0[464]
    DIRECTION OUTPUT ;
    USE SIGNAL ;
    PORT
      LAYER M5 ;
        RECT  25.152 17.064 25.176 17.256 ;
    END
  END do0[464]
  PIN do0[465]
    DIRECTION OUTPUT ;
    USE SIGNAL ;
    PORT
      LAYER M5 ;
        RECT  25.2 17.064 25.224 17.256 ;
    END
  END do0[465]
  PIN do0[466]
    DIRECTION OUTPUT ;
    USE SIGNAL ;
    PORT
      LAYER M5 ;
        RECT  25.248 17.064 25.272 17.256 ;
    END
  END do0[466]
  PIN do0[467]
    DIRECTION OUTPUT ;
    USE SIGNAL ;
    PORT
      LAYER M5 ;
        RECT  25.296 17.064 25.32 17.256 ;
    END
  END do0[467]
  PIN do0[468]
    DIRECTION OUTPUT ;
    USE SIGNAL ;
    PORT
      LAYER M5 ;
        RECT  25.344 17.064 25.368 17.256 ;
    END
  END do0[468]
  PIN do0[469]
    DIRECTION OUTPUT ;
    USE SIGNAL ;
    PORT
      LAYER M5 ;
        RECT  25.392 17.064 25.416 17.256 ;
    END
  END do0[469]
  PIN do0[46]
    DIRECTION OUTPUT ;
    USE SIGNAL ;
    PORT
      LAYER M5 ;
        RECT  5.088 17.064 5.112 17.256 ;
    END
  END do0[46]
  PIN do0[470]
    DIRECTION OUTPUT ;
    USE SIGNAL ;
    PORT
      LAYER M5 ;
        RECT  25.44 17.064 25.464 17.256 ;
    END
  END do0[470]
  PIN do0[471]
    DIRECTION OUTPUT ;
    USE SIGNAL ;
    PORT
      LAYER M5 ;
        RECT  25.488 17.064 25.512 17.256 ;
    END
  END do0[471]
  PIN do0[472]
    DIRECTION OUTPUT ;
    USE SIGNAL ;
    PORT
      LAYER M5 ;
        RECT  25.536 17.064 25.56 17.256 ;
    END
  END do0[472]
  PIN do0[473]
    DIRECTION OUTPUT ;
    USE SIGNAL ;
    PORT
      LAYER M5 ;
        RECT  25.584 17.064 25.608 17.256 ;
    END
  END do0[473]
  PIN do0[474]
    DIRECTION OUTPUT ;
    USE SIGNAL ;
    PORT
      LAYER M5 ;
        RECT  25.632 17.064 25.656 17.256 ;
    END
  END do0[474]
  PIN do0[475]
    DIRECTION OUTPUT ;
    USE SIGNAL ;
    PORT
      LAYER M5 ;
        RECT  25.68 17.064 25.704 17.256 ;
    END
  END do0[475]
  PIN do0[476]
    DIRECTION OUTPUT ;
    USE SIGNAL ;
    PORT
      LAYER M5 ;
        RECT  25.728 17.064 25.752 17.256 ;
    END
  END do0[476]
  PIN do0[477]
    DIRECTION OUTPUT ;
    USE SIGNAL ;
    PORT
      LAYER M5 ;
        RECT  25.776 17.064 25.8 17.256 ;
    END
  END do0[477]
  PIN do0[478]
    DIRECTION OUTPUT ;
    USE SIGNAL ;
    PORT
      LAYER M5 ;
        RECT  25.824 17.064 25.848 17.256 ;
    END
  END do0[478]
  PIN do0[479]
    DIRECTION OUTPUT ;
    USE SIGNAL ;
    PORT
      LAYER M5 ;
        RECT  25.872 17.064 25.896 17.256 ;
    END
  END do0[479]
  PIN do0[47]
    DIRECTION OUTPUT ;
    USE SIGNAL ;
    PORT
      LAYER M5 ;
        RECT  5.136 17.064 5.16 17.256 ;
    END
  END do0[47]
  PIN do0[480]
    DIRECTION OUTPUT ;
    USE SIGNAL ;
    PORT
      LAYER M5 ;
        RECT  25.92 17.064 25.944 17.256 ;
    END
  END do0[480]
  PIN do0[481]
    DIRECTION OUTPUT ;
    USE SIGNAL ;
    PORT
      LAYER M5 ;
        RECT  25.968 17.064 25.992 17.256 ;
    END
  END do0[481]
  PIN do0[482]
    DIRECTION OUTPUT ;
    USE SIGNAL ;
    PORT
      LAYER M5 ;
        RECT  26.016 17.064 26.04 17.256 ;
    END
  END do0[482]
  PIN do0[483]
    DIRECTION OUTPUT ;
    USE SIGNAL ;
    PORT
      LAYER M5 ;
        RECT  26.064 17.064 26.088 17.256 ;
    END
  END do0[483]
  PIN do0[484]
    DIRECTION OUTPUT ;
    USE SIGNAL ;
    PORT
      LAYER M5 ;
        RECT  26.112 17.064 26.136 17.256 ;
    END
  END do0[484]
  PIN do0[485]
    DIRECTION OUTPUT ;
    USE SIGNAL ;
    PORT
      LAYER M5 ;
        RECT  26.16 17.064 26.184 17.256 ;
    END
  END do0[485]
  PIN do0[486]
    DIRECTION OUTPUT ;
    USE SIGNAL ;
    PORT
      LAYER M5 ;
        RECT  26.208 17.064 26.232 17.256 ;
    END
  END do0[486]
  PIN do0[487]
    DIRECTION OUTPUT ;
    USE SIGNAL ;
    PORT
      LAYER M5 ;
        RECT  26.256 17.064 26.28 17.256 ;
    END
  END do0[487]
  PIN do0[488]
    DIRECTION OUTPUT ;
    USE SIGNAL ;
    PORT
      LAYER M5 ;
        RECT  26.304 17.064 26.328 17.256 ;
    END
  END do0[488]
  PIN do0[489]
    DIRECTION OUTPUT ;
    USE SIGNAL ;
    PORT
      LAYER M5 ;
        RECT  26.352 17.064 26.376 17.256 ;
    END
  END do0[489]
  PIN do0[48]
    DIRECTION OUTPUT ;
    USE SIGNAL ;
    PORT
      LAYER M5 ;
        RECT  5.184 17.064 5.208 17.256 ;
    END
  END do0[48]
  PIN do0[490]
    DIRECTION OUTPUT ;
    USE SIGNAL ;
    PORT
      LAYER M5 ;
        RECT  26.4 17.064 26.424 17.256 ;
    END
  END do0[490]
  PIN do0[491]
    DIRECTION OUTPUT ;
    USE SIGNAL ;
    PORT
      LAYER M5 ;
        RECT  26.448 17.064 26.472 17.256 ;
    END
  END do0[491]
  PIN do0[492]
    DIRECTION OUTPUT ;
    USE SIGNAL ;
    PORT
      LAYER M5 ;
        RECT  26.496 17.064 26.52 17.256 ;
    END
  END do0[492]
  PIN do0[493]
    DIRECTION OUTPUT ;
    USE SIGNAL ;
    PORT
      LAYER M5 ;
        RECT  26.544 17.064 26.568 17.256 ;
    END
  END do0[493]
  PIN do0[494]
    DIRECTION OUTPUT ;
    USE SIGNAL ;
    PORT
      LAYER M5 ;
        RECT  26.592 17.064 26.616 17.256 ;
    END
  END do0[494]
  PIN do0[495]
    DIRECTION OUTPUT ;
    USE SIGNAL ;
    PORT
      LAYER M5 ;
        RECT  26.64 17.064 26.664 17.256 ;
    END
  END do0[495]
  PIN do0[496]
    DIRECTION OUTPUT ;
    USE SIGNAL ;
    PORT
      LAYER M5 ;
        RECT  26.688 17.064 26.712 17.256 ;
    END
  END do0[496]
  PIN do0[497]
    DIRECTION OUTPUT ;
    USE SIGNAL ;
    PORT
      LAYER M5 ;
        RECT  26.736 17.064 26.76 17.256 ;
    END
  END do0[497]
  PIN do0[498]
    DIRECTION OUTPUT ;
    USE SIGNAL ;
    PORT
      LAYER M5 ;
        RECT  26.784 17.064 26.808 17.256 ;
    END
  END do0[498]
  PIN do0[499]
    DIRECTION OUTPUT ;
    USE SIGNAL ;
    PORT
      LAYER M5 ;
        RECT  26.832 17.064 26.856 17.256 ;
    END
  END do0[499]
  PIN do0[49]
    DIRECTION OUTPUT ;
    USE SIGNAL ;
    PORT
      LAYER M5 ;
        RECT  5.232 17.064 5.256 17.256 ;
    END
  END do0[49]
  PIN do0[4]
    DIRECTION OUTPUT ;
    USE SIGNAL ;
    PORT
      LAYER M5 ;
        RECT  3.072 17.064 3.096 17.256 ;
    END
  END do0[4]
  PIN do0[500]
    DIRECTION OUTPUT ;
    USE SIGNAL ;
    PORT
      LAYER M5 ;
        RECT  26.88 17.064 26.904 17.256 ;
    END
  END do0[500]
  PIN do0[501]
    DIRECTION OUTPUT ;
    USE SIGNAL ;
    PORT
      LAYER M5 ;
        RECT  26.928 17.064 26.952 17.256 ;
    END
  END do0[501]
  PIN do0[502]
    DIRECTION OUTPUT ;
    USE SIGNAL ;
    PORT
      LAYER M5 ;
        RECT  26.976 17.064 27 17.256 ;
    END
  END do0[502]
  PIN do0[503]
    DIRECTION OUTPUT ;
    USE SIGNAL ;
    PORT
      LAYER M5 ;
        RECT  27.024 17.064 27.048 17.256 ;
    END
  END do0[503]
  PIN do0[504]
    DIRECTION OUTPUT ;
    USE SIGNAL ;
    PORT
      LAYER M5 ;
        RECT  27.072 17.064 27.096 17.256 ;
    END
  END do0[504]
  PIN do0[505]
    DIRECTION OUTPUT ;
    USE SIGNAL ;
    PORT
      LAYER M5 ;
        RECT  27.12 17.064 27.144 17.256 ;
    END
  END do0[505]
  PIN do0[506]
    DIRECTION OUTPUT ;
    USE SIGNAL ;
    PORT
      LAYER M5 ;
        RECT  27.168 17.064 27.192 17.256 ;
    END
  END do0[506]
  PIN do0[507]
    DIRECTION OUTPUT ;
    USE SIGNAL ;
    PORT
      LAYER M5 ;
        RECT  27.216 17.064 27.24 17.256 ;
    END
  END do0[507]
  PIN do0[508]
    DIRECTION OUTPUT ;
    USE SIGNAL ;
    PORT
      LAYER M5 ;
        RECT  27.264 17.064 27.288 17.256 ;
    END
  END do0[508]
  PIN do0[509]
    DIRECTION OUTPUT ;
    USE SIGNAL ;
    PORT
      LAYER M5 ;
        RECT  27.312 17.064 27.336 17.256 ;
    END
  END do0[509]
  PIN do0[50]
    DIRECTION OUTPUT ;
    USE SIGNAL ;
    PORT
      LAYER M5 ;
        RECT  5.28 17.064 5.304 17.256 ;
    END
  END do0[50]
  PIN do0[510]
    DIRECTION OUTPUT ;
    USE SIGNAL ;
    PORT
      LAYER M5 ;
        RECT  27.36 17.064 27.384 17.256 ;
    END
  END do0[510]
  PIN do0[511]
    DIRECTION OUTPUT ;
    USE SIGNAL ;
    PORT
      LAYER M5 ;
        RECT  27.408 17.064 27.432 17.256 ;
    END
  END do0[511]
  PIN do0[512]
    DIRECTION OUTPUT ;
    USE SIGNAL ;
    PORT
      LAYER M5 ;
        RECT  27.456 17.064 27.48 17.256 ;
    END
  END do0[512]
  PIN do0[513]
    DIRECTION OUTPUT ;
    USE SIGNAL ;
    PORT
      LAYER M5 ;
        RECT  27.504 17.064 27.528 17.256 ;
    END
  END do0[513]
  PIN do0[51]
    DIRECTION OUTPUT ;
    USE SIGNAL ;
    PORT
      LAYER M5 ;
        RECT  5.328 17.064 5.352 17.256 ;
    END
  END do0[51]
  PIN do0[52]
    DIRECTION OUTPUT ;
    USE SIGNAL ;
    PORT
      LAYER M5 ;
        RECT  5.376 17.064 5.4 17.256 ;
    END
  END do0[52]
  PIN do0[53]
    DIRECTION OUTPUT ;
    USE SIGNAL ;
    PORT
      LAYER M5 ;
        RECT  5.424 17.064 5.448 17.256 ;
    END
  END do0[53]
  PIN do0[54]
    DIRECTION OUTPUT ;
    USE SIGNAL ;
    PORT
      LAYER M5 ;
        RECT  5.472 17.064 5.496 17.256 ;
    END
  END do0[54]
  PIN do0[55]
    DIRECTION OUTPUT ;
    USE SIGNAL ;
    PORT
      LAYER M5 ;
        RECT  5.52 17.064 5.544 17.256 ;
    END
  END do0[55]
  PIN do0[56]
    DIRECTION OUTPUT ;
    USE SIGNAL ;
    PORT
      LAYER M5 ;
        RECT  5.568 17.064 5.592 17.256 ;
    END
  END do0[56]
  PIN do0[57]
    DIRECTION OUTPUT ;
    USE SIGNAL ;
    PORT
      LAYER M5 ;
        RECT  5.616 17.064 5.64 17.256 ;
    END
  END do0[57]
  PIN do0[58]
    DIRECTION OUTPUT ;
    USE SIGNAL ;
    PORT
      LAYER M5 ;
        RECT  5.664 17.064 5.688 17.256 ;
    END
  END do0[58]
  PIN do0[59]
    DIRECTION OUTPUT ;
    USE SIGNAL ;
    PORT
      LAYER M5 ;
        RECT  5.712 17.064 5.736 17.256 ;
    END
  END do0[59]
  PIN do0[5]
    DIRECTION OUTPUT ;
    USE SIGNAL ;
    PORT
      LAYER M5 ;
        RECT  3.12 17.064 3.144 17.256 ;
    END
  END do0[5]
  PIN do0[60]
    DIRECTION OUTPUT ;
    USE SIGNAL ;
    PORT
      LAYER M5 ;
        RECT  5.76 17.064 5.784 17.256 ;
    END
  END do0[60]
  PIN do0[61]
    DIRECTION OUTPUT ;
    USE SIGNAL ;
    PORT
      LAYER M5 ;
        RECT  5.808 17.064 5.832 17.256 ;
    END
  END do0[61]
  PIN do0[62]
    DIRECTION OUTPUT ;
    USE SIGNAL ;
    PORT
      LAYER M5 ;
        RECT  5.856 17.064 5.88 17.256 ;
    END
  END do0[62]
  PIN do0[63]
    DIRECTION OUTPUT ;
    USE SIGNAL ;
    PORT
      LAYER M5 ;
        RECT  5.904 17.064 5.928 17.256 ;
    END
  END do0[63]
  PIN do0[64]
    DIRECTION OUTPUT ;
    USE SIGNAL ;
    PORT
      LAYER M5 ;
        RECT  5.952 17.064 5.976 17.256 ;
    END
  END do0[64]
  PIN do0[65]
    DIRECTION OUTPUT ;
    USE SIGNAL ;
    PORT
      LAYER M5 ;
        RECT  6 17.064 6.024 17.256 ;
    END
  END do0[65]
  PIN do0[66]
    DIRECTION OUTPUT ;
    USE SIGNAL ;
    PORT
      LAYER M5 ;
        RECT  6.048 17.064 6.072 17.256 ;
    END
  END do0[66]
  PIN do0[67]
    DIRECTION OUTPUT ;
    USE SIGNAL ;
    PORT
      LAYER M5 ;
        RECT  6.096 17.064 6.12 17.256 ;
    END
  END do0[67]
  PIN do0[68]
    DIRECTION OUTPUT ;
    USE SIGNAL ;
    PORT
      LAYER M5 ;
        RECT  6.144 17.064 6.168 17.256 ;
    END
  END do0[68]
  PIN do0[69]
    DIRECTION OUTPUT ;
    USE SIGNAL ;
    PORT
      LAYER M5 ;
        RECT  6.192 17.064 6.216 17.256 ;
    END
  END do0[69]
  PIN do0[6]
    DIRECTION OUTPUT ;
    USE SIGNAL ;
    PORT
      LAYER M5 ;
        RECT  3.168 17.064 3.192 17.256 ;
    END
  END do0[6]
  PIN do0[70]
    DIRECTION OUTPUT ;
    USE SIGNAL ;
    PORT
      LAYER M5 ;
        RECT  6.24 17.064 6.264 17.256 ;
    END
  END do0[70]
  PIN do0[71]
    DIRECTION OUTPUT ;
    USE SIGNAL ;
    PORT
      LAYER M5 ;
        RECT  6.288 17.064 6.312 17.256 ;
    END
  END do0[71]
  PIN do0[72]
    DIRECTION OUTPUT ;
    USE SIGNAL ;
    PORT
      LAYER M5 ;
        RECT  6.336 17.064 6.36 17.256 ;
    END
  END do0[72]
  PIN do0[73]
    DIRECTION OUTPUT ;
    USE SIGNAL ;
    PORT
      LAYER M5 ;
        RECT  6.384 17.064 6.408 17.256 ;
    END
  END do0[73]
  PIN do0[74]
    DIRECTION OUTPUT ;
    USE SIGNAL ;
    PORT
      LAYER M5 ;
        RECT  6.432 17.064 6.456 17.256 ;
    END
  END do0[74]
  PIN do0[75]
    DIRECTION OUTPUT ;
    USE SIGNAL ;
    PORT
      LAYER M5 ;
        RECT  6.48 17.064 6.504 17.256 ;
    END
  END do0[75]
  PIN do0[76]
    DIRECTION OUTPUT ;
    USE SIGNAL ;
    PORT
      LAYER M5 ;
        RECT  6.528 17.064 6.552 17.256 ;
    END
  END do0[76]
  PIN do0[77]
    DIRECTION OUTPUT ;
    USE SIGNAL ;
    PORT
      LAYER M5 ;
        RECT  6.576 17.064 6.6 17.256 ;
    END
  END do0[77]
  PIN do0[78]
    DIRECTION OUTPUT ;
    USE SIGNAL ;
    PORT
      LAYER M5 ;
        RECT  6.624 17.064 6.648 17.256 ;
    END
  END do0[78]
  PIN do0[79]
    DIRECTION OUTPUT ;
    USE SIGNAL ;
    PORT
      LAYER M5 ;
        RECT  6.672 17.064 6.696 17.256 ;
    END
  END do0[79]
  PIN do0[7]
    DIRECTION OUTPUT ;
    USE SIGNAL ;
    PORT
      LAYER M5 ;
        RECT  3.216 17.064 3.24 17.256 ;
    END
  END do0[7]
  PIN do0[80]
    DIRECTION OUTPUT ;
    USE SIGNAL ;
    PORT
      LAYER M5 ;
        RECT  6.72 17.064 6.744 17.256 ;
    END
  END do0[80]
  PIN do0[81]
    DIRECTION OUTPUT ;
    USE SIGNAL ;
    PORT
      LAYER M5 ;
        RECT  6.768 17.064 6.792 17.256 ;
    END
  END do0[81]
  PIN do0[82]
    DIRECTION OUTPUT ;
    USE SIGNAL ;
    PORT
      LAYER M5 ;
        RECT  6.816 17.064 6.84 17.256 ;
    END
  END do0[82]
  PIN do0[83]
    DIRECTION OUTPUT ;
    USE SIGNAL ;
    PORT
      LAYER M5 ;
        RECT  6.864 17.064 6.888 17.256 ;
    END
  END do0[83]
  PIN do0[84]
    DIRECTION OUTPUT ;
    USE SIGNAL ;
    PORT
      LAYER M5 ;
        RECT  6.912 17.064 6.936 17.256 ;
    END
  END do0[84]
  PIN do0[85]
    DIRECTION OUTPUT ;
    USE SIGNAL ;
    PORT
      LAYER M5 ;
        RECT  6.96 17.064 6.984 17.256 ;
    END
  END do0[85]
  PIN do0[86]
    DIRECTION OUTPUT ;
    USE SIGNAL ;
    PORT
      LAYER M5 ;
        RECT  7.008 17.064 7.032 17.256 ;
    END
  END do0[86]
  PIN do0[87]
    DIRECTION OUTPUT ;
    USE SIGNAL ;
    PORT
      LAYER M5 ;
        RECT  7.056 17.064 7.08 17.256 ;
    END
  END do0[87]
  PIN do0[88]
    DIRECTION OUTPUT ;
    USE SIGNAL ;
    PORT
      LAYER M5 ;
        RECT  7.104 17.064 7.128 17.256 ;
    END
  END do0[88]
  PIN do0[89]
    DIRECTION OUTPUT ;
    USE SIGNAL ;
    PORT
      LAYER M5 ;
        RECT  7.152 17.064 7.176 17.256 ;
    END
  END do0[89]
  PIN do0[8]
    DIRECTION OUTPUT ;
    USE SIGNAL ;
    PORT
      LAYER M5 ;
        RECT  3.264 17.064 3.288 17.256 ;
    END
  END do0[8]
  PIN do0[90]
    DIRECTION OUTPUT ;
    USE SIGNAL ;
    PORT
      LAYER M5 ;
        RECT  7.2 17.064 7.224 17.256 ;
    END
  END do0[90]
  PIN do0[91]
    DIRECTION OUTPUT ;
    USE SIGNAL ;
    PORT
      LAYER M5 ;
        RECT  7.248 17.064 7.272 17.256 ;
    END
  END do0[91]
  PIN do0[92]
    DIRECTION OUTPUT ;
    USE SIGNAL ;
    PORT
      LAYER M5 ;
        RECT  7.296 17.064 7.32 17.256 ;
    END
  END do0[92]
  PIN do0[93]
    DIRECTION OUTPUT ;
    USE SIGNAL ;
    PORT
      LAYER M5 ;
        RECT  7.344 17.064 7.368 17.256 ;
    END
  END do0[93]
  PIN do0[94]
    DIRECTION OUTPUT ;
    USE SIGNAL ;
    PORT
      LAYER M5 ;
        RECT  7.392 17.064 7.416 17.256 ;
    END
  END do0[94]
  PIN do0[95]
    DIRECTION OUTPUT ;
    USE SIGNAL ;
    PORT
      LAYER M5 ;
        RECT  7.44 17.064 7.464 17.256 ;
    END
  END do0[95]
  PIN do0[96]
    DIRECTION OUTPUT ;
    USE SIGNAL ;
    PORT
      LAYER M5 ;
        RECT  7.488 17.064 7.512 17.256 ;
    END
  END do0[96]
  PIN do0[97]
    DIRECTION OUTPUT ;
    USE SIGNAL ;
    PORT
      LAYER M5 ;
        RECT  7.536 17.064 7.56 17.256 ;
    END
  END do0[97]
  PIN do0[98]
    DIRECTION OUTPUT ;
    USE SIGNAL ;
    PORT
      LAYER M5 ;
        RECT  7.584 17.064 7.608 17.256 ;
    END
  END do0[98]
  PIN do0[99]
    DIRECTION OUTPUT ;
    USE SIGNAL ;
    PORT
      LAYER M5 ;
        RECT  7.632 17.064 7.656 17.256 ;
    END
  END do0[99]
  PIN do0[9]
    DIRECTION OUTPUT ;
    USE SIGNAL ;
    PORT
      LAYER M5 ;
        RECT  3.312 17.064 3.336 17.256 ;
    END
  END do0[9]
  PIN fi0[0]
    DIRECTION INPUT ;
    USE SIGNAL ;
    PORT
      LAYER M5 ;
        RECT  2.688 0 2.712 0.192 ;
    END
  END fi0[0]
  PIN fo0[0]
    DIRECTION OUTPUT ;
    USE SIGNAL ;
    PORT
      LAYER M5 ;
        RECT  2.688 17.064 2.712 17.256 ;
    END
  END fo0[0]
  PIN VDD
    DIRECTION INOUT ;
    USE POWER ;
    PORT
      LAYER M7 ;
        RECT  27.856 0.531 28.144 16.479 ;
        RECT  17.056 0.531 17.344 16.479 ;
        RECT  6.256 0.531 6.544 16.479 ;
      LAYER M6 ;
        RECT  0 12.372 0.032 12.66 ;
        RECT  0 6.972 0.032 7.26 ;
        RECT  0 1.572 0.032 1.86 ;
      LAYER M2 ;
        RECT  0 16.461 0.018 16.479 ;
        RECT  0 15.921 0.018 15.939 ;
        RECT  0 15.381 0.018 15.399 ;
        RECT  0 14.841 0.018 14.859 ;
        RECT  0 14.301 0.018 14.319 ;
        RECT  0 13.761 0.018 13.779 ;
        RECT  0 13.221 0.018 13.239 ;
        RECT  0 12.681 0.018 12.699 ;
        RECT  0 12.141 0.018 12.159 ;
        RECT  0 11.601 0.018 11.619 ;
        RECT  0 11.061 0.018 11.079 ;
        RECT  0 10.521 0.018 10.539 ;
        RECT  0 9.981 0.018 9.999 ;
        RECT  0 9.441 0.018 9.459 ;
        RECT  0 8.901 0.018 8.919 ;
        RECT  0 8.361 0.018 8.379 ;
        RECT  0 7.821 0.018 7.839 ;
        RECT  0 7.281 0.018 7.299 ;
        RECT  0 6.741 0.018 6.759 ;
        RECT  0 6.201 0.018 6.219 ;
        RECT  0 5.661 0.018 5.679 ;
        RECT  0 5.121 0.018 5.139 ;
        RECT  0 4.581 0.018 4.599 ;
        RECT  0 4.041 0.018 4.059 ;
        RECT  0 3.501 0.018 3.519 ;
        RECT  0 2.961 0.018 2.979 ;
        RECT  0 2.421 0.018 2.439 ;
        RECT  0 1.881 0.018 1.899 ;
        RECT  0 1.341 0.018 1.359 ;
        RECT  0 0.801 0.018 0.819 ;
      LAYER M1 ;
        RECT  0 16.461 0.018 16.479 ;
        RECT  0 15.921 0.018 15.939 ;
        RECT  0 15.381 0.018 15.399 ;
        RECT  0 14.841 0.018 14.859 ;
        RECT  0 14.301 0.018 14.319 ;
        RECT  0 13.761 0.018 13.779 ;
        RECT  0 13.221 0.018 13.239 ;
        RECT  0 12.681 0.018 12.699 ;
        RECT  0 12.141 0.018 12.159 ;
        RECT  0 11.601 0.018 11.619 ;
        RECT  0 11.061 0.018 11.079 ;
        RECT  0 10.521 0.018 10.539 ;
        RECT  0 9.981 0.018 9.999 ;
        RECT  0 9.441 0.018 9.459 ;
        RECT  0 8.901 0.018 8.919 ;
        RECT  0 8.361 0.018 8.379 ;
        RECT  0 7.821 0.018 7.839 ;
        RECT  0 7.281 0.018 7.299 ;
        RECT  0 6.741 0.018 6.759 ;
        RECT  0 6.201 0.018 6.219 ;
        RECT  0 5.661 0.018 5.679 ;
        RECT  0 5.121 0.018 5.139 ;
        RECT  0 4.581 0.018 4.599 ;
        RECT  0 4.041 0.018 4.059 ;
        RECT  0 3.501 0.018 3.519 ;
        RECT  0 2.961 0.018 2.979 ;
        RECT  0 2.421 0.018 2.439 ;
        RECT  0 1.881 0.018 1.899 ;
        RECT  0 1.341 0.018 1.359 ;
        RECT  0 0.801 0.018 0.819 ;
    END
  END VDD
  PIN VSS
    DIRECTION INOUT ;
    USE GROUND ;
    PORT
      LAYER M7 ;
        RECT  22.456 0.531 22.744 16.479 ;
        RECT  11.656 0.531 11.944 16.479 ;
        RECT  0.856 0.531 1.144 16.479 ;
      LAYER M6 ;
        RECT  0 11.796 0.032 12.084 ;
        RECT  0 6.396 0.032 6.684 ;
        RECT  0 0.996 0.032 1.284 ;
      LAYER M2 ;
        RECT  0 16.191 0.018 16.209 ;
        RECT  0 15.651 0.018 15.669 ;
        RECT  0 15.111 0.018 15.129 ;
        RECT  0 14.571 0.018 14.589 ;
        RECT  0 14.031 0.018 14.049 ;
        RECT  0 13.491 0.018 13.509 ;
        RECT  0 12.951 0.018 12.969 ;
        RECT  0 12.411 0.018 12.429 ;
        RECT  0 11.871 0.018 11.889 ;
        RECT  0 11.331 0.018 11.349 ;
        RECT  0 10.791 0.018 10.809 ;
        RECT  0 10.251 0.018 10.269 ;
        RECT  0 9.711 0.018 9.729 ;
        RECT  0 9.171 0.018 9.189 ;
        RECT  0 8.631 0.018 8.649 ;
        RECT  0 8.091 0.018 8.109 ;
        RECT  0 7.551 0.018 7.569 ;
        RECT  0 7.011 0.018 7.029 ;
        RECT  0 6.471 0.018 6.489 ;
        RECT  0 5.931 0.018 5.949 ;
        RECT  0 5.391 0.018 5.409 ;
        RECT  0 4.851 0.018 4.869 ;
        RECT  0 4.311 0.018 4.329 ;
        RECT  0 3.771 0.018 3.789 ;
        RECT  0 3.231 0.018 3.249 ;
        RECT  0 2.691 0.018 2.709 ;
        RECT  0 2.151 0.018 2.169 ;
        RECT  0 1.611 0.018 1.629 ;
        RECT  0 1.071 0.018 1.089 ;
        RECT  0 0.531 0.018 0.549 ;
      LAYER M1 ;
        RECT  0 16.191 0.018 16.209 ;
        RECT  0 15.651 0.018 15.669 ;
        RECT  0 15.111 0.018 15.129 ;
        RECT  0 14.571 0.018 14.589 ;
        RECT  0 14.031 0.018 14.049 ;
        RECT  0 13.491 0.018 13.509 ;
        RECT  0 12.951 0.018 12.969 ;
        RECT  0 12.411 0.018 12.429 ;
        RECT  0 11.871 0.018 11.889 ;
        RECT  0 11.331 0.018 11.349 ;
        RECT  0 10.791 0.018 10.809 ;
        RECT  0 10.251 0.018 10.269 ;
        RECT  0 9.711 0.018 9.729 ;
        RECT  0 9.171 0.018 9.189 ;
        RECT  0 8.631 0.018 8.649 ;
        RECT  0 8.091 0.018 8.109 ;
        RECT  0 7.551 0.018 7.569 ;
        RECT  0 7.011 0.018 7.029 ;
        RECT  0 6.471 0.018 6.489 ;
        RECT  0 5.931 0.018 5.949 ;
        RECT  0 5.391 0.018 5.409 ;
        RECT  0 4.851 0.018 4.869 ;
        RECT  0 4.311 0.018 4.329 ;
        RECT  0 3.771 0.018 3.789 ;
        RECT  0 3.231 0.018 3.249 ;
        RECT  0 2.691 0.018 2.709 ;
        RECT  0 2.151 0.018 2.169 ;
        RECT  0 1.611 0.018 1.629 ;
        RECT  0 1.071 0.018 1.089 ;
        RECT  0 0.531 0.018 0.549 ;
    END
  END VSS
  OBS
    LAYER RVTN ;
     RECT  0 0.54 30.186 0.675 ;
     RECT  0 0.945 30.186 1.215 ;
     RECT  0 1.485 30.186 1.755 ;
     RECT  0 2.025 30.186 2.295 ;
     RECT  0 2.565 30.186 2.835 ;
     RECT  0 3.105 30.186 3.375 ;
     RECT  0 3.645 30.186 3.915 ;
     RECT  0 4.185 30.186 4.455 ;
     RECT  0 4.725 30.186 4.995 ;
     RECT  0 5.265 30.186 5.535 ;
     RECT  0 5.805 30.186 6.075 ;
     RECT  0 6.345 30.186 6.615 ;
     RECT  0 6.885 30.186 7.155 ;
     RECT  0 7.425 30.186 7.695 ;
     RECT  0 7.965 30.186 8.235 ;
     RECT  0 8.505 30.186 8.775 ;
     RECT  0 9.045 30.186 9.315 ;
     RECT  0 9.585 30.186 9.855 ;
     RECT  0 10.125 30.186 10.395 ;
     RECT  0 10.665 30.186 10.935 ;
     RECT  0 11.205 30.186 11.475 ;
     RECT  0 11.745 30.186 12.015 ;
     RECT  0 12.285 30.186 12.555 ;
     RECT  0 12.825 30.186 13.095 ;
     RECT  0 13.365 30.186 13.635 ;
     RECT  0 13.905 30.186 14.175 ;
     RECT  0 14.445 30.186 14.715 ;
     RECT  0 14.985 30.186 15.255 ;
     RECT  0 15.525 30.186 15.795 ;
     RECT  0 16.065 30.186 16.335 ;
    LAYER RVTP ;
     RECT  0 0.675 30.186 0.945 ;
     RECT  0 1.215 30.186 1.485 ;
     RECT  0 1.755 30.186 2.025 ;
     RECT  0 2.295 30.186 2.565 ;
     RECT  0 2.835 30.186 3.105 ;
     RECT  0 3.375 30.186 3.645 ;
     RECT  0 3.915 30.186 4.185 ;
     RECT  0 4.455 30.186 4.725 ;
     RECT  0 4.995 30.186 5.265 ;
     RECT  0 5.535 30.186 5.805 ;
     RECT  0 6.075 30.186 6.345 ;
     RECT  0 6.615 30.186 6.885 ;
     RECT  0 7.155 30.186 7.425 ;
     RECT  0 7.695 30.186 7.965 ;
     RECT  0 8.235 30.186 8.505 ;
     RECT  0 8.775 30.186 9.045 ;
     RECT  0 9.315 30.186 9.585 ;
     RECT  0 9.855 30.186 10.125 ;
     RECT  0 10.395 30.186 10.665 ;
     RECT  0 10.935 30.186 11.205 ;
     RECT  0 11.475 30.186 11.745 ;
     RECT  0 12.015 30.186 12.285 ;
     RECT  0 12.555 30.186 12.825 ;
     RECT  0 13.095 30.186 13.365 ;
     RECT  0 13.635 30.186 13.905 ;
     RECT  0 14.175 30.186 14.445 ;
     RECT  0 14.715 30.186 14.985 ;
     RECT  0 15.255 30.186 15.525 ;
     RECT  0 15.795 30.186 16.065 ;
     RECT  0 16.335 30.186 16.47 ;
    LAYER M1 ;
     RECT  0 0.531 30.186 16.479 ;
    LAYER M2 ;
     RECT  0 0.531 1.975 16.479 ;
     RECT  1.975 0.036 3.451 16.479 ;
     RECT  3.451 0.036 4.055 16.524 ;
     RECT  4.055 0.108 4.127 16.524 ;
     RECT  4.127 0.108 5.071 16.479 ;
     RECT  5.071 0.036 6.323 16.479 ;
     RECT  6.323 0.306 6.503 16.479 ;
     RECT  6.503 0.486 6.755 16.479 ;
     RECT  6.755 0.531 10.687 16.479 ;
     RECT  10.687 0.414 11.291 16.479 ;
     RECT  11.291 0.486 11.399 16.479 ;
     RECT  11.399 0.531 15.367 16.479 ;
     RECT  15.367 0.531 15.791 16.524 ;
     RECT  15.791 0.531 16.303 16.479 ;
     RECT  16.303 0.486 16.655 16.479 ;
     RECT  16.655 0.531 27.319 16.479 ;
     RECT  27.319 0.531 27.779 16.524 ;
     RECT  27.779 0.531 30.186 16.479 ;
    LAYER M3 ;
     RECT  4.032 0.031 4.05 0.043 ;
     RECT  5.076 0.031 5.094 0.043 ;
     RECT  1.98 0.031 1.998 0.091 ;
     RECT  3.852 0.043 4.05 0.091 ;
     RECT  5.076 0.043 5.418 0.091 ;
     RECT  6.3 0.031 6.318 0.091 ;
     RECT  3.852 0.091 4.086 0.103 ;
     RECT  3.312 0.103 4.086 0.139 ;
     RECT  5.076 0.091 6.318 0.139 ;
     RECT  7.128 0.091 7.146 0.139 ;
     RECT  2.916 0.139 7.506 0.187 ;
     RECT  8.496 0.139 8.514 0.187 ;
     RECT  16.236 0.139 16.65 0.187 ;
     RECT  27 0.091 27.342 0.187 ;
     RECT  10.836 0.187 10.854 0.235 ;
     RECT  16.236 0.187 16.938 0.235 ;
     RECT  2.736 0.187 8.514 0.283 ;
     RECT  10.224 0.235 11.106 0.283 ;
     RECT  14.508 0.187 15.246 0.283 ;
     RECT  16.2 0.235 16.938 0.283 ;
     RECT  18.828 0.187 18.846 0.283 ;
     RECT  21.276 0.187 21.294 0.283 ;
     RECT  23.04 0.187 23.382 0.283 ;
     RECT  24.336 0.187 24.462 0.283 ;
     RECT  26.352 0.187 27.342 0.283 ;
     RECT  1.908 0.091 1.998 0.331 ;
     RECT  2.736 0.283 9.342 0.331 ;
     RECT  10.08 0.283 13.23 0.331 ;
     RECT  14.04 0.283 18.09 0.331 ;
     RECT  18.828 0.283 20.07 0.331 ;
     RECT  20.916 0.283 22.266 0.331 ;
     RECT  23.04 0.283 24.462 0.331 ;
     RECT  25.416 0.283 27.414 0.331 ;
     RECT  1.908 0.331 9.342 0.427 ;
     RECT  10.08 0.331 18.09 0.427 ;
     RECT  1.692 0.427 18.09 0.523 ;
     RECT  18.828 0.331 22.266 0.523 ;
     RECT  23.04 0.331 27.666 0.523 ;
     RECT  1.476 0.523 27.666 0.667 ;
     RECT  1.476 0.667 27.738 0.751 ;
     RECT  28.476 0.379 28.494 0.751 ;
     RECT  0.255 0.523 0.345 0.793 ;
     RECT  1.476 0.751 28.998 1.099 ;
     RECT  1.476 1.099 29.718 1.139 ;
     RECT  0.255 0.793 0.537 1.831 ;
     RECT  1.476 1.139 28.818 1.831 ;
     RECT  0.255 1.831 28.818 2.191 ;
     RECT  0.255 2.191 29.286 2.237 ;
     RECT  0.255 2.237 29.214 2.633 ;
     RECT  1.476 2.633 29.214 3.181 ;
     RECT  1.476 3.181 29.286 3.389 ;
     RECT  1.476 3.389 28.71 3.773 ;
     RECT  29.376 4.507 29.394 4.559 ;
     RECT  1.476 3.773 28.458 4.801 ;
     RECT  1.476 4.801 29.142 4.877 ;
     RECT  1.476 4.877 28.638 5.369 ;
     RECT  1.476 5.369 28.278 5.729 ;
     RECT  1.476 5.729 27.954 5.933 ;
     RECT  29.016 5.881 29.034 5.933 ;
     RECT  1.476 5.933 27.846 6.961 ;
     RECT  1.476 6.961 28.062 7.393 ;
     RECT  29.016 7.435 29.034 7.933 ;
     RECT  29.016 7.933 29.142 8.195 ;
     RECT  29.016 8.195 29.106 8.381 ;
     RECT  1.476 7.393 28.17 8.491 ;
     RECT  1.476 8.491 28.854 8.537 ;
     RECT  1.476 8.537 28.386 8.707 ;
     RECT  1.44 8.707 28.386 9.113 ;
     RECT  1.728 9.113 28.386 9.661 ;
     RECT  1.728 9.661 28.494 9.689 ;
     RECT  1.98 9.689 28.494 9.931 ;
     RECT  1.98 9.931 28.602 10.987 ;
     RECT  1.98 10.987 28.71 11.011 ;
     RECT  1.764 11.011 28.71 11.365 ;
     RECT  1.764 11.365 29.106 11.405 ;
     RECT  1.764 11.405 28.602 11.407 ;
     RECT  1.512 11.407 28.602 11.669 ;
     RECT  1.98 11.669 28.602 11.975 ;
     RECT  2.088 11.975 28.602 12.901 ;
     RECT  1.728 12.901 28.602 13.595 ;
     RECT  2.088 13.595 28.602 14.299 ;
     RECT  2.088 14.299 28.782 14.521 ;
     RECT  1.872 14.521 28.782 14.875 ;
     RECT  1.872 14.875 28.926 15.179 ;
     RECT  1.872 15.179 28.89 15.719 ;
     RECT  2.304 15.719 28.89 16.027 ;
     RECT  2.304 16.027 28.998 16.141 ;
     RECT  2.304 16.141 29.106 16.205 ;
     RECT  0.255 2.633 0.537 16.217 ;
     RECT  2.304 16.205 28.998 16.259 ;
     RECT  2.484 16.259 28.854 16.295 ;
     RECT  2.772 16.295 28.854 16.439 ;
     RECT  28.764 16.439 28.782 16.445 ;
     RECT  0.447 16.217 0.537 16.487 ;
     RECT  2.772 16.439 27.918 16.493 ;
     RECT  2.772 16.493 23.922 16.589 ;
     RECT  24.84 16.493 27.918 16.589 ;
     RECT  2.772 16.589 19.638 16.637 ;
     RECT  27.18 16.589 27.918 16.637 ;
     RECT  2.772 16.637 17.082 16.685 ;
     RECT  17.856 16.637 19.062 16.685 ;
     RECT  21.024 16.589 22.482 16.685 ;
     RECT  23.22 16.589 23.31 16.685 ;
     RECT  25.236 16.589 25.254 16.685 ;
     RECT  26.172 16.589 26.226 16.685 ;
     RECT  2.772 16.685 9.81 16.733 ;
     RECT  13.716 16.685 13.734 16.733 ;
     RECT  15.012 16.685 15.354 16.733 ;
     RECT  16.488 16.685 17.082 16.733 ;
     RECT  17.856 16.685 18.234 16.733 ;
     RECT  19.044 16.685 19.062 16.733 ;
     RECT  21.564 16.685 22.266 16.733 ;
     RECT  23.22 16.685 23.238 16.733 ;
     RECT  27.576 16.637 27.918 16.733 ;
     RECT  2.772 16.733 5.238 16.781 ;
     RECT  7.092 16.733 8.082 16.781 ;
     RECT  10.656 16.685 12.294 16.781 ;
     RECT  26.172 16.685 26.19 16.781 ;
     RECT  6.12 16.733 6.246 16.829 ;
     RECT  7.74 16.781 8.082 16.829 ;
     RECT  11.016 16.781 12.294 16.829 ;
     RECT  21.78 16.733 22.266 16.829 ;
     RECT  27.576 16.733 27.594 16.829 ;
     RECT  2.844 16.781 5.166 16.877 ;
     RECT  22.176 16.829 22.266 16.877 ;
     RECT  11.412 16.829 12.294 16.925 ;
     RECT  22.248 16.877 22.266 16.925 ;
     RECT  3.384 16.877 4.41 16.973 ;
     RECT  5.148 16.877 5.166 16.973 ;
     RECT  6.12 16.829 6.138 16.973 ;
     RECT  8.064 16.829 8.082 16.973 ;
     RECT  11.736 16.925 12.294 16.973 ;
     RECT  16.884 16.733 16.902 17.069 ;
    LAYER M4 ;
     RECT  0.248 0.528 0.352 16.212 ;
     RECT  0.352 0.798 0.44 16.212 ;
     RECT  0.44 0.798 0.544 16.482 ;
     RECT  1.465 0.528 1.681 0.552 ;
     RECT  1.681 0.432 1.897 0.552 ;
     RECT  2.108 2.256 2.113 2.28 ;
     RECT  2.077 13.68 2.161 13.704 ;
     RECT  2.113 1.68 2.195 2.28 ;
     RECT  1.897 0.096 2.293 0.552 ;
     RECT  2.185 9.792 2.293 9.816 ;
     RECT  2.195 1.68 2.3 1.704 ;
     RECT  2.293 9.216 2.321 9.816 ;
     RECT  2.293 0.096 2.348 0.648 ;
     RECT  2.3 1.632 2.348 1.704 ;
     RECT  2.329 16.176 2.357 16.2 ;
     RECT  2.321 9.072 2.405 9.816 ;
     RECT  2.113 12.192 2.545 12.216 ;
     RECT  2.405 9.216 2.549 9.816 ;
     RECT  2.533 7.872 2.581 7.896 ;
     RECT  2.54 2.688 2.684 2.712 ;
     RECT  2.357 14.88 2.725 14.904 ;
     RECT  2.357 15.984 2.725 16.2 ;
     RECT  2.725 14.88 2.761 16.2 ;
     RECT  2.653 10.848 2.771 10.872 ;
     RECT  2.761 14.88 2.833 16.776 ;
     RECT  2.684 2.688 2.861 3.336 ;
     RECT  2.293 6.528 2.876 6.552 ;
     RECT  2.581 7.872 2.876 8.088 ;
     RECT  2.861 2.688 2.905 3.96 ;
     RECT  2.869 5.136 2.905 5.16 ;
     RECT  2.876 6.528 2.963 8.088 ;
     RECT  2.963 6.528 2.965 6.984 ;
     RECT  2.905 2.688 3.107 5.16 ;
     RECT  2.965 6.192 3.119 6.984 ;
     RECT  2.545 12.192 3.157 12.264 ;
     RECT  2.833 13.968 3.157 16.872 ;
     RECT  2.348 0.096 3.164 1.704 ;
     RECT  3.107 2.688 3.164 5.112 ;
     RECT  3.119 6.144 3.203 6.984 ;
     RECT  3.164 0.096 3.251 5.112 ;
     RECT  3.157 13.68 3.373 16.872 ;
     RECT  2.549 9.792 3.413 9.816 ;
     RECT  3.373 13.68 3.493 16.968 ;
     RECT  2.963 8.064 3.521 8.088 ;
     RECT  3.157 11.472 3.629 12.264 ;
     RECT  3.493 13.584 3.685 16.968 ;
     RECT  3.251 0.096 3.841 1.704 ;
     RECT  3.925 11.376 4.012 11.4 ;
     RECT  3.251 2.688 4.261 5.112 ;
     RECT  3.203 6.144 4.261 6.216 ;
     RECT  3.841 0.048 4.268 1.704 ;
     RECT  4.261 2.688 4.268 6.216 ;
     RECT  4.268 0.048 4.348 6.216 ;
     RECT  4.345 8.304 4.525 8.328 ;
     RECT  4.525 7.776 4.549 8.328 ;
     RECT  4.357 10.32 4.561 10.344 ;
     RECT  4.549 6.72 4.669 8.328 ;
     RECT  4.669 6.72 5.021 9.288 ;
     RECT  4.561 10.32 5.021 11.304 ;
     RECT  5.021 6.72 5.353 11.304 ;
     RECT  4.348 0.048 5.372 5.16 ;
     RECT  5.353 6.72 5.372 11.448 ;
     RECT  5.372 0.048 5.429 11.448 ;
     RECT  5.429 0.096 5.648 11.448 ;
     RECT  3.685 12.528 5.648 16.968 ;
     RECT  5.648 0.096 5.944 16.968 ;
     RECT  5.944 12.192 6.083 16.968 ;
     RECT  5.944 0.096 6.131 7.992 ;
     RECT  6.131 0.096 6.227 7.944 ;
     RECT  6.227 5.904 6.268 7.944 ;
     RECT  5.944 9.696 6.275 10.968 ;
     RECT  6.083 14.784 6.323 16.968 ;
     RECT  6.323 14.784 6.509 16.776 ;
     RECT  6.083 13.68 6.611 13.704 ;
     RECT  6.275 9.696 7.045 10.872 ;
     RECT  6.227 0.096 7.139 4.584 ;
     RECT  6.083 12.192 7.153 12.552 ;
     RECT  7.139 0.096 7.157 4.056 ;
     RECT  7.157 0.144 7.229 4.056 ;
     RECT  7.229 0.144 7.235 2.808 ;
     RECT  6.268 7.92 7.237 7.944 ;
     RECT  7.045 9.072 7.237 10.872 ;
     RECT  7.237 7.92 7.325 10.872 ;
     RECT  7.153 12 7.325 12.552 ;
     RECT  7.325 7.92 7.337 12.552 ;
     RECT  6.268 5.904 7.379 6.888 ;
     RECT  7.379 5.904 7.429 6.84 ;
     RECT  7.337 7.92 7.445 7.944 ;
     RECT  7.337 9.072 7.475 12.552 ;
     RECT  7.429 5.616 7.516 6.84 ;
     RECT  7.477 14.256 7.685 14.28 ;
     RECT  6.509 15.408 7.685 16.776 ;
     RECT  7.685 14.256 7.729 16.776 ;
     RECT  7.729 14.256 7.837 16.824 ;
     RECT  7.475 12.528 8.017 12.552 ;
     RECT  7.837 13.68 8.017 16.824 ;
     RECT  8.017 12.528 8.053 16.824 ;
     RECT  7.229 3.984 8.195 4.056 ;
     RECT  8.053 12.528 8.195 16.968 ;
     RECT  7.475 9.072 8.236 11.4 ;
     RECT  7.235 0.144 8.245 1.224 ;
     RECT  7.235 2.208 8.245 2.808 ;
     RECT  7.516 5.664 8.291 6.84 ;
     RECT  8.245 0.144 8.293 2.808 ;
     RECT  8.195 12.528 8.483 16.728 ;
     RECT  8.293 0.144 8.525 3.768 ;
     RECT  8.236 10.272 8.531 11.4 ;
     RECT  8.291 6.192 8.629 6.84 ;
     RECT  8.531 10.8 8.737 11.4 ;
     RECT  8.483 12.528 8.737 12.552 ;
     RECT  8.629 6.192 8.821 6.936 ;
     RECT  8.821 6.192 9.157 7.416 ;
     RECT  8.236 9.072 9.157 9.096 ;
     RECT  9.157 6.192 9.245 9.096 ;
     RECT  8.525 0.288 9.277 3.768 ;
     RECT  8.483 13.632 9.353 16.728 ;
     RECT  9.277 0.288 9.461 4.008 ;
     RECT  8.737 10.8 9.589 12.552 ;
     RECT  9.461 2.784 9.673 4.008 ;
     RECT  9.589 10.8 9.685 13.128 ;
     RECT  9.245 6.24 9.745 9.096 ;
     RECT  9.745 6.24 9.749 9.144 ;
     RECT  9.685 10.752 9.749 13.128 ;
     RECT  9.749 10.752 9.827 10.776 ;
     RECT  9.461 0.288 10.213 1.8 ;
     RECT  9.749 6.24 10.316 6.936 ;
     RECT  9.749 11.952 10.321 13.128 ;
     RECT  9.353 14.112 10.321 16.728 ;
     RECT  9.673 2.784 10.493 4.488 ;
     RECT  10.316 5.616 10.493 6.936 ;
     RECT  10.213 0.24 10.508 1.8 ;
     RECT  10.493 2.784 10.508 6.936 ;
     RECT  9.749 8.016 10.556 9.144 ;
     RECT  10.165 10.272 10.556 10.296 ;
     RECT  10.321 11.952 10.645 16.728 ;
     RECT  10.508 0.24 10.825 6.936 ;
     RECT  10.556 8.016 10.837 10.296 ;
     RECT  10.645 11.952 11.005 16.776 ;
     RECT  10.825 0.192 11.048 6.936 ;
     RECT  10.837 7.92 11.048 10.296 ;
     RECT  11.005 11.952 11.048 16.824 ;
     RECT  11.048 0.192 11.344 16.824 ;
     RECT  11.344 14.64 11.401 16.824 ;
     RECT  11.344 0.192 11.405 13.176 ;
     RECT  11.405 0.192 11.411 13.128 ;
     RECT  11.411 0.288 11.441 13.128 ;
     RECT  11.401 14.64 11.459 16.92 ;
     RECT  11.441 8.496 11.621 13.128 ;
     RECT  11.441 0.288 11.693 7.368 ;
     RECT  11.459 14.736 11.725 16.92 ;
     RECT  11.693 2.688 11.909 7.368 ;
     RECT  11.909 4.848 11.945 7.368 ;
     RECT  11.621 9.792 12.241 13.128 ;
     RECT  11.945 5.088 12.556 7.368 ;
     RECT  12.241 9.792 12.557 11.736 ;
     RECT  12.556 7.344 12.659 7.368 ;
     RECT  11.693 0.288 12.661 1.704 ;
     RECT  11.909 2.688 12.661 3.432 ;
     RECT  11.725 14.736 12.757 16.968 ;
     RECT  12.757 14.688 12.899 16.968 ;
     RECT  12.899 14.688 12.997 16.728 ;
     RECT  12.661 0.288 13.021 3.432 ;
     RECT  13.021 0.288 13.165 3.48 ;
     RECT  12.557 10.272 13.177 11.736 ;
     RECT  12.556 5.088 13.187 6.312 ;
     RECT  12.553 13.152 13.201 13.176 ;
     RECT  12.997 14.208 13.201 16.728 ;
     RECT  13.165 0.288 13.244 3.96 ;
     RECT  13.187 5.088 13.244 6.264 ;
     RECT  13.201 13.152 13.321 16.728 ;
     RECT  13.244 0.288 13.331 6.264 ;
     RECT  13.331 4.944 13.393 6.264 ;
     RECT  13.177 10.8 13.477 11.736 ;
     RECT  13.393 4.944 13.523 5.784 ;
     RECT  11.621 8.496 13.529 8.52 ;
     RECT  13.417 7.392 13.697 7.416 ;
     RECT  13.697 7.392 13.781 7.464 ;
     RECT  13.477 10.8 13.804 12.552 ;
     RECT  13.523 4.944 13.859 5.736 ;
     RECT  13.804 10.8 14.147 11.016 ;
     RECT  14.147 10.8 14.243 10.872 ;
     RECT  13.331 0.288 14.329 3.96 ;
     RECT  13.859 4.992 14.38 5.736 ;
     RECT  13.804 12 14.387 12.552 ;
     RECT  14.329 0.288 14.389 3.432 ;
     RECT  14.38 4.992 14.465 5.16 ;
     RECT  14.465 5.088 14.483 5.16 ;
     RECT  14.387 12.336 14.533 12.552 ;
     RECT  13.321 13.632 14.533 16.728 ;
     RECT  14.245 6.768 14.569 7.272 ;
     RECT  13.777 9.12 14.581 9.144 ;
     RECT  14.533 12.336 14.609 16.728 ;
     RECT  14.243 10.8 14.629 10.824 ;
     RECT  14.609 14.256 14.789 16.728 ;
     RECT  14.629 10.224 14.825 10.824 ;
     RECT  14.569 6.24 14.857 7.272 ;
     RECT  14.581 8.352 14.857 9.144 ;
     RECT  14.857 6.24 14.969 9.144 ;
     RECT  14.825 10.272 15.059 10.824 ;
     RECT  14.969 9.024 15.073 9.144 ;
     RECT  15.073 9.024 15.203 9.192 ;
     RECT  14.389 0.192 15.257 3.432 ;
     RECT  15.257 0.24 15.347 3.432 ;
     RECT  14.609 12.336 15.397 13.08 ;
     RECT  14.789 14.544 15.437 16.728 ;
     RECT  15.347 2.88 15.445 3.432 ;
     RECT  15.445 2.88 15.493 3.864 ;
     RECT  14.483 5.088 15.541 5.112 ;
     RECT  14.969 6.24 15.541 7.992 ;
     RECT  15.397 12 15.692 13.08 ;
     RECT  15.692 10.896 15.733 13.08 ;
     RECT  15.733 10.896 16.021 13.512 ;
     RECT  15.493 2.88 16.045 3.96 ;
     RECT  16.045 2.88 16.117 4.008 ;
     RECT  15.203 9.12 16.165 9.144 ;
     RECT  15.347 0.24 16.225 1.848 ;
     RECT  16.225 0.144 16.448 1.848 ;
     RECT  16.117 2.88 16.448 4.104 ;
     RECT  15.541 5.088 16.448 7.992 ;
     RECT  16.165 9.072 16.448 9.144 ;
     RECT  16.021 10.176 16.448 13.512 ;
     RECT  15.437 14.64 16.448 16.728 ;
     RECT  16.448 0.144 16.661 16.728 ;
     RECT  16.661 0.192 16.741 16.728 ;
     RECT  16.741 0.192 16.744 16.824 ;
     RECT  16.744 0.192 16.805 7.992 ;
     RECT  16.744 13.296 16.873 16.824 ;
     RECT  16.873 13.296 16.883 17.064 ;
     RECT  16.805 0.192 16.949 6.888 ;
     RECT  16.744 9.12 16.979 10.968 ;
     RECT  16.883 13.344 17.027 17.064 ;
     RECT  16.805 7.968 17.057 7.992 ;
     RECT  16.949 0.288 17.219 6.888 ;
     RECT  16.979 9.12 17.459 10.824 ;
     RECT  17.459 10.752 17.989 10.824 ;
     RECT  17.989 10.752 18.131 10.872 ;
     RECT  17.219 3.408 18.169 6.888 ;
     RECT  17.459 9.12 18.181 9.672 ;
     RECT  18.131 10.752 18.371 10.824 ;
     RECT  18.181 9.072 18.385 9.672 ;
     RECT  17.219 0.288 18.565 2.376 ;
     RECT  18.169 3.408 18.565 7.416 ;
     RECT  18.385 8.592 18.601 9.672 ;
     RECT  17.027 13.344 18.613 16.728 ;
     RECT  18.565 0.288 18.641 7.416 ;
     RECT  18.601 8.544 18.709 9.672 ;
     RECT  18.641 5.616 18.757 7.416 ;
     RECT  18.709 8.544 18.757 10.248 ;
     RECT  18.641 0.288 18.817 4.632 ;
     RECT  18.757 5.616 18.821 10.248 ;
     RECT  18.613 13.104 19.073 16.728 ;
     RECT  19.073 13.104 19.237 16.632 ;
     RECT  18.821 9.408 19.253 10.248 ;
     RECT  18.817 0.192 19.331 4.632 ;
     RECT  19.237 12.576 19.357 16.632 ;
     RECT  19.357 12.528 19.433 16.632 ;
     RECT  19.501 11.424 19.619 11.448 ;
     RECT  19.331 0.288 19.669 4.632 ;
     RECT  18.821 5.616 19.669 8.376 ;
     RECT  19.433 14.016 19.763 16.632 ;
     RECT  19.669 0.288 19.955 8.376 ;
     RECT  19.253 9.408 20.003 9.96 ;
     RECT  19.955 2.208 20.101 8.376 ;
     RECT  19.433 12.528 20.329 12.552 ;
     RECT  20.101 2.208 20.531 9.192 ;
     RECT  20.329 12.192 20.54 12.552 ;
     RECT  20.531 4.608 20.585 9.192 ;
     RECT  20.54 12.192 20.627 12.936 ;
     RECT  20.581 10.848 20.629 10.872 ;
     RECT  20.627 12.192 20.629 12.216 ;
     RECT  19.763 14.016 20.725 16.584 ;
     RECT  20.585 5.712 20.773 9.192 ;
     RECT  20.585 4.608 20.837 4.632 ;
     RECT  20.725 14.016 20.861 16.68 ;
     RECT  20.861 13.632 21.205 16.68 ;
     RECT  20.773 6.24 21.253 9.192 ;
     RECT  20.629 10.848 21.253 12.216 ;
     RECT  19.955 0.288 21.265 1.176 ;
     RECT  21.265 0.192 21.445 1.176 ;
     RECT  20.531 2.208 21.445 3.432 ;
     RECT  21.253 6.24 21.661 12.216 ;
     RECT  21.205 13.632 21.661 16.728 ;
     RECT  21.661 6.24 21.769 16.728 ;
     RECT  21.445 0.192 21.848 3.432 ;
     RECT  21.637 4.656 21.848 4.68 ;
     RECT  21.769 6.24 21.848 16.824 ;
     RECT  21.848 0.192 22.021 16.824 ;
     RECT  22.021 0.192 22.144 16.872 ;
     RECT  22.144 7.872 22.165 16.872 ;
     RECT  22.144 4.656 22.205 4.68 ;
     RECT  22.165 7.872 22.277 16.92 ;
     RECT  22.277 7.872 22.781 16.728 ;
     RECT  22.781 7.872 22.931 9.096 ;
     RECT  22.781 10.08 22.961 16.728 ;
     RECT  22.961 10.224 23.249 16.728 ;
     RECT  23.249 10.224 23.356 16.68 ;
     RECT  22.144 5.712 23.461 6.888 ;
     RECT  22.931 7.968 23.573 9.096 ;
     RECT  22.144 0.192 23.597 3.432 ;
     RECT  23.356 10.224 23.869 16.584 ;
     RECT  23.869 12.528 23.905 16.584 ;
     RECT  23.597 0.192 23.941 3.96 ;
     RECT  23.461 5.088 23.941 6.888 ;
     RECT  23.869 10.224 24.109 11.448 ;
     RECT  23.573 7.968 24.257 8.472 ;
     RECT  23.941 0.192 24.329 6.888 ;
     RECT  24.329 0.192 24.508 3.768 ;
     RECT  24.329 4.992 24.661 6.888 ;
     RECT  24.508 0.288 24.689 3.768 ;
     RECT  23.905 12.528 24.901 12.552 ;
     RECT  23.905 13.536 24.901 16.584 ;
     RECT  24.901 12.528 25.189 16.584 ;
     RECT  24.257 7.968 25.237 7.992 ;
     RECT  24.109 9.648 25.237 11.448 ;
     RECT  24.689 3.696 25.283 3.768 ;
     RECT  25.237 7.968 25.333 11.448 ;
     RECT  25.189 12.528 25.333 16.68 ;
     RECT  25.283 3.696 25.373 3.72 ;
     RECT  24.661 4.992 25.517 6.984 ;
     RECT  24.689 0.288 25.765 2.712 ;
     RECT  25.517 5.088 25.909 6.984 ;
     RECT  25.333 7.968 25.909 16.68 ;
     RECT  25.909 5.088 26.053 16.68 ;
     RECT  25.765 0.288 26.101 3.672 ;
     RECT  26.053 5.088 26.101 16.776 ;
     RECT  26.101 5.088 26.243 16.872 ;
     RECT  26.243 5.088 26.273 16.632 ;
     RECT  26.101 0.192 26.801 3.672 ;
     RECT  26.273 5.088 26.801 13.224 ;
     RECT  26.801 0.192 26.989 13.224 ;
     RECT  26.989 0.096 27.248 13.224 ;
     RECT  26.273 14.352 27.248 16.632 ;
     RECT  27.248 0.096 27.353 16.632 ;
     RECT  27.353 0.192 27.388 16.632 ;
     RECT  27.388 0.288 27.425 16.632 ;
     RECT  27.425 0.336 27.445 16.632 ;
     RECT  27.445 0.336 27.493 16.728 ;
     RECT  27.493 0.336 27.544 16.824 ;
     RECT  27.544 13.728 27.605 16.824 ;
     RECT  27.544 0.336 27.677 8.184 ;
     RECT  27.677 0.384 27.683 8.184 ;
     RECT  27.544 9.168 27.685 10.776 ;
     RECT  27.685 10.608 27.731 10.776 ;
     RECT  27.683 3.744 27.749 7.464 ;
     RECT  27.685 9.168 27.749 9.624 ;
     RECT  27.749 3.744 27.827 6.84 ;
     RECT  27.605 13.728 27.929 16.728 ;
     RECT  27.827 3.744 27.971 5.928 ;
     RECT  27.731 10.752 28.001 10.776 ;
     RECT  27.971 3.744 28.037 5.688 ;
     RECT  28.037 3.744 28.115 4.872 ;
     RECT  27.683 0.384 28.259 2.712 ;
     RECT  28.259 0.384 28.397 2.28 ;
     RECT  27.749 9.168 28.499 9.192 ;
     RECT  27.929 13.728 28.499 16.44 ;
     RECT  28.397 0.384 28.505 2.232 ;
     RECT  28.499 14.304 28.577 16.44 ;
     RECT  28.577 15.984 28.621 16.44 ;
     RECT  28.115 3.744 28.732 3.96 ;
     RECT  28.681 10.992 28.765 11.016 ;
     RECT  28.621 16.032 28.793 16.44 ;
     RECT  28.505 1.152 28.829 2.232 ;
     RECT  28.577 14.304 28.873 15 ;
     RECT  28.789 8.496 28.876 8.52 ;
     RECT  28.873 14.304 28.883 14.904 ;
     RECT  28.883 14.88 28.937 14.904 ;
     RECT  29.005 7.44 29.036 7.464 ;
     RECT  28.981 5.904 29.068 5.928 ;
     RECT  28.793 16.032 29.075 16.2 ;
     RECT  29.077 4.512 29.084 4.536 ;
     RECT  29.036 7.44 29.089 8.376 ;
     RECT  29.089 8.352 29.123 8.376 ;
     RECT  29.036 11.376 29.123 11.4 ;
     RECT  29.075 16.176 29.123 16.2 ;
     RECT  29.084 4.512 29.171 4.872 ;
     RECT  28.829 2.208 29.297 2.232 ;
     RECT  29.077 3.36 29.297 3.384 ;
     RECT  29.171 4.512 29.405 4.536 ;
     RECT  29.645 1.104 29.729 1.128 ;
    LAYER M5 ;
     RECT  2.544 0.053 2.568 0.144 ;
     RECT  2.544 0.144 27.528 0.245 ;
     RECT  2.544 0.245 27.768 0.309 ;
     RECT  2.112 0.309 27.768 0.501 ;
     RECT  0.24 0.517 0.36 0.787 ;
     RECT  2.112 0.501 27.816 1.045 ;
     RECT  29.664 1.055 29.688 1.139 ;
     RECT  2.112 1.045 27.96 1.555 ;
     RECT  2.112 1.555 28.776 2.197 ;
     RECT  2.112 2.197 29.112 2.283 ;
     RECT  2.112 2.283 28.248 2.731 ;
     RECT  29.088 3.349 29.112 3.435 ;
     RECT  2.112 2.731 27.816 3.733 ;
     RECT  2.112 3.733 28.68 3.947 ;
     RECT  29.088 4.501 29.112 4.587 ;
     RECT  2.112 3.947 28.104 4.907 ;
     RECT  29.136 4.819 29.16 4.907 ;
     RECT  2.112 4.907 28.008 5.171 ;
     RECT  3.36 5.171 28.008 6.123 ;
     RECT  3.36 6.123 27.816 6.133 ;
     RECT  2.112 5.171 2.136 6.163 ;
     RECT  3.168 6.133 27.816 6.163 ;
     RECT  2.112 6.163 27.816 6.251 ;
     RECT  4.56 6.251 27.816 6.851 ;
     RECT  2.112 6.251 2.136 7.333 ;
     RECT  3.168 6.251 3.384 7.333 ;
     RECT  28.992 5.893 29.016 7.391 ;
     RECT  4.56 6.851 27.72 7.417 ;
     RECT  2.112 7.333 3.384 8.099 ;
     RECT  28.992 7.391 29.064 8.341 ;
     RECT  28.992 8.341 29.112 8.427 ;
     RECT  4.56 7.417 12.12 8.485 ;
     RECT  13.104 7.417 27.72 8.485 ;
     RECT  2.112 8.099 2.136 9.061 ;
     RECT  4.56 8.485 27.72 9.119 ;
     RECT  28.8 8.485 28.824 9.119 ;
     RECT  2.112 9.061 2.376 9.145 ;
     RECT  4.56 9.119 28.824 9.203 ;
     RECT  2.112 9.145 2.328 9.289 ;
     RECT  28.8 9.203 28.824 9.323 ;
     RECT  4.56 9.203 27.72 10.271 ;
     RECT  4.368 10.271 27.72 10.355 ;
     RECT  4.56 10.355 27.72 10.741 ;
     RECT  2.112 9.289 2.136 10.805 ;
     RECT  3.36 8.099 3.384 10.805 ;
     RECT  4.56 10.741 27.96 10.825 ;
     RECT  2.112 10.805 3.384 10.893 ;
     RECT  28.704 10.933 28.728 11.027 ;
     RECT  3.168 10.893 3.384 11.317 ;
     RECT  4.56 10.825 27.552 11.317 ;
     RECT  29.088 11.317 29.112 11.411 ;
     RECT  2.112 10.893 2.136 12.143 ;
     RECT  3.168 11.317 27.552 12.143 ;
     RECT  2.112 12.143 27.552 12.275 ;
     RECT  3.36 12.275 27.552 12.563 ;
     RECT  12.768 12.563 27.552 13.187 ;
     RECT  12.912 13.187 27.552 13.679 ;
     RECT  3.36 12.563 11.688 13.705 ;
     RECT  2.112 12.275 2.136 13.715 ;
     RECT  3.36 13.705 3.384 13.715 ;
     RECT  4.368 13.705 11.688 13.715 ;
     RECT  12.912 13.679 28.488 14.255 ;
     RECT  2.88 13.957 3.096 14.281 ;
     RECT  7.44 13.715 11.688 14.645 ;
     RECT  12.912 14.255 28.872 14.645 ;
     RECT  4.368 13.715 6.264 14.821 ;
     RECT  7.44 14.645 28.872 14.831 ;
     RECT  2.4 14.831 2.808 14.915 ;
     RECT  7.44 14.831 28.92 14.915 ;
     RECT  2.784 14.915 2.808 14.963 ;
     RECT  7.44 14.915 28.824 15.285 ;
     RECT  3.984 14.821 6.264 15.349 ;
     RECT  7.392 15.285 28.824 15.349 ;
     RECT  3.984 15.349 28.824 15.397 ;
     RECT  2.976 15.397 28.824 15.973 ;
     RECT  2.4 15.973 28.824 15.983 ;
     RECT  2.4 15.983 29.064 16.057 ;
     RECT  2.544 16.057 27.672 16.067 ;
     RECT  29.04 16.057 29.064 16.067 ;
     RECT  0.24 0.787 0.552 16.223 ;
     RECT  0.432 16.223 0.552 16.493 ;
     RECT  29.088 16.165 29.112 16.619 ;
     RECT  2.688 16.067 27.672 16.643 ;
     RECT  2.688 16.643 27.528 17.104 ;
    LAYER M6 ;
     RECT  0 0.996 2.101 1.86 ;
     RECT  2.101 0.32 2.149 1.86 ;
     RECT  2.149 0.32 2.165 2.272 ;
     RECT  2.229 9.216 2.339 9.248 ;
     RECT  2.357 16 2.389 16.032 ;
     RECT  2.341 9.088 2.411 9.12 ;
     RECT  2.165 0.32 2.533 2.336 ;
     RECT  0 6.396 2.533 7.26 ;
     RECT  2.533 0.064 2.581 2.336 ;
     RECT  2.485 3.712 2.581 3.744 ;
     RECT  2.533 6.396 2.603 7.904 ;
     RECT  0 11.796 2.725 12.66 ;
     RECT  2.389 14.848 2.741 16.032 ;
     RECT  2.725 10.816 2.795 12.66 ;
     RECT  2.581 0.064 2.805 3.744 ;
     RECT  2.741 14.848 2.85 16.608 ;
     RECT  2.603 6.396 2.965 7.26 ;
     RECT  2.795 11.328 3.445 12.66 ;
     RECT  2.85 14.016 3.445 16.608 ;
     RECT  2.805 0.064 3.95 4 ;
     RECT  2.965 6.208 3.95 7.26 ;
     RECT  3.445 11.328 4.021 16.8 ;
     RECT  4.021 11.328 4.334 16.864 ;
     RECT  4.334 10.304 4.547 16.864 ;
     RECT  4.547 10.304 4.643 16.608 ;
     RECT  4.643 10.304 4.981 12.768 ;
     RECT  4.981 10.24 5.075 12.768 ;
     RECT  4.643 14.272 5.123 16.608 ;
     RECT  3.95 0.064 5.267 7.26 ;
     RECT  5.075 10.304 5.355 12.768 ;
     RECT  5.355 11.328 5.611 12.768 ;
     RECT  5.267 5.632 5.749 7.26 ;
     RECT  5.123 14.272 6.083 16.032 ;
     RECT  6.083 14.848 6.202 16.032 ;
     RECT  5.267 0.064 6.709 3.936 ;
     RECT  5.749 5.632 6.709 7.392 ;
     RECT  6.709 0.064 6.803 7.392 ;
     RECT  6.202 15.296 6.997 16.032 ;
     RECT  5.611 11.328 7.029 12.66 ;
     RECT  6.803 5.632 7.214 7.392 ;
     RECT  7.214 5.632 7.283 8.608 ;
     RECT  7.283 5.632 7.475 7.392 ;
     RECT  7.029 10.24 7.475 12.66 ;
     RECT  7.669 9.728 7.738 10.016 ;
     RECT  6.997 15.296 7.979 16.608 ;
     RECT  7.475 11.328 8.181 12.66 ;
     RECT  7.738 9.984 8.235 10.016 ;
     RECT  8.181 11.328 8.235 13.472 ;
     RECT  6.803 0.064 8.293 3.424 ;
     RECT  8.293 0.064 8.363 3.744 ;
     RECT  8.363 3.712 8.435 3.744 ;
     RECT  7.979 15.296 8.491 15.456 ;
     RECT  8.501 3.776 8.723 3.808 ;
     RECT  8.235 11.796 9.301 13.472 ;
     RECT  9.301 11.796 9.387 13.728 ;
     RECT  8.491 15.424 9.845 15.456 ;
     RECT  9.845 15.424 9.877 16.736 ;
     RECT  7.475 6.396 9.925 7.392 ;
     RECT  9.877 15.296 10.101 16.736 ;
     RECT  9.925 6.272 10.213 7.392 ;
     RECT  8.363 0.064 10.286 2.272 ;
     RECT  10.213 6.208 10.338 7.392 ;
     RECT  10.338 5.632 10.741 7.392 ;
     RECT  10.741 5.632 10.835 8.48 ;
     RECT  10.835 5.632 10.869 7.392 ;
     RECT  9.387 11.796 10.933 13.472 ;
     RECT  10.101 14.784 10.933 16.736 ;
     RECT  10.933 11.796 11.363 16.736 ;
     RECT  11.363 11.796 11.371 16.608 ;
     RECT  10.597 10.048 11.381 10.08 ;
     RECT  10.869 4.864 11.507 7.392 ;
     RECT  10.286 0.064 11.509 2.848 ;
     RECT  11.381 10.048 11.989 10.336 ;
     RECT  11.371 11.796 11.989 12.66 ;
     RECT  11.989 10.048 12.227 12.66 ;
     RECT  11.371 14.656 12.523 16.608 ;
     RECT  12.227 10.304 12.757 12.66 ;
     RECT  11.509 0.064 12.917 3.36 ;
     RECT  12.757 10.304 12.922 13.152 ;
     RECT  11.507 5.952 12.949 7.392 ;
     RECT  12.917 0.064 13.285 4 ;
     RECT  12.922 10.816 13.381 13.152 ;
     RECT  13.285 0.064 13.794 4.32 ;
     RECT  12.949 5.632 13.794 7.392 ;
     RECT  12.523 15.36 13.813 16.608 ;
     RECT  13.381 10.816 14.005 13.728 ;
     RECT  13.813 15.296 14.005 16.608 ;
     RECT  14.005 10.816 14.266 16.608 ;
     RECT  13.794 0.064 14.291 7.392 ;
     RECT  14.291 5.632 14.339 7.392 ;
     RECT  14.266 10.816 14.339 16.032 ;
     RECT  14.291 3.776 14.379 4 ;
     RECT  14.339 10.816 14.379 12.768 ;
     RECT  14.291 0.064 14.507 2.272 ;
     RECT  14.339 6.396 14.645 7.392 ;
     RECT  14.379 11.796 14.827 12.768 ;
     RECT  14.645 6.396 15.157 8.224 ;
     RECT  15.157 6.396 15.226 9.184 ;
     RECT  14.379 3.968 15.539 4 ;
     RECT  14.827 11.796 15.733 12.66 ;
     RECT  15.226 6.396 15.797 8.992 ;
     RECT  15.797 5.952 15.979 8.992 ;
     RECT  14.339 14.848 16.021 16.032 ;
     RECT  16.021 14.848 16.046 16.608 ;
     RECT  14.507 0.768 16.117 2.272 ;
     RECT  16.117 0.384 16.245 2.272 ;
     RECT  15.979 5.952 16.309 8.224 ;
     RECT  16.046 14.784 16.437 16.608 ;
     RECT  16.245 0.384 16.499 3.36 ;
     RECT  16.309 5.504 16.555 8.224 ;
     RECT  16.437 14.592 16.683 16.608 ;
     RECT  15.733 11.072 16.757 12.66 ;
     RECT  16.757 11.072 16.814 13.152 ;
     RECT  16.683 14.592 16.814 16.032 ;
     RECT  16.499 0.832 16.883 3.36 ;
     RECT  16.814 11.072 16.933 16.032 ;
     RECT  16.933 10.816 17.075 16.032 ;
     RECT  17.317 3.84 17.507 3.872 ;
     RECT  16.883 0.996 17.699 2.272 ;
     RECT  17.075 11.072 17.795 16.032 ;
     RECT  17.589 3.904 18.035 3.936 ;
     RECT  17.795 15.168 18.037 16.032 ;
     RECT  18.037 15.168 18.106 16.608 ;
     RECT  17.795 11.072 18.155 13.728 ;
     RECT  17.699 0.996 18.325 1.86 ;
     RECT  18.037 9.664 18.515 9.696 ;
     RECT  16.555 5.952 18.613 8.224 ;
     RECT  18.613 5.952 18.682 8.608 ;
     RECT  18.421 4.544 18.851 4.576 ;
     RECT  18.325 0.832 19.189 1.86 ;
     RECT  19.189 0.384 19.237 1.86 ;
     RECT  18.106 15.168 19.31 16.032 ;
     RECT  19.237 0.384 19.317 2.016 ;
     RECT  19.31 14.912 19.621 16.032 ;
     RECT  19.317 0.256 19.627 2.016 ;
     RECT  18.155 11.072 19.701 12.66 ;
     RECT  18.682 5.952 20.203 8.224 ;
     RECT  19.621 14.912 20.213 16.608 ;
     RECT  19.701 9.984 20.245 12.66 ;
     RECT  19.627 0.996 20.277 2.016 ;
     RECT  20.277 0.996 20.293 2.72 ;
     RECT  20.213 14.912 20.341 16.736 ;
     RECT  20.293 0.996 20.395 3.872 ;
     RECT  20.245 8.896 20.405 12.66 ;
     RECT  20.341 14.272 20.41 16.736 ;
     RECT  20.395 0.996 20.907 3.296 ;
     RECT  20.907 0.996 20.917 2.272 ;
     RECT  20.41 14.784 21.635 16.736 ;
     RECT  20.405 8.896 21.685 12.96 ;
     RECT  20.203 6.016 21.733 7.26 ;
     RECT  21.685 8.896 21.733 13.152 ;
     RECT  20.917 0.832 21.858 2.272 ;
     RECT  21.858 0.256 21.931 2.272 ;
     RECT  21.931 0.384 22.067 2.272 ;
     RECT  22.067 0.512 22.259 2.272 ;
     RECT  22.259 0.832 22.307 2.272 ;
     RECT  22.309 3.264 22.325 3.296 ;
     RECT  21.733 6.016 22.955 13.728 ;
     RECT  22.955 9.088 23.221 13.728 ;
     RECT  21.635 15.424 23.221 16.736 ;
     RECT  23.221 9.088 23.411 16.736 ;
     RECT  22.325 3.264 23.541 3.424 ;
     RECT  22.307 0.832 23.669 1.86 ;
     RECT  23.541 3.264 23.669 4.576 ;
     RECT  23.669 0.832 23.674 4.576 ;
     RECT  23.674 0.832 24.037 2.848 ;
     RECT  23.674 4.544 24.309 4.576 ;
     RECT  22.955 6.016 24.309 7.26 ;
     RECT  24.309 4.544 24.563 7.26 ;
     RECT  23.411 9.664 25.003 16.736 ;
     RECT  25.003 14.144 25.141 16.736 ;
     RECT  25.003 9.664 25.235 12.768 ;
     RECT  24.037 0.256 25.237 2.848 ;
     RECT  25.237 0.256 25.323 3.808 ;
     RECT  25.235 9.664 25.333 12.66 ;
     RECT  24.563 5.376 25.461 7.26 ;
     RECT  25.333 8.576 25.461 12.66 ;
     RECT  25.461 5.376 25.715 12.66 ;
     RECT  25.141 14.144 26.197 16.864 ;
     RECT  25.715 5.504 26.869 12.66 ;
     RECT  25.323 0.256 26.917 3.36 ;
     RECT  26.197 14.144 26.923 16.992 ;
     RECT  26.923 14.144 27.371 16.864 ;
     RECT  26.917 0.256 27.381 3.872 ;
     RECT  27.371 14.144 27.563 16.736 ;
     RECT  27.381 0.256 27.618 3.936 ;
     RECT  26.869 5.504 27.618 12.768 ;
     RECT  27.618 0.256 27.637 12.768 ;
     RECT  27.563 14.144 27.637 16.608 ;
     RECT  27.637 0.256 27.683 16.608 ;
     RECT  27.683 0.256 27.779 9.312 ;
     RECT  27.779 0.512 27.827 9.312 ;
     RECT  27.683 10.752 27.971 16.608 ;
     RECT  27.827 1.088 28.019 9.312 ;
     RECT  28.019 6.972 28.144 9.312 ;
     RECT  27.971 10.944 28.144 16.608 ;
     RECT  28.144 13.696 28.523 16.608 ;
     RECT  28.144 10.944 28.779 11.36 ;
     RECT  28.144 7.424 28.835 9.312 ;
     RECT  28.523 14.272 28.907 16.608 ;
     RECT  28.907 14.848 28.971 16.608 ;
     RECT  28.835 7.424 29.075 8.416 ;
     RECT  28.019 1.088 29.123 4.896 ;
     RECT  29.075 8.384 29.123 8.416 ;
     RECT  28.779 11.328 29.123 11.36 ;
     RECT  28.971 16 29.123 16.608 ;
     RECT  29.123 16 29.163 16.032 ;
     RECT  29.123 4.864 29.182 4.896 ;
     RECT  29.123 1.088 29.699 1.12 ;
    LAYER M7 ;
     RECT  21.888 0.245 21.92 0.373 ;
     RECT  21.888 0.373 21.984 0.501 ;
     RECT  11.072 0.373 11.104 0.531 ;
     RECT  21.888 0.501 22.048 0.531 ;
     RECT  3.2 0.245 3.232 0.693 ;
     RECT  4.864 0.245 4.896 0.693 ;
     RECT  14.464 0.053 14.496 0.757 ;
     RECT  3.2 0.693 4.896 0.821 ;
     RECT  6.256 0.531 6.544 0.821 ;
     RECT  11.072 0.531 11.944 0.821 ;
     RECT  14.464 0.757 15.136 0.821 ;
     RECT  17.056 0.531 17.344 0.821 ;
     RECT  19.328 0.245 19.616 0.821 ;
     RECT  21.888 0.531 22.744 0.821 ;
     RECT  24.064 0.245 24.096 0.821 ;
     RECT  27.856 0.531 28.144 0.821 ;
     RECT  20.928 0.821 28.144 1.077 ;
     RECT  2.432 0.821 4.896 1.397 ;
     RECT  6.256 0.821 6.816 1.397 ;
     RECT  8.128 0.821 9.376 1.397 ;
     RECT  11.072 0.821 12.832 1.397 ;
     RECT  14.272 0.821 15.136 1.397 ;
     RECT  16.832 0.821 19.616 1.397 ;
     RECT  2.432 1.397 6.816 2.101 ;
     RECT  8.128 1.397 19.616 2.101 ;
     RECT  0.856 0.531 1.144 2.229 ;
     RECT  2.432 2.101 19.616 2.229 ;
     RECT  20.928 1.077 29.024 2.229 ;
     RECT  0.856 2.229 29.024 4.853 ;
     RECT  0.856 4.853 29.152 15.467 ;
     RECT  0.856 15.467 7.968 16.043 ;
     RECT  9.856 15.467 29.152 16.043 ;
     RECT  0.856 16.043 1.144 16.479 ;
     RECT  2.752 16.043 7.968 16.479 ;
     RECT  16.064 16.043 18.08 16.479 ;
     RECT  19.712 16.043 28.144 16.479 ;
     RECT  2.752 16.479 5.024 16.619 ;
     RECT  7.04 16.479 7.968 16.619 ;
     RECT  9.856 16.043 14.24 16.619 ;
     RECT  16.064 16.479 16.672 16.619 ;
     RECT  18.048 16.479 18.08 16.619 ;
     RECT  19.712 16.479 27.552 16.619 ;
     RECT  3.456 16.619 4.128 16.747 ;
     RECT  9.856 16.619 10.848 16.747 ;
     RECT  20.224 16.619 20.256 16.747 ;
     RECT  21.632 16.619 22.176 16.747 ;
     RECT  23.488 16.619 27.552 16.747 ;
     RECT  3.456 16.747 4.064 16.811 ;
     RECT  4.032 16.811 4.064 16.875 ;
     RECT  25.152 16.747 27.36 16.875 ;
     RECT  26.24 16.875 26.912 17.003 ;
  END
END dsfd_stnv_514x1
END LIBRARY
